VERSION 5.7 ;
BUSBITCHARS "[]" ;
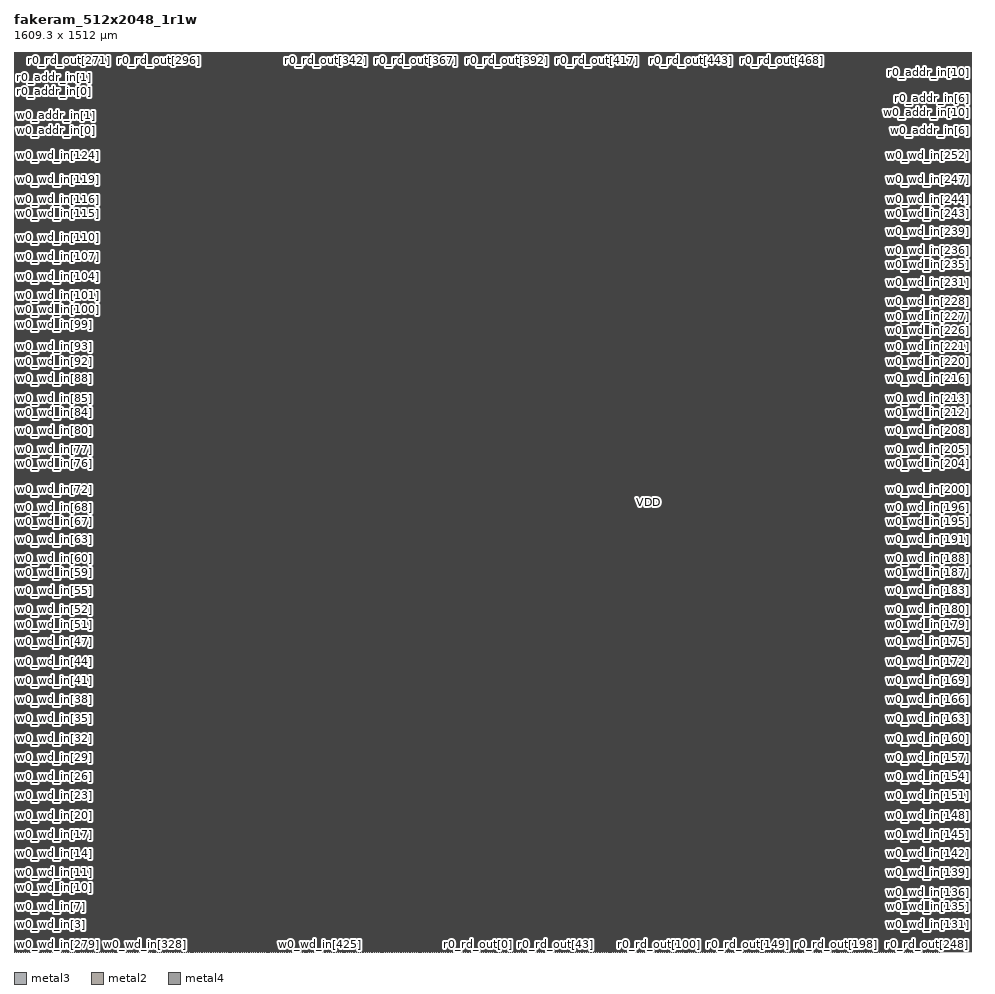
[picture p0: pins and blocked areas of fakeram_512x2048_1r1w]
MACRO fakeram_512x2048_1r1w
  FOREIGN fakeram_512x2048_1r1w 0 0 ;
  SYMMETRY X Y R90 ;
  SIZE 1609.300 BY 1512.000 ;
  CLASS BLOCK ;
  PIN w0_wd_in[0]
    DIRECTION INPUT ;
    USE SIGNAL ;
    SHAPE ABUTMENT ;
    PORT
      LAYER metal3 ;
      RECT 0.000 0.805 0.210 0.875 ;
    END
  END w0_wd_in[0]
  PIN w0_wd_in[1]
    DIRECTION INPUT ;
    USE SIGNAL ;
    SHAPE ABUTMENT ;
    PORT
      LAYER metal3 ;
      RECT 0.000 11.585 0.210 11.655 ;
    END
  END w0_wd_in[1]
  PIN w0_wd_in[2]
    DIRECTION INPUT ;
    USE SIGNAL ;
    SHAPE ABUTMENT ;
    PORT
      LAYER metal3 ;
      RECT 0.000 22.365 0.210 22.435 ;
    END
  END w0_wd_in[2]
  PIN w0_wd_in[3]
    DIRECTION INPUT ;
    USE SIGNAL ;
    SHAPE ABUTMENT ;
    PORT
      LAYER metal3 ;
      RECT 0.000 33.145 0.210 33.215 ;
    END
  END w0_wd_in[3]
  PIN w0_wd_in[4]
    DIRECTION INPUT ;
    USE SIGNAL ;
    SHAPE ABUTMENT ;
    PORT
      LAYER metal3 ;
      RECT 0.000 43.925 0.210 43.995 ;
    END
  END w0_wd_in[4]
  PIN w0_wd_in[5]
    DIRECTION INPUT ;
    USE SIGNAL ;
    SHAPE ABUTMENT ;
    PORT
      LAYER metal3 ;
      RECT 0.000 54.705 0.210 54.775 ;
    END
  END w0_wd_in[5]
  PIN w0_wd_in[6]
    DIRECTION INPUT ;
    USE SIGNAL ;
    SHAPE ABUTMENT ;
    PORT
      LAYER metal3 ;
      RECT 0.000 65.485 0.210 65.555 ;
    END
  END w0_wd_in[6]
  PIN w0_wd_in[7]
    DIRECTION INPUT ;
    USE SIGNAL ;
    SHAPE ABUTMENT ;
    PORT
      LAYER metal3 ;
      RECT 0.000 76.265 0.210 76.335 ;
    END
  END w0_wd_in[7]
  PIN w0_wd_in[8]
    DIRECTION INPUT ;
    USE SIGNAL ;
    SHAPE ABUTMENT ;
    PORT
      LAYER metal3 ;
      RECT 0.000 87.045 0.210 87.115 ;
    END
  END w0_wd_in[8]
  PIN w0_wd_in[9]
    DIRECTION INPUT ;
    USE SIGNAL ;
    SHAPE ABUTMENT ;
    PORT
      LAYER metal3 ;
      RECT 0.000 97.825 0.210 97.895 ;
    END
  END w0_wd_in[9]
  PIN w0_wd_in[10]
    DIRECTION INPUT ;
    USE SIGNAL ;
    SHAPE ABUTMENT ;
    PORT
      LAYER metal3 ;
      RECT 0.000 108.605 0.210 108.675 ;
    END
  END w0_wd_in[10]
  PIN w0_wd_in[11]
    DIRECTION INPUT ;
    USE SIGNAL ;
    SHAPE ABUTMENT ;
    PORT
      LAYER metal3 ;
      RECT 0.000 119.385 0.210 119.455 ;
    END
  END w0_wd_in[11]
  PIN w0_wd_in[12]
    DIRECTION INPUT ;
    USE SIGNAL ;
    SHAPE ABUTMENT ;
    PORT
      LAYER metal3 ;
      RECT 0.000 130.165 0.210 130.235 ;
    END
  END w0_wd_in[12]
  PIN w0_wd_in[13]
    DIRECTION INPUT ;
    USE SIGNAL ;
    SHAPE ABUTMENT ;
    PORT
      LAYER metal3 ;
      RECT 0.000 140.945 0.210 141.015 ;
    END
  END w0_wd_in[13]
  PIN w0_wd_in[14]
    DIRECTION INPUT ;
    USE SIGNAL ;
    SHAPE ABUTMENT ;
    PORT
      LAYER metal3 ;
      RECT 0.000 151.725 0.210 151.795 ;
    END
  END w0_wd_in[14]
  PIN w0_wd_in[15]
    DIRECTION INPUT ;
    USE SIGNAL ;
    SHAPE ABUTMENT ;
    PORT
      LAYER metal3 ;
      RECT 0.000 162.505 0.210 162.575 ;
    END
  END w0_wd_in[15]
  PIN w0_wd_in[16]
    DIRECTION INPUT ;
    USE SIGNAL ;
    SHAPE ABUTMENT ;
    PORT
      LAYER metal3 ;
      RECT 0.000 173.285 0.210 173.355 ;
    END
  END w0_wd_in[16]
  PIN w0_wd_in[17]
    DIRECTION INPUT ;
    USE SIGNAL ;
    SHAPE ABUTMENT ;
    PORT
      LAYER metal3 ;
      RECT 0.000 184.065 0.210 184.135 ;
    END
  END w0_wd_in[17]
  PIN w0_wd_in[18]
    DIRECTION INPUT ;
    USE SIGNAL ;
    SHAPE ABUTMENT ;
    PORT
      LAYER metal3 ;
      RECT 0.000 194.845 0.210 194.915 ;
    END
  END w0_wd_in[18]
  PIN w0_wd_in[19]
    DIRECTION INPUT ;
    USE SIGNAL ;
    SHAPE ABUTMENT ;
    PORT
      LAYER metal3 ;
      RECT 0.000 205.625 0.210 205.695 ;
    END
  END w0_wd_in[19]
  PIN w0_wd_in[20]
    DIRECTION INPUT ;
    USE SIGNAL ;
    SHAPE ABUTMENT ;
    PORT
      LAYER metal3 ;
      RECT 0.000 216.405 0.210 216.475 ;
    END
  END w0_wd_in[20]
  PIN w0_wd_in[21]
    DIRECTION INPUT ;
    USE SIGNAL ;
    SHAPE ABUTMENT ;
    PORT
      LAYER metal3 ;
      RECT 0.000 227.185 0.210 227.255 ;
    END
  END w0_wd_in[21]
  PIN w0_wd_in[22]
    DIRECTION INPUT ;
    USE SIGNAL ;
    SHAPE ABUTMENT ;
    PORT
      LAYER metal3 ;
      RECT 0.000 237.965 0.210 238.035 ;
    END
  END w0_wd_in[22]
  PIN w0_wd_in[23]
    DIRECTION INPUT ;
    USE SIGNAL ;
    SHAPE ABUTMENT ;
    PORT
      LAYER metal3 ;
      RECT 0.000 248.745 0.210 248.815 ;
    END
  END w0_wd_in[23]
  PIN w0_wd_in[24]
    DIRECTION INPUT ;
    USE SIGNAL ;
    SHAPE ABUTMENT ;
    PORT
      LAYER metal3 ;
      RECT 0.000 259.525 0.210 259.595 ;
    END
  END w0_wd_in[24]
  PIN w0_wd_in[25]
    DIRECTION INPUT ;
    USE SIGNAL ;
    SHAPE ABUTMENT ;
    PORT
      LAYER metal3 ;
      RECT 0.000 270.305 0.210 270.375 ;
    END
  END w0_wd_in[25]
  PIN w0_wd_in[26]
    DIRECTION INPUT ;
    USE SIGNAL ;
    SHAPE ABUTMENT ;
    PORT
      LAYER metal3 ;
      RECT 0.000 281.085 0.210 281.155 ;
    END
  END w0_wd_in[26]
  PIN w0_wd_in[27]
    DIRECTION INPUT ;
    USE SIGNAL ;
    SHAPE ABUTMENT ;
    PORT
      LAYER metal3 ;
      RECT 0.000 291.865 0.210 291.935 ;
    END
  END w0_wd_in[27]
  PIN w0_wd_in[28]
    DIRECTION INPUT ;
    USE SIGNAL ;
    SHAPE ABUTMENT ;
    PORT
      LAYER metal3 ;
      RECT 0.000 302.645 0.210 302.715 ;
    END
  END w0_wd_in[28]
  PIN w0_wd_in[29]
    DIRECTION INPUT ;
    USE SIGNAL ;
    SHAPE ABUTMENT ;
    PORT
      LAYER metal3 ;
      RECT 0.000 313.425 0.210 313.495 ;
    END
  END w0_wd_in[29]
  PIN w0_wd_in[30]
    DIRECTION INPUT ;
    USE SIGNAL ;
    SHAPE ABUTMENT ;
    PORT
      LAYER metal3 ;
      RECT 0.000 324.205 0.210 324.275 ;
    END
  END w0_wd_in[30]
  PIN w0_wd_in[31]
    DIRECTION INPUT ;
    USE SIGNAL ;
    SHAPE ABUTMENT ;
    PORT
      LAYER metal3 ;
      RECT 0.000 334.985 0.210 335.055 ;
    END
  END w0_wd_in[31]
  PIN w0_wd_in[32]
    DIRECTION INPUT ;
    USE SIGNAL ;
    SHAPE ABUTMENT ;
    PORT
      LAYER metal3 ;
      RECT 0.000 345.765 0.210 345.835 ;
    END
  END w0_wd_in[32]
  PIN w0_wd_in[33]
    DIRECTION INPUT ;
    USE SIGNAL ;
    SHAPE ABUTMENT ;
    PORT
      LAYER metal3 ;
      RECT 0.000 356.545 0.210 356.615 ;
    END
  END w0_wd_in[33]
  PIN w0_wd_in[34]
    DIRECTION INPUT ;
    USE SIGNAL ;
    SHAPE ABUTMENT ;
    PORT
      LAYER metal3 ;
      RECT 0.000 367.325 0.210 367.395 ;
    END
  END w0_wd_in[34]
  PIN w0_wd_in[35]
    DIRECTION INPUT ;
    USE SIGNAL ;
    SHAPE ABUTMENT ;
    PORT
      LAYER metal3 ;
      RECT 0.000 378.105 0.210 378.175 ;
    END
  END w0_wd_in[35]
  PIN w0_wd_in[36]
    DIRECTION INPUT ;
    USE SIGNAL ;
    SHAPE ABUTMENT ;
    PORT
      LAYER metal3 ;
      RECT 0.000 388.885 0.210 388.955 ;
    END
  END w0_wd_in[36]
  PIN w0_wd_in[37]
    DIRECTION INPUT ;
    USE SIGNAL ;
    SHAPE ABUTMENT ;
    PORT
      LAYER metal3 ;
      RECT 0.000 399.665 0.210 399.735 ;
    END
  END w0_wd_in[37]
  PIN w0_wd_in[38]
    DIRECTION INPUT ;
    USE SIGNAL ;
    SHAPE ABUTMENT ;
    PORT
      LAYER metal3 ;
      RECT 0.000 410.445 0.210 410.515 ;
    END
  END w0_wd_in[38]
  PIN w0_wd_in[39]
    DIRECTION INPUT ;
    USE SIGNAL ;
    SHAPE ABUTMENT ;
    PORT
      LAYER metal3 ;
      RECT 0.000 421.225 0.210 421.295 ;
    END
  END w0_wd_in[39]
  PIN w0_wd_in[40]
    DIRECTION INPUT ;
    USE SIGNAL ;
    SHAPE ABUTMENT ;
    PORT
      LAYER metal3 ;
      RECT 0.000 432.005 0.210 432.075 ;
    END
  END w0_wd_in[40]
  PIN w0_wd_in[41]
    DIRECTION INPUT ;
    USE SIGNAL ;
    SHAPE ABUTMENT ;
    PORT
      LAYER metal3 ;
      RECT 0.000 442.785 0.210 442.855 ;
    END
  END w0_wd_in[41]
  PIN w0_wd_in[42]
    DIRECTION INPUT ;
    USE SIGNAL ;
    SHAPE ABUTMENT ;
    PORT
      LAYER metal3 ;
      RECT 0.000 453.565 0.210 453.635 ;
    END
  END w0_wd_in[42]
  PIN w0_wd_in[43]
    DIRECTION INPUT ;
    USE SIGNAL ;
    SHAPE ABUTMENT ;
    PORT
      LAYER metal3 ;
      RECT 0.000 464.345 0.210 464.415 ;
    END
  END w0_wd_in[43]
  PIN w0_wd_in[44]
    DIRECTION INPUT ;
    USE SIGNAL ;
    SHAPE ABUTMENT ;
    PORT
      LAYER metal3 ;
      RECT 0.000 475.125 0.210 475.195 ;
    END
  END w0_wd_in[44]
  PIN w0_wd_in[45]
    DIRECTION INPUT ;
    USE SIGNAL ;
    SHAPE ABUTMENT ;
    PORT
      LAYER metal3 ;
      RECT 0.000 485.905 0.210 485.975 ;
    END
  END w0_wd_in[45]
  PIN w0_wd_in[46]
    DIRECTION INPUT ;
    USE SIGNAL ;
    SHAPE ABUTMENT ;
    PORT
      LAYER metal3 ;
      RECT 0.000 496.685 0.210 496.755 ;
    END
  END w0_wd_in[46]
  PIN w0_wd_in[47]
    DIRECTION INPUT ;
    USE SIGNAL ;
    SHAPE ABUTMENT ;
    PORT
      LAYER metal3 ;
      RECT 0.000 507.465 0.210 507.535 ;
    END
  END w0_wd_in[47]
  PIN w0_wd_in[48]
    DIRECTION INPUT ;
    USE SIGNAL ;
    SHAPE ABUTMENT ;
    PORT
      LAYER metal3 ;
      RECT 0.000 518.245 0.210 518.315 ;
    END
  END w0_wd_in[48]
  PIN w0_wd_in[49]
    DIRECTION INPUT ;
    USE SIGNAL ;
    SHAPE ABUTMENT ;
    PORT
      LAYER metal3 ;
      RECT 0.000 529.025 0.210 529.095 ;
    END
  END w0_wd_in[49]
  PIN w0_wd_in[50]
    DIRECTION INPUT ;
    USE SIGNAL ;
    SHAPE ABUTMENT ;
    PORT
      LAYER metal3 ;
      RECT 0.000 539.805 0.210 539.875 ;
    END
  END w0_wd_in[50]
  PIN w0_wd_in[51]
    DIRECTION INPUT ;
    USE SIGNAL ;
    SHAPE ABUTMENT ;
    PORT
      LAYER metal3 ;
      RECT 0.000 550.585 0.210 550.655 ;
    END
  END w0_wd_in[51]
  PIN w0_wd_in[52]
    DIRECTION INPUT ;
    USE SIGNAL ;
    SHAPE ABUTMENT ;
    PORT
      LAYER metal3 ;
      RECT 0.000 561.365 0.210 561.435 ;
    END
  END w0_wd_in[52]
  PIN w0_wd_in[53]
    DIRECTION INPUT ;
    USE SIGNAL ;
    SHAPE ABUTMENT ;
    PORT
      LAYER metal3 ;
      RECT 0.000 572.145 0.210 572.215 ;
    END
  END w0_wd_in[53]
  PIN w0_wd_in[54]
    DIRECTION INPUT ;
    USE SIGNAL ;
    SHAPE ABUTMENT ;
    PORT
      LAYER metal3 ;
      RECT 0.000 582.925 0.210 582.995 ;
    END
  END w0_wd_in[54]
  PIN w0_wd_in[55]
    DIRECTION INPUT ;
    USE SIGNAL ;
    SHAPE ABUTMENT ;
    PORT
      LAYER metal3 ;
      RECT 0.000 593.705 0.210 593.775 ;
    END
  END w0_wd_in[55]
  PIN w0_wd_in[56]
    DIRECTION INPUT ;
    USE SIGNAL ;
    SHAPE ABUTMENT ;
    PORT
      LAYER metal3 ;
      RECT 0.000 604.485 0.210 604.555 ;
    END
  END w0_wd_in[56]
  PIN w0_wd_in[57]
    DIRECTION INPUT ;
    USE SIGNAL ;
    SHAPE ABUTMENT ;
    PORT
      LAYER metal3 ;
      RECT 0.000 615.265 0.210 615.335 ;
    END
  END w0_wd_in[57]
  PIN w0_wd_in[58]
    DIRECTION INPUT ;
    USE SIGNAL ;
    SHAPE ABUTMENT ;
    PORT
      LAYER metal3 ;
      RECT 0.000 626.045 0.210 626.115 ;
    END
  END w0_wd_in[58]
  PIN w0_wd_in[59]
    DIRECTION INPUT ;
    USE SIGNAL ;
    SHAPE ABUTMENT ;
    PORT
      LAYER metal3 ;
      RECT 0.000 636.825 0.210 636.895 ;
    END
  END w0_wd_in[59]
  PIN w0_wd_in[60]
    DIRECTION INPUT ;
    USE SIGNAL ;
    SHAPE ABUTMENT ;
    PORT
      LAYER metal3 ;
      RECT 0.000 647.605 0.210 647.675 ;
    END
  END w0_wd_in[60]
  PIN w0_wd_in[61]
    DIRECTION INPUT ;
    USE SIGNAL ;
    SHAPE ABUTMENT ;
    PORT
      LAYER metal3 ;
      RECT 0.000 658.385 0.210 658.455 ;
    END
  END w0_wd_in[61]
  PIN w0_wd_in[62]
    DIRECTION INPUT ;
    USE SIGNAL ;
    SHAPE ABUTMENT ;
    PORT
      LAYER metal3 ;
      RECT 0.000 669.165 0.210 669.235 ;
    END
  END w0_wd_in[62]
  PIN w0_wd_in[63]
    DIRECTION INPUT ;
    USE SIGNAL ;
    SHAPE ABUTMENT ;
    PORT
      LAYER metal3 ;
      RECT 0.000 679.945 0.210 680.015 ;
    END
  END w0_wd_in[63]
  PIN w0_wd_in[64]
    DIRECTION INPUT ;
    USE SIGNAL ;
    SHAPE ABUTMENT ;
    PORT
      LAYER metal3 ;
      RECT 0.000 690.725 0.210 690.795 ;
    END
  END w0_wd_in[64]
  PIN w0_wd_in[65]
    DIRECTION INPUT ;
    USE SIGNAL ;
    SHAPE ABUTMENT ;
    PORT
      LAYER metal3 ;
      RECT 0.000 701.505 0.210 701.575 ;
    END
  END w0_wd_in[65]
  PIN w0_wd_in[66]
    DIRECTION INPUT ;
    USE SIGNAL ;
    SHAPE ABUTMENT ;
    PORT
      LAYER metal3 ;
      RECT 0.000 712.285 0.210 712.355 ;
    END
  END w0_wd_in[66]
  PIN w0_wd_in[67]
    DIRECTION INPUT ;
    USE SIGNAL ;
    SHAPE ABUTMENT ;
    PORT
      LAYER metal3 ;
      RECT 0.000 723.065 0.210 723.135 ;
    END
  END w0_wd_in[67]
  PIN w0_wd_in[68]
    DIRECTION INPUT ;
    USE SIGNAL ;
    SHAPE ABUTMENT ;
    PORT
      LAYER metal3 ;
      RECT 0.000 733.845 0.210 733.915 ;
    END
  END w0_wd_in[68]
  PIN w0_wd_in[69]
    DIRECTION INPUT ;
    USE SIGNAL ;
    SHAPE ABUTMENT ;
    PORT
      LAYER metal3 ;
      RECT 0.000 744.625 0.210 744.695 ;
    END
  END w0_wd_in[69]
  PIN w0_wd_in[70]
    DIRECTION INPUT ;
    USE SIGNAL ;
    SHAPE ABUTMENT ;
    PORT
      LAYER metal3 ;
      RECT 0.000 755.405 0.210 755.475 ;
    END
  END w0_wd_in[70]
  PIN w0_wd_in[71]
    DIRECTION INPUT ;
    USE SIGNAL ;
    SHAPE ABUTMENT ;
    PORT
      LAYER metal3 ;
      RECT 0.000 766.185 0.210 766.255 ;
    END
  END w0_wd_in[71]
  PIN w0_wd_in[72]
    DIRECTION INPUT ;
    USE SIGNAL ;
    SHAPE ABUTMENT ;
    PORT
      LAYER metal3 ;
      RECT 0.000 776.965 0.210 777.035 ;
    END
  END w0_wd_in[72]
  PIN w0_wd_in[73]
    DIRECTION INPUT ;
    USE SIGNAL ;
    SHAPE ABUTMENT ;
    PORT
      LAYER metal3 ;
      RECT 0.000 787.745 0.210 787.815 ;
    END
  END w0_wd_in[73]
  PIN w0_wd_in[74]
    DIRECTION INPUT ;
    USE SIGNAL ;
    SHAPE ABUTMENT ;
    PORT
      LAYER metal3 ;
      RECT 0.000 798.525 0.210 798.595 ;
    END
  END w0_wd_in[74]
  PIN w0_wd_in[75]
    DIRECTION INPUT ;
    USE SIGNAL ;
    SHAPE ABUTMENT ;
    PORT
      LAYER metal3 ;
      RECT 0.000 809.305 0.210 809.375 ;
    END
  END w0_wd_in[75]
  PIN w0_wd_in[76]
    DIRECTION INPUT ;
    USE SIGNAL ;
    SHAPE ABUTMENT ;
    PORT
      LAYER metal3 ;
      RECT 0.000 820.085 0.210 820.155 ;
    END
  END w0_wd_in[76]
  PIN w0_wd_in[77]
    DIRECTION INPUT ;
    USE SIGNAL ;
    SHAPE ABUTMENT ;
    PORT
      LAYER metal3 ;
      RECT 0.000 830.865 0.210 830.935 ;
    END
  END w0_wd_in[77]
  PIN w0_wd_in[78]
    DIRECTION INPUT ;
    USE SIGNAL ;
    SHAPE ABUTMENT ;
    PORT
      LAYER metal3 ;
      RECT 0.000 841.645 0.210 841.715 ;
    END
  END w0_wd_in[78]
  PIN w0_wd_in[79]
    DIRECTION INPUT ;
    USE SIGNAL ;
    SHAPE ABUTMENT ;
    PORT
      LAYER metal3 ;
      RECT 0.000 852.425 0.210 852.495 ;
    END
  END w0_wd_in[79]
  PIN w0_wd_in[80]
    DIRECTION INPUT ;
    USE SIGNAL ;
    SHAPE ABUTMENT ;
    PORT
      LAYER metal3 ;
      RECT 0.000 863.205 0.210 863.275 ;
    END
  END w0_wd_in[80]
  PIN w0_wd_in[81]
    DIRECTION INPUT ;
    USE SIGNAL ;
    SHAPE ABUTMENT ;
    PORT
      LAYER metal3 ;
      RECT 0.000 873.985 0.210 874.055 ;
    END
  END w0_wd_in[81]
  PIN w0_wd_in[82]
    DIRECTION INPUT ;
    USE SIGNAL ;
    SHAPE ABUTMENT ;
    PORT
      LAYER metal3 ;
      RECT 0.000 884.765 0.210 884.835 ;
    END
  END w0_wd_in[82]
  PIN w0_wd_in[83]
    DIRECTION INPUT ;
    USE SIGNAL ;
    SHAPE ABUTMENT ;
    PORT
      LAYER metal3 ;
      RECT 0.000 895.545 0.210 895.615 ;
    END
  END w0_wd_in[83]
  PIN w0_wd_in[84]
    DIRECTION INPUT ;
    USE SIGNAL ;
    SHAPE ABUTMENT ;
    PORT
      LAYER metal3 ;
      RECT 0.000 906.325 0.210 906.395 ;
    END
  END w0_wd_in[84]
  PIN w0_wd_in[85]
    DIRECTION INPUT ;
    USE SIGNAL ;
    SHAPE ABUTMENT ;
    PORT
      LAYER metal3 ;
      RECT 0.000 917.105 0.210 917.175 ;
    END
  END w0_wd_in[85]
  PIN w0_wd_in[86]
    DIRECTION INPUT ;
    USE SIGNAL ;
    SHAPE ABUTMENT ;
    PORT
      LAYER metal3 ;
      RECT 0.000 927.885 0.210 927.955 ;
    END
  END w0_wd_in[86]
  PIN w0_wd_in[87]
    DIRECTION INPUT ;
    USE SIGNAL ;
    SHAPE ABUTMENT ;
    PORT
      LAYER metal3 ;
      RECT 0.000 938.665 0.210 938.735 ;
    END
  END w0_wd_in[87]
  PIN w0_wd_in[88]
    DIRECTION INPUT ;
    USE SIGNAL ;
    SHAPE ABUTMENT ;
    PORT
      LAYER metal3 ;
      RECT 0.000 949.445 0.210 949.515 ;
    END
  END w0_wd_in[88]
  PIN w0_wd_in[89]
    DIRECTION INPUT ;
    USE SIGNAL ;
    SHAPE ABUTMENT ;
    PORT
      LAYER metal3 ;
      RECT 0.000 960.225 0.210 960.295 ;
    END
  END w0_wd_in[89]
  PIN w0_wd_in[90]
    DIRECTION INPUT ;
    USE SIGNAL ;
    SHAPE ABUTMENT ;
    PORT
      LAYER metal3 ;
      RECT 0.000 971.005 0.210 971.075 ;
    END
  END w0_wd_in[90]
  PIN w0_wd_in[91]
    DIRECTION INPUT ;
    USE SIGNAL ;
    SHAPE ABUTMENT ;
    PORT
      LAYER metal3 ;
      RECT 0.000 981.785 0.210 981.855 ;
    END
  END w0_wd_in[91]
  PIN w0_wd_in[92]
    DIRECTION INPUT ;
    USE SIGNAL ;
    SHAPE ABUTMENT ;
    PORT
      LAYER metal3 ;
      RECT 0.000 992.565 0.210 992.635 ;
    END
  END w0_wd_in[92]
  PIN w0_wd_in[93]
    DIRECTION INPUT ;
    USE SIGNAL ;
    SHAPE ABUTMENT ;
    PORT
      LAYER metal3 ;
      RECT 0.000 1003.345 0.210 1003.415 ;
    END
  END w0_wd_in[93]
  PIN w0_wd_in[94]
    DIRECTION INPUT ;
    USE SIGNAL ;
    SHAPE ABUTMENT ;
    PORT
      LAYER metal3 ;
      RECT 0.000 1014.125 0.210 1014.195 ;
    END
  END w0_wd_in[94]
  PIN w0_wd_in[95]
    DIRECTION INPUT ;
    USE SIGNAL ;
    SHAPE ABUTMENT ;
    PORT
      LAYER metal3 ;
      RECT 0.000 1024.905 0.210 1024.975 ;
    END
  END w0_wd_in[95]
  PIN w0_wd_in[96]
    DIRECTION INPUT ;
    USE SIGNAL ;
    SHAPE ABUTMENT ;
    PORT
      LAYER metal3 ;
      RECT 0.000 1035.685 0.210 1035.755 ;
    END
  END w0_wd_in[96]
  PIN w0_wd_in[97]
    DIRECTION INPUT ;
    USE SIGNAL ;
    SHAPE ABUTMENT ;
    PORT
      LAYER metal3 ;
      RECT 0.000 1046.465 0.210 1046.535 ;
    END
  END w0_wd_in[97]
  PIN w0_wd_in[98]
    DIRECTION INPUT ;
    USE SIGNAL ;
    SHAPE ABUTMENT ;
    PORT
      LAYER metal3 ;
      RECT 0.000 1057.245 0.210 1057.315 ;
    END
  END w0_wd_in[98]
  PIN w0_wd_in[99]
    DIRECTION INPUT ;
    USE SIGNAL ;
    SHAPE ABUTMENT ;
    PORT
      LAYER metal3 ;
      RECT 0.000 1068.025 0.210 1068.095 ;
    END
  END w0_wd_in[99]
  PIN w0_wd_in[100]
    DIRECTION INPUT ;
    USE SIGNAL ;
    SHAPE ABUTMENT ;
    PORT
      LAYER metal3 ;
      RECT 0.000 1078.805 0.210 1078.875 ;
    END
  END w0_wd_in[100]
  PIN w0_wd_in[101]
    DIRECTION INPUT ;
    USE SIGNAL ;
    SHAPE ABUTMENT ;
    PORT
      LAYER metal3 ;
      RECT 0.000 1089.585 0.210 1089.655 ;
    END
  END w0_wd_in[101]
  PIN w0_wd_in[102]
    DIRECTION INPUT ;
    USE SIGNAL ;
    SHAPE ABUTMENT ;
    PORT
      LAYER metal3 ;
      RECT 0.000 1100.365 0.210 1100.435 ;
    END
  END w0_wd_in[102]
  PIN w0_wd_in[103]
    DIRECTION INPUT ;
    USE SIGNAL ;
    SHAPE ABUTMENT ;
    PORT
      LAYER metal3 ;
      RECT 0.000 1111.145 0.210 1111.215 ;
    END
  END w0_wd_in[103]
  PIN w0_wd_in[104]
    DIRECTION INPUT ;
    USE SIGNAL ;
    SHAPE ABUTMENT ;
    PORT
      LAYER metal3 ;
      RECT 0.000 1121.925 0.210 1121.995 ;
    END
  END w0_wd_in[104]
  PIN w0_wd_in[105]
    DIRECTION INPUT ;
    USE SIGNAL ;
    SHAPE ABUTMENT ;
    PORT
      LAYER metal3 ;
      RECT 0.000 1132.705 0.210 1132.775 ;
    END
  END w0_wd_in[105]
  PIN w0_wd_in[106]
    DIRECTION INPUT ;
    USE SIGNAL ;
    SHAPE ABUTMENT ;
    PORT
      LAYER metal3 ;
      RECT 0.000 1143.485 0.210 1143.555 ;
    END
  END w0_wd_in[106]
  PIN w0_wd_in[107]
    DIRECTION INPUT ;
    USE SIGNAL ;
    SHAPE ABUTMENT ;
    PORT
      LAYER metal3 ;
      RECT 0.000 1154.265 0.210 1154.335 ;
    END
  END w0_wd_in[107]
  PIN w0_wd_in[108]
    DIRECTION INPUT ;
    USE SIGNAL ;
    SHAPE ABUTMENT ;
    PORT
      LAYER metal3 ;
      RECT 0.000 1165.045 0.210 1165.115 ;
    END
  END w0_wd_in[108]
  PIN w0_wd_in[109]
    DIRECTION INPUT ;
    USE SIGNAL ;
    SHAPE ABUTMENT ;
    PORT
      LAYER metal3 ;
      RECT 0.000 1175.825 0.210 1175.895 ;
    END
  END w0_wd_in[109]
  PIN w0_wd_in[110]
    DIRECTION INPUT ;
    USE SIGNAL ;
    SHAPE ABUTMENT ;
    PORT
      LAYER metal3 ;
      RECT 0.000 1186.605 0.210 1186.675 ;
    END
  END w0_wd_in[110]
  PIN w0_wd_in[111]
    DIRECTION INPUT ;
    USE SIGNAL ;
    SHAPE ABUTMENT ;
    PORT
      LAYER metal3 ;
      RECT 0.000 1197.385 0.210 1197.455 ;
    END
  END w0_wd_in[111]
  PIN w0_wd_in[112]
    DIRECTION INPUT ;
    USE SIGNAL ;
    SHAPE ABUTMENT ;
    PORT
      LAYER metal3 ;
      RECT 0.000 1208.165 0.210 1208.235 ;
    END
  END w0_wd_in[112]
  PIN w0_wd_in[113]
    DIRECTION INPUT ;
    USE SIGNAL ;
    SHAPE ABUTMENT ;
    PORT
      LAYER metal3 ;
      RECT 0.000 1218.945 0.210 1219.015 ;
    END
  END w0_wd_in[113]
  PIN w0_wd_in[114]
    DIRECTION INPUT ;
    USE SIGNAL ;
    SHAPE ABUTMENT ;
    PORT
      LAYER metal3 ;
      RECT 0.000 1229.725 0.210 1229.795 ;
    END
  END w0_wd_in[114]
  PIN w0_wd_in[115]
    DIRECTION INPUT ;
    USE SIGNAL ;
    SHAPE ABUTMENT ;
    PORT
      LAYER metal3 ;
      RECT 0.000 1240.505 0.210 1240.575 ;
    END
  END w0_wd_in[115]
  PIN w0_wd_in[116]
    DIRECTION INPUT ;
    USE SIGNAL ;
    SHAPE ABUTMENT ;
    PORT
      LAYER metal3 ;
      RECT 0.000 1251.285 0.210 1251.355 ;
    END
  END w0_wd_in[116]
  PIN w0_wd_in[117]
    DIRECTION INPUT ;
    USE SIGNAL ;
    SHAPE ABUTMENT ;
    PORT
      LAYER metal3 ;
      RECT 0.000 1262.065 0.210 1262.135 ;
    END
  END w0_wd_in[117]
  PIN w0_wd_in[118]
    DIRECTION INPUT ;
    USE SIGNAL ;
    SHAPE ABUTMENT ;
    PORT
      LAYER metal3 ;
      RECT 0.000 1272.845 0.210 1272.915 ;
    END
  END w0_wd_in[118]
  PIN w0_wd_in[119]
    DIRECTION INPUT ;
    USE SIGNAL ;
    SHAPE ABUTMENT ;
    PORT
      LAYER metal3 ;
      RECT 0.000 1283.625 0.210 1283.695 ;
    END
  END w0_wd_in[119]
  PIN w0_wd_in[120]
    DIRECTION INPUT ;
    USE SIGNAL ;
    SHAPE ABUTMENT ;
    PORT
      LAYER metal3 ;
      RECT 0.000 1294.405 0.210 1294.475 ;
    END
  END w0_wd_in[120]
  PIN w0_wd_in[121]
    DIRECTION INPUT ;
    USE SIGNAL ;
    SHAPE ABUTMENT ;
    PORT
      LAYER metal3 ;
      RECT 0.000 1305.185 0.210 1305.255 ;
    END
  END w0_wd_in[121]
  PIN w0_wd_in[122]
    DIRECTION INPUT ;
    USE SIGNAL ;
    SHAPE ABUTMENT ;
    PORT
      LAYER metal3 ;
      RECT 0.000 1315.965 0.210 1316.035 ;
    END
  END w0_wd_in[122]
  PIN w0_wd_in[123]
    DIRECTION INPUT ;
    USE SIGNAL ;
    SHAPE ABUTMENT ;
    PORT
      LAYER metal3 ;
      RECT 0.000 1326.745 0.210 1326.815 ;
    END
  END w0_wd_in[123]
  PIN w0_wd_in[124]
    DIRECTION INPUT ;
    USE SIGNAL ;
    SHAPE ABUTMENT ;
    PORT
      LAYER metal3 ;
      RECT 0.000 1337.525 0.210 1337.595 ;
    END
  END w0_wd_in[124]
  PIN w0_wd_in[125]
    DIRECTION INPUT ;
    USE SIGNAL ;
    SHAPE ABUTMENT ;
    PORT
      LAYER metal3 ;
      RECT 0.000 1348.305 0.210 1348.375 ;
    END
  END w0_wd_in[125]
  PIN w0_wd_in[126]
    DIRECTION INPUT ;
    USE SIGNAL ;
    SHAPE ABUTMENT ;
    PORT
      LAYER metal3 ;
      RECT 0.000 1359.085 0.210 1359.155 ;
    END
  END w0_wd_in[126]
  PIN w0_wd_in[127]
    DIRECTION INPUT ;
    USE SIGNAL ;
    SHAPE ABUTMENT ;
    PORT
      LAYER metal3 ;
      RECT 0.000 1369.865 0.210 1369.935 ;
    END
  END w0_wd_in[127]
  PIN w0_wd_in[128]
    DIRECTION INPUT ;
    USE SIGNAL ;
    SHAPE ABUTMENT ;
    PORT
      LAYER metal3 ;
      RECT 1609.090 0.805 1609.300 0.875 ;
    END
  END w0_wd_in[128]
  PIN w0_wd_in[129]
    DIRECTION INPUT ;
    USE SIGNAL ;
    SHAPE ABUTMENT ;
    PORT
      LAYER metal3 ;
      RECT 1609.090 11.585 1609.300 11.655 ;
    END
  END w0_wd_in[129]
  PIN w0_wd_in[130]
    DIRECTION INPUT ;
    USE SIGNAL ;
    SHAPE ABUTMENT ;
    PORT
      LAYER metal3 ;
      RECT 1609.090 22.365 1609.300 22.435 ;
    END
  END w0_wd_in[130]
  PIN w0_wd_in[131]
    DIRECTION INPUT ;
    USE SIGNAL ;
    SHAPE ABUTMENT ;
    PORT
      LAYER metal3 ;
      RECT 1609.090 33.145 1609.300 33.215 ;
    END
  END w0_wd_in[131]
  PIN w0_wd_in[132]
    DIRECTION INPUT ;
    USE SIGNAL ;
    SHAPE ABUTMENT ;
    PORT
      LAYER metal3 ;
      RECT 1609.090 43.925 1609.300 43.995 ;
    END
  END w0_wd_in[132]
  PIN w0_wd_in[133]
    DIRECTION INPUT ;
    USE SIGNAL ;
    SHAPE ABUTMENT ;
    PORT
      LAYER metal3 ;
      RECT 1609.090 54.705 1609.300 54.775 ;
    END
  END w0_wd_in[133]
  PIN w0_wd_in[134]
    DIRECTION INPUT ;
    USE SIGNAL ;
    SHAPE ABUTMENT ;
    PORT
      LAYER metal3 ;
      RECT 1609.090 65.485 1609.300 65.555 ;
    END
  END w0_wd_in[134]
  PIN w0_wd_in[135]
    DIRECTION INPUT ;
    USE SIGNAL ;
    SHAPE ABUTMENT ;
    PORT
      LAYER metal3 ;
      RECT 1609.090 76.265 1609.300 76.335 ;
    END
  END w0_wd_in[135]
  PIN w0_wd_in[136]
    DIRECTION INPUT ;
    USE SIGNAL ;
    SHAPE ABUTMENT ;
    PORT
      LAYER metal3 ;
      RECT 1609.090 87.045 1609.300 87.115 ;
    END
  END w0_wd_in[136]
  PIN w0_wd_in[137]
    DIRECTION INPUT ;
    USE SIGNAL ;
    SHAPE ABUTMENT ;
    PORT
      LAYER metal3 ;
      RECT 1609.090 97.825 1609.300 97.895 ;
    END
  END w0_wd_in[137]
  PIN w0_wd_in[138]
    DIRECTION INPUT ;
    USE SIGNAL ;
    SHAPE ABUTMENT ;
    PORT
      LAYER metal3 ;
      RECT 1609.090 108.605 1609.300 108.675 ;
    END
  END w0_wd_in[138]
  PIN w0_wd_in[139]
    DIRECTION INPUT ;
    USE SIGNAL ;
    SHAPE ABUTMENT ;
    PORT
      LAYER metal3 ;
      RECT 1609.090 119.385 1609.300 119.455 ;
    END
  END w0_wd_in[139]
  PIN w0_wd_in[140]
    DIRECTION INPUT ;
    USE SIGNAL ;
    SHAPE ABUTMENT ;
    PORT
      LAYER metal3 ;
      RECT 1609.090 130.165 1609.300 130.235 ;
    END
  END w0_wd_in[140]
  PIN w0_wd_in[141]
    DIRECTION INPUT ;
    USE SIGNAL ;
    SHAPE ABUTMENT ;
    PORT
      LAYER metal3 ;
      RECT 1609.090 140.945 1609.300 141.015 ;
    END
  END w0_wd_in[141]
  PIN w0_wd_in[142]
    DIRECTION INPUT ;
    USE SIGNAL ;
    SHAPE ABUTMENT ;
    PORT
      LAYER metal3 ;
      RECT 1609.090 151.725 1609.300 151.795 ;
    END
  END w0_wd_in[142]
  PIN w0_wd_in[143]
    DIRECTION INPUT ;
    USE SIGNAL ;
    SHAPE ABUTMENT ;
    PORT
      LAYER metal3 ;
      RECT 1609.090 162.505 1609.300 162.575 ;
    END
  END w0_wd_in[143]
  PIN w0_wd_in[144]
    DIRECTION INPUT ;
    USE SIGNAL ;
    SHAPE ABUTMENT ;
    PORT
      LAYER metal3 ;
      RECT 1609.090 173.285 1609.300 173.355 ;
    END
  END w0_wd_in[144]
  PIN w0_wd_in[145]
    DIRECTION INPUT ;
    USE SIGNAL ;
    SHAPE ABUTMENT ;
    PORT
      LAYER metal3 ;
      RECT 1609.090 184.065 1609.300 184.135 ;
    END
  END w0_wd_in[145]
  PIN w0_wd_in[146]
    DIRECTION INPUT ;
    USE SIGNAL ;
    SHAPE ABUTMENT ;
    PORT
      LAYER metal3 ;
      RECT 1609.090 194.845 1609.300 194.915 ;
    END
  END w0_wd_in[146]
  PIN w0_wd_in[147]
    DIRECTION INPUT ;
    USE SIGNAL ;
    SHAPE ABUTMENT ;
    PORT
      LAYER metal3 ;
      RECT 1609.090 205.625 1609.300 205.695 ;
    END
  END w0_wd_in[147]
  PIN w0_wd_in[148]
    DIRECTION INPUT ;
    USE SIGNAL ;
    SHAPE ABUTMENT ;
    PORT
      LAYER metal3 ;
      RECT 1609.090 216.405 1609.300 216.475 ;
    END
  END w0_wd_in[148]
  PIN w0_wd_in[149]
    DIRECTION INPUT ;
    USE SIGNAL ;
    SHAPE ABUTMENT ;
    PORT
      LAYER metal3 ;
      RECT 1609.090 227.185 1609.300 227.255 ;
    END
  END w0_wd_in[149]
  PIN w0_wd_in[150]
    DIRECTION INPUT ;
    USE SIGNAL ;
    SHAPE ABUTMENT ;
    PORT
      LAYER metal3 ;
      RECT 1609.090 237.965 1609.300 238.035 ;
    END
  END w0_wd_in[150]
  PIN w0_wd_in[151]
    DIRECTION INPUT ;
    USE SIGNAL ;
    SHAPE ABUTMENT ;
    PORT
      LAYER metal3 ;
      RECT 1609.090 248.745 1609.300 248.815 ;
    END
  END w0_wd_in[151]
  PIN w0_wd_in[152]
    DIRECTION INPUT ;
    USE SIGNAL ;
    SHAPE ABUTMENT ;
    PORT
      LAYER metal3 ;
      RECT 1609.090 259.525 1609.300 259.595 ;
    END
  END w0_wd_in[152]
  PIN w0_wd_in[153]
    DIRECTION INPUT ;
    USE SIGNAL ;
    SHAPE ABUTMENT ;
    PORT
      LAYER metal3 ;
      RECT 1609.090 270.305 1609.300 270.375 ;
    END
  END w0_wd_in[153]
  PIN w0_wd_in[154]
    DIRECTION INPUT ;
    USE SIGNAL ;
    SHAPE ABUTMENT ;
    PORT
      LAYER metal3 ;
      RECT 1609.090 281.085 1609.300 281.155 ;
    END
  END w0_wd_in[154]
  PIN w0_wd_in[155]
    DIRECTION INPUT ;
    USE SIGNAL ;
    SHAPE ABUTMENT ;
    PORT
      LAYER metal3 ;
      RECT 1609.090 291.865 1609.300 291.935 ;
    END
  END w0_wd_in[155]
  PIN w0_wd_in[156]
    DIRECTION INPUT ;
    USE SIGNAL ;
    SHAPE ABUTMENT ;
    PORT
      LAYER metal3 ;
      RECT 1609.090 302.645 1609.300 302.715 ;
    END
  END w0_wd_in[156]
  PIN w0_wd_in[157]
    DIRECTION INPUT ;
    USE SIGNAL ;
    SHAPE ABUTMENT ;
    PORT
      LAYER metal3 ;
      RECT 1609.090 313.425 1609.300 313.495 ;
    END
  END w0_wd_in[157]
  PIN w0_wd_in[158]
    DIRECTION INPUT ;
    USE SIGNAL ;
    SHAPE ABUTMENT ;
    PORT
      LAYER metal3 ;
      RECT 1609.090 324.205 1609.300 324.275 ;
    END
  END w0_wd_in[158]
  PIN w0_wd_in[159]
    DIRECTION INPUT ;
    USE SIGNAL ;
    SHAPE ABUTMENT ;
    PORT
      LAYER metal3 ;
      RECT 1609.090 334.985 1609.300 335.055 ;
    END
  END w0_wd_in[159]
  PIN w0_wd_in[160]
    DIRECTION INPUT ;
    USE SIGNAL ;
    SHAPE ABUTMENT ;
    PORT
      LAYER metal3 ;
      RECT 1609.090 345.765 1609.300 345.835 ;
    END
  END w0_wd_in[160]
  PIN w0_wd_in[161]
    DIRECTION INPUT ;
    USE SIGNAL ;
    SHAPE ABUTMENT ;
    PORT
      LAYER metal3 ;
      RECT 1609.090 356.545 1609.300 356.615 ;
    END
  END w0_wd_in[161]
  PIN w0_wd_in[162]
    DIRECTION INPUT ;
    USE SIGNAL ;
    SHAPE ABUTMENT ;
    PORT
      LAYER metal3 ;
      RECT 1609.090 367.325 1609.300 367.395 ;
    END
  END w0_wd_in[162]
  PIN w0_wd_in[163]
    DIRECTION INPUT ;
    USE SIGNAL ;
    SHAPE ABUTMENT ;
    PORT
      LAYER metal3 ;
      RECT 1609.090 378.105 1609.300 378.175 ;
    END
  END w0_wd_in[163]
  PIN w0_wd_in[164]
    DIRECTION INPUT ;
    USE SIGNAL ;
    SHAPE ABUTMENT ;
    PORT
      LAYER metal3 ;
      RECT 1609.090 388.885 1609.300 388.955 ;
    END
  END w0_wd_in[164]
  PIN w0_wd_in[165]
    DIRECTION INPUT ;
    USE SIGNAL ;
    SHAPE ABUTMENT ;
    PORT
      LAYER metal3 ;
      RECT 1609.090 399.665 1609.300 399.735 ;
    END
  END w0_wd_in[165]
  PIN w0_wd_in[166]
    DIRECTION INPUT ;
    USE SIGNAL ;
    SHAPE ABUTMENT ;
    PORT
      LAYER metal3 ;
      RECT 1609.090 410.445 1609.300 410.515 ;
    END
  END w0_wd_in[166]
  PIN w0_wd_in[167]
    DIRECTION INPUT ;
    USE SIGNAL ;
    SHAPE ABUTMENT ;
    PORT
      LAYER metal3 ;
      RECT 1609.090 421.225 1609.300 421.295 ;
    END
  END w0_wd_in[167]
  PIN w0_wd_in[168]
    DIRECTION INPUT ;
    USE SIGNAL ;
    SHAPE ABUTMENT ;
    PORT
      LAYER metal3 ;
      RECT 1609.090 432.005 1609.300 432.075 ;
    END
  END w0_wd_in[168]
  PIN w0_wd_in[169]
    DIRECTION INPUT ;
    USE SIGNAL ;
    SHAPE ABUTMENT ;
    PORT
      LAYER metal3 ;
      RECT 1609.090 442.785 1609.300 442.855 ;
    END
  END w0_wd_in[169]
  PIN w0_wd_in[170]
    DIRECTION INPUT ;
    USE SIGNAL ;
    SHAPE ABUTMENT ;
    PORT
      LAYER metal3 ;
      RECT 1609.090 453.565 1609.300 453.635 ;
    END
  END w0_wd_in[170]
  PIN w0_wd_in[171]
    DIRECTION INPUT ;
    USE SIGNAL ;
    SHAPE ABUTMENT ;
    PORT
      LAYER metal3 ;
      RECT 1609.090 464.345 1609.300 464.415 ;
    END
  END w0_wd_in[171]
  PIN w0_wd_in[172]
    DIRECTION INPUT ;
    USE SIGNAL ;
    SHAPE ABUTMENT ;
    PORT
      LAYER metal3 ;
      RECT 1609.090 475.125 1609.300 475.195 ;
    END
  END w0_wd_in[172]
  PIN w0_wd_in[173]
    DIRECTION INPUT ;
    USE SIGNAL ;
    SHAPE ABUTMENT ;
    PORT
      LAYER metal3 ;
      RECT 1609.090 485.905 1609.300 485.975 ;
    END
  END w0_wd_in[173]
  PIN w0_wd_in[174]
    DIRECTION INPUT ;
    USE SIGNAL ;
    SHAPE ABUTMENT ;
    PORT
      LAYER metal3 ;
      RECT 1609.090 496.685 1609.300 496.755 ;
    END
  END w0_wd_in[174]
  PIN w0_wd_in[175]
    DIRECTION INPUT ;
    USE SIGNAL ;
    SHAPE ABUTMENT ;
    PORT
      LAYER metal3 ;
      RECT 1609.090 507.465 1609.300 507.535 ;
    END
  END w0_wd_in[175]
  PIN w0_wd_in[176]
    DIRECTION INPUT ;
    USE SIGNAL ;
    SHAPE ABUTMENT ;
    PORT
      LAYER metal3 ;
      RECT 1609.090 518.245 1609.300 518.315 ;
    END
  END w0_wd_in[176]
  PIN w0_wd_in[177]
    DIRECTION INPUT ;
    USE SIGNAL ;
    SHAPE ABUTMENT ;
    PORT
      LAYER metal3 ;
      RECT 1609.090 529.025 1609.300 529.095 ;
    END
  END w0_wd_in[177]
  PIN w0_wd_in[178]
    DIRECTION INPUT ;
    USE SIGNAL ;
    SHAPE ABUTMENT ;
    PORT
      LAYER metal3 ;
      RECT 1609.090 539.805 1609.300 539.875 ;
    END
  END w0_wd_in[178]
  PIN w0_wd_in[179]
    DIRECTION INPUT ;
    USE SIGNAL ;
    SHAPE ABUTMENT ;
    PORT
      LAYER metal3 ;
      RECT 1609.090 550.585 1609.300 550.655 ;
    END
  END w0_wd_in[179]
  PIN w0_wd_in[180]
    DIRECTION INPUT ;
    USE SIGNAL ;
    SHAPE ABUTMENT ;
    PORT
      LAYER metal3 ;
      RECT 1609.090 561.365 1609.300 561.435 ;
    END
  END w0_wd_in[180]
  PIN w0_wd_in[181]
    DIRECTION INPUT ;
    USE SIGNAL ;
    SHAPE ABUTMENT ;
    PORT
      LAYER metal3 ;
      RECT 1609.090 572.145 1609.300 572.215 ;
    END
  END w0_wd_in[181]
  PIN w0_wd_in[182]
    DIRECTION INPUT ;
    USE SIGNAL ;
    SHAPE ABUTMENT ;
    PORT
      LAYER metal3 ;
      RECT 1609.090 582.925 1609.300 582.995 ;
    END
  END w0_wd_in[182]
  PIN w0_wd_in[183]
    DIRECTION INPUT ;
    USE SIGNAL ;
    SHAPE ABUTMENT ;
    PORT
      LAYER metal3 ;
      RECT 1609.090 593.705 1609.300 593.775 ;
    END
  END w0_wd_in[183]
  PIN w0_wd_in[184]
    DIRECTION INPUT ;
    USE SIGNAL ;
    SHAPE ABUTMENT ;
    PORT
      LAYER metal3 ;
      RECT 1609.090 604.485 1609.300 604.555 ;
    END
  END w0_wd_in[184]
  PIN w0_wd_in[185]
    DIRECTION INPUT ;
    USE SIGNAL ;
    SHAPE ABUTMENT ;
    PORT
      LAYER metal3 ;
      RECT 1609.090 615.265 1609.300 615.335 ;
    END
  END w0_wd_in[185]
  PIN w0_wd_in[186]
    DIRECTION INPUT ;
    USE SIGNAL ;
    SHAPE ABUTMENT ;
    PORT
      LAYER metal3 ;
      RECT 1609.090 626.045 1609.300 626.115 ;
    END
  END w0_wd_in[186]
  PIN w0_wd_in[187]
    DIRECTION INPUT ;
    USE SIGNAL ;
    SHAPE ABUTMENT ;
    PORT
      LAYER metal3 ;
      RECT 1609.090 636.825 1609.300 636.895 ;
    END
  END w0_wd_in[187]
  PIN w0_wd_in[188]
    DIRECTION INPUT ;
    USE SIGNAL ;
    SHAPE ABUTMENT ;
    PORT
      LAYER metal3 ;
      RECT 1609.090 647.605 1609.300 647.675 ;
    END
  END w0_wd_in[188]
  PIN w0_wd_in[189]
    DIRECTION INPUT ;
    USE SIGNAL ;
    SHAPE ABUTMENT ;
    PORT
      LAYER metal3 ;
      RECT 1609.090 658.385 1609.300 658.455 ;
    END
  END w0_wd_in[189]
  PIN w0_wd_in[190]
    DIRECTION INPUT ;
    USE SIGNAL ;
    SHAPE ABUTMENT ;
    PORT
      LAYER metal3 ;
      RECT 1609.090 669.165 1609.300 669.235 ;
    END
  END w0_wd_in[190]
  PIN w0_wd_in[191]
    DIRECTION INPUT ;
    USE SIGNAL ;
    SHAPE ABUTMENT ;
    PORT
      LAYER metal3 ;
      RECT 1609.090 679.945 1609.300 680.015 ;
    END
  END w0_wd_in[191]
  PIN w0_wd_in[192]
    DIRECTION INPUT ;
    USE SIGNAL ;
    SHAPE ABUTMENT ;
    PORT
      LAYER metal3 ;
      RECT 1609.090 690.725 1609.300 690.795 ;
    END
  END w0_wd_in[192]
  PIN w0_wd_in[193]
    DIRECTION INPUT ;
    USE SIGNAL ;
    SHAPE ABUTMENT ;
    PORT
      LAYER metal3 ;
      RECT 1609.090 701.505 1609.300 701.575 ;
    END
  END w0_wd_in[193]
  PIN w0_wd_in[194]
    DIRECTION INPUT ;
    USE SIGNAL ;
    SHAPE ABUTMENT ;
    PORT
      LAYER metal3 ;
      RECT 1609.090 712.285 1609.300 712.355 ;
    END
  END w0_wd_in[194]
  PIN w0_wd_in[195]
    DIRECTION INPUT ;
    USE SIGNAL ;
    SHAPE ABUTMENT ;
    PORT
      LAYER metal3 ;
      RECT 1609.090 723.065 1609.300 723.135 ;
    END
  END w0_wd_in[195]
  PIN w0_wd_in[196]
    DIRECTION INPUT ;
    USE SIGNAL ;
    SHAPE ABUTMENT ;
    PORT
      LAYER metal3 ;
      RECT 1609.090 733.845 1609.300 733.915 ;
    END
  END w0_wd_in[196]
  PIN w0_wd_in[197]
    DIRECTION INPUT ;
    USE SIGNAL ;
    SHAPE ABUTMENT ;
    PORT
      LAYER metal3 ;
      RECT 1609.090 744.625 1609.300 744.695 ;
    END
  END w0_wd_in[197]
  PIN w0_wd_in[198]
    DIRECTION INPUT ;
    USE SIGNAL ;
    SHAPE ABUTMENT ;
    PORT
      LAYER metal3 ;
      RECT 1609.090 755.405 1609.300 755.475 ;
    END
  END w0_wd_in[198]
  PIN w0_wd_in[199]
    DIRECTION INPUT ;
    USE SIGNAL ;
    SHAPE ABUTMENT ;
    PORT
      LAYER metal3 ;
      RECT 1609.090 766.185 1609.300 766.255 ;
    END
  END w0_wd_in[199]
  PIN w0_wd_in[200]
    DIRECTION INPUT ;
    USE SIGNAL ;
    SHAPE ABUTMENT ;
    PORT
      LAYER metal3 ;
      RECT 1609.090 776.965 1609.300 777.035 ;
    END
  END w0_wd_in[200]
  PIN w0_wd_in[201]
    DIRECTION INPUT ;
    USE SIGNAL ;
    SHAPE ABUTMENT ;
    PORT
      LAYER metal3 ;
      RECT 1609.090 787.745 1609.300 787.815 ;
    END
  END w0_wd_in[201]
  PIN w0_wd_in[202]
    DIRECTION INPUT ;
    USE SIGNAL ;
    SHAPE ABUTMENT ;
    PORT
      LAYER metal3 ;
      RECT 1609.090 798.525 1609.300 798.595 ;
    END
  END w0_wd_in[202]
  PIN w0_wd_in[203]
    DIRECTION INPUT ;
    USE SIGNAL ;
    SHAPE ABUTMENT ;
    PORT
      LAYER metal3 ;
      RECT 1609.090 809.305 1609.300 809.375 ;
    END
  END w0_wd_in[203]
  PIN w0_wd_in[204]
    DIRECTION INPUT ;
    USE SIGNAL ;
    SHAPE ABUTMENT ;
    PORT
      LAYER metal3 ;
      RECT 1609.090 820.085 1609.300 820.155 ;
    END
  END w0_wd_in[204]
  PIN w0_wd_in[205]
    DIRECTION INPUT ;
    USE SIGNAL ;
    SHAPE ABUTMENT ;
    PORT
      LAYER metal3 ;
      RECT 1609.090 830.865 1609.300 830.935 ;
    END
  END w0_wd_in[205]
  PIN w0_wd_in[206]
    DIRECTION INPUT ;
    USE SIGNAL ;
    SHAPE ABUTMENT ;
    PORT
      LAYER metal3 ;
      RECT 1609.090 841.645 1609.300 841.715 ;
    END
  END w0_wd_in[206]
  PIN w0_wd_in[207]
    DIRECTION INPUT ;
    USE SIGNAL ;
    SHAPE ABUTMENT ;
    PORT
      LAYER metal3 ;
      RECT 1609.090 852.425 1609.300 852.495 ;
    END
  END w0_wd_in[207]
  PIN w0_wd_in[208]
    DIRECTION INPUT ;
    USE SIGNAL ;
    SHAPE ABUTMENT ;
    PORT
      LAYER metal3 ;
      RECT 1609.090 863.205 1609.300 863.275 ;
    END
  END w0_wd_in[208]
  PIN w0_wd_in[209]
    DIRECTION INPUT ;
    USE SIGNAL ;
    SHAPE ABUTMENT ;
    PORT
      LAYER metal3 ;
      RECT 1609.090 873.985 1609.300 874.055 ;
    END
  END w0_wd_in[209]
  PIN w0_wd_in[210]
    DIRECTION INPUT ;
    USE SIGNAL ;
    SHAPE ABUTMENT ;
    PORT
      LAYER metal3 ;
      RECT 1609.090 884.765 1609.300 884.835 ;
    END
  END w0_wd_in[210]
  PIN w0_wd_in[211]
    DIRECTION INPUT ;
    USE SIGNAL ;
    SHAPE ABUTMENT ;
    PORT
      LAYER metal3 ;
      RECT 1609.090 895.545 1609.300 895.615 ;
    END
  END w0_wd_in[211]
  PIN w0_wd_in[212]
    DIRECTION INPUT ;
    USE SIGNAL ;
    SHAPE ABUTMENT ;
    PORT
      LAYER metal3 ;
      RECT 1609.090 906.325 1609.300 906.395 ;
    END
  END w0_wd_in[212]
  PIN w0_wd_in[213]
    DIRECTION INPUT ;
    USE SIGNAL ;
    SHAPE ABUTMENT ;
    PORT
      LAYER metal3 ;
      RECT 1609.090 917.105 1609.300 917.175 ;
    END
  END w0_wd_in[213]
  PIN w0_wd_in[214]
    DIRECTION INPUT ;
    USE SIGNAL ;
    SHAPE ABUTMENT ;
    PORT
      LAYER metal3 ;
      RECT 1609.090 927.885 1609.300 927.955 ;
    END
  END w0_wd_in[214]
  PIN w0_wd_in[215]
    DIRECTION INPUT ;
    USE SIGNAL ;
    SHAPE ABUTMENT ;
    PORT
      LAYER metal3 ;
      RECT 1609.090 938.665 1609.300 938.735 ;
    END
  END w0_wd_in[215]
  PIN w0_wd_in[216]
    DIRECTION INPUT ;
    USE SIGNAL ;
    SHAPE ABUTMENT ;
    PORT
      LAYER metal3 ;
      RECT 1609.090 949.445 1609.300 949.515 ;
    END
  END w0_wd_in[216]
  PIN w0_wd_in[217]
    DIRECTION INPUT ;
    USE SIGNAL ;
    SHAPE ABUTMENT ;
    PORT
      LAYER metal3 ;
      RECT 1609.090 960.225 1609.300 960.295 ;
    END
  END w0_wd_in[217]
  PIN w0_wd_in[218]
    DIRECTION INPUT ;
    USE SIGNAL ;
    SHAPE ABUTMENT ;
    PORT
      LAYER metal3 ;
      RECT 1609.090 971.005 1609.300 971.075 ;
    END
  END w0_wd_in[218]
  PIN w0_wd_in[219]
    DIRECTION INPUT ;
    USE SIGNAL ;
    SHAPE ABUTMENT ;
    PORT
      LAYER metal3 ;
      RECT 1609.090 981.785 1609.300 981.855 ;
    END
  END w0_wd_in[219]
  PIN w0_wd_in[220]
    DIRECTION INPUT ;
    USE SIGNAL ;
    SHAPE ABUTMENT ;
    PORT
      LAYER metal3 ;
      RECT 1609.090 992.565 1609.300 992.635 ;
    END
  END w0_wd_in[220]
  PIN w0_wd_in[221]
    DIRECTION INPUT ;
    USE SIGNAL ;
    SHAPE ABUTMENT ;
    PORT
      LAYER metal3 ;
      RECT 1609.090 1003.345 1609.300 1003.415 ;
    END
  END w0_wd_in[221]
  PIN w0_wd_in[222]
    DIRECTION INPUT ;
    USE SIGNAL ;
    SHAPE ABUTMENT ;
    PORT
      LAYER metal3 ;
      RECT 1609.090 1014.125 1609.300 1014.195 ;
    END
  END w0_wd_in[222]
  PIN w0_wd_in[223]
    DIRECTION INPUT ;
    USE SIGNAL ;
    SHAPE ABUTMENT ;
    PORT
      LAYER metal3 ;
      RECT 1609.090 1024.905 1609.300 1024.975 ;
    END
  END w0_wd_in[223]
  PIN w0_wd_in[224]
    DIRECTION INPUT ;
    USE SIGNAL ;
    SHAPE ABUTMENT ;
    PORT
      LAYER metal3 ;
      RECT 1609.090 1035.685 1609.300 1035.755 ;
    END
  END w0_wd_in[224]
  PIN w0_wd_in[225]
    DIRECTION INPUT ;
    USE SIGNAL ;
    SHAPE ABUTMENT ;
    PORT
      LAYER metal3 ;
      RECT 1609.090 1046.465 1609.300 1046.535 ;
    END
  END w0_wd_in[225]
  PIN w0_wd_in[226]
    DIRECTION INPUT ;
    USE SIGNAL ;
    SHAPE ABUTMENT ;
    PORT
      LAYER metal3 ;
      RECT 1609.090 1057.245 1609.300 1057.315 ;
    END
  END w0_wd_in[226]
  PIN w0_wd_in[227]
    DIRECTION INPUT ;
    USE SIGNAL ;
    SHAPE ABUTMENT ;
    PORT
      LAYER metal3 ;
      RECT 1609.090 1068.025 1609.300 1068.095 ;
    END
  END w0_wd_in[227]
  PIN w0_wd_in[228]
    DIRECTION INPUT ;
    USE SIGNAL ;
    SHAPE ABUTMENT ;
    PORT
      LAYER metal3 ;
      RECT 1609.090 1078.805 1609.300 1078.875 ;
    END
  END w0_wd_in[228]
  PIN w0_wd_in[229]
    DIRECTION INPUT ;
    USE SIGNAL ;
    SHAPE ABUTMENT ;
    PORT
      LAYER metal3 ;
      RECT 1609.090 1089.585 1609.300 1089.655 ;
    END
  END w0_wd_in[229]
  PIN w0_wd_in[230]
    DIRECTION INPUT ;
    USE SIGNAL ;
    SHAPE ABUTMENT ;
    PORT
      LAYER metal3 ;
      RECT 1609.090 1100.365 1609.300 1100.435 ;
    END
  END w0_wd_in[230]
  PIN w0_wd_in[231]
    DIRECTION INPUT ;
    USE SIGNAL ;
    SHAPE ABUTMENT ;
    PORT
      LAYER metal3 ;
      RECT 1609.090 1111.145 1609.300 1111.215 ;
    END
  END w0_wd_in[231]
  PIN w0_wd_in[232]
    DIRECTION INPUT ;
    USE SIGNAL ;
    SHAPE ABUTMENT ;
    PORT
      LAYER metal3 ;
      RECT 1609.090 1121.925 1609.300 1121.995 ;
    END
  END w0_wd_in[232]
  PIN w0_wd_in[233]
    DIRECTION INPUT ;
    USE SIGNAL ;
    SHAPE ABUTMENT ;
    PORT
      LAYER metal3 ;
      RECT 1609.090 1132.705 1609.300 1132.775 ;
    END
  END w0_wd_in[233]
  PIN w0_wd_in[234]
    DIRECTION INPUT ;
    USE SIGNAL ;
    SHAPE ABUTMENT ;
    PORT
      LAYER metal3 ;
      RECT 1609.090 1143.485 1609.300 1143.555 ;
    END
  END w0_wd_in[234]
  PIN w0_wd_in[235]
    DIRECTION INPUT ;
    USE SIGNAL ;
    SHAPE ABUTMENT ;
    PORT
      LAYER metal3 ;
      RECT 1609.090 1154.265 1609.300 1154.335 ;
    END
  END w0_wd_in[235]
  PIN w0_wd_in[236]
    DIRECTION INPUT ;
    USE SIGNAL ;
    SHAPE ABUTMENT ;
    PORT
      LAYER metal3 ;
      RECT 1609.090 1165.045 1609.300 1165.115 ;
    END
  END w0_wd_in[236]
  PIN w0_wd_in[237]
    DIRECTION INPUT ;
    USE SIGNAL ;
    SHAPE ABUTMENT ;
    PORT
      LAYER metal3 ;
      RECT 1609.090 1175.825 1609.300 1175.895 ;
    END
  END w0_wd_in[237]
  PIN w0_wd_in[238]
    DIRECTION INPUT ;
    USE SIGNAL ;
    SHAPE ABUTMENT ;
    PORT
      LAYER metal3 ;
      RECT 1609.090 1186.605 1609.300 1186.675 ;
    END
  END w0_wd_in[238]
  PIN w0_wd_in[239]
    DIRECTION INPUT ;
    USE SIGNAL ;
    SHAPE ABUTMENT ;
    PORT
      LAYER metal3 ;
      RECT 1609.090 1197.385 1609.300 1197.455 ;
    END
  END w0_wd_in[239]
  PIN w0_wd_in[240]
    DIRECTION INPUT ;
    USE SIGNAL ;
    SHAPE ABUTMENT ;
    PORT
      LAYER metal3 ;
      RECT 1609.090 1208.165 1609.300 1208.235 ;
    END
  END w0_wd_in[240]
  PIN w0_wd_in[241]
    DIRECTION INPUT ;
    USE SIGNAL ;
    SHAPE ABUTMENT ;
    PORT
      LAYER metal3 ;
      RECT 1609.090 1218.945 1609.300 1219.015 ;
    END
  END w0_wd_in[241]
  PIN w0_wd_in[242]
    DIRECTION INPUT ;
    USE SIGNAL ;
    SHAPE ABUTMENT ;
    PORT
      LAYER metal3 ;
      RECT 1609.090 1229.725 1609.300 1229.795 ;
    END
  END w0_wd_in[242]
  PIN w0_wd_in[243]
    DIRECTION INPUT ;
    USE SIGNAL ;
    SHAPE ABUTMENT ;
    PORT
      LAYER metal3 ;
      RECT 1609.090 1240.505 1609.300 1240.575 ;
    END
  END w0_wd_in[243]
  PIN w0_wd_in[244]
    DIRECTION INPUT ;
    USE SIGNAL ;
    SHAPE ABUTMENT ;
    PORT
      LAYER metal3 ;
      RECT 1609.090 1251.285 1609.300 1251.355 ;
    END
  END w0_wd_in[244]
  PIN w0_wd_in[245]
    DIRECTION INPUT ;
    USE SIGNAL ;
    SHAPE ABUTMENT ;
    PORT
      LAYER metal3 ;
      RECT 1609.090 1262.065 1609.300 1262.135 ;
    END
  END w0_wd_in[245]
  PIN w0_wd_in[246]
    DIRECTION INPUT ;
    USE SIGNAL ;
    SHAPE ABUTMENT ;
    PORT
      LAYER metal3 ;
      RECT 1609.090 1272.845 1609.300 1272.915 ;
    END
  END w0_wd_in[246]
  PIN w0_wd_in[247]
    DIRECTION INPUT ;
    USE SIGNAL ;
    SHAPE ABUTMENT ;
    PORT
      LAYER metal3 ;
      RECT 1609.090 1283.625 1609.300 1283.695 ;
    END
  END w0_wd_in[247]
  PIN w0_wd_in[248]
    DIRECTION INPUT ;
    USE SIGNAL ;
    SHAPE ABUTMENT ;
    PORT
      LAYER metal3 ;
      RECT 1609.090 1294.405 1609.300 1294.475 ;
    END
  END w0_wd_in[248]
  PIN w0_wd_in[249]
    DIRECTION INPUT ;
    USE SIGNAL ;
    SHAPE ABUTMENT ;
    PORT
      LAYER metal3 ;
      RECT 1609.090 1305.185 1609.300 1305.255 ;
    END
  END w0_wd_in[249]
  PIN w0_wd_in[250]
    DIRECTION INPUT ;
    USE SIGNAL ;
    SHAPE ABUTMENT ;
    PORT
      LAYER metal3 ;
      RECT 1609.090 1315.965 1609.300 1316.035 ;
    END
  END w0_wd_in[250]
  PIN w0_wd_in[251]
    DIRECTION INPUT ;
    USE SIGNAL ;
    SHAPE ABUTMENT ;
    PORT
      LAYER metal3 ;
      RECT 1609.090 1326.745 1609.300 1326.815 ;
    END
  END w0_wd_in[251]
  PIN w0_wd_in[252]
    DIRECTION INPUT ;
    USE SIGNAL ;
    SHAPE ABUTMENT ;
    PORT
      LAYER metal3 ;
      RECT 1609.090 1337.525 1609.300 1337.595 ;
    END
  END w0_wd_in[252]
  PIN w0_wd_in[253]
    DIRECTION INPUT ;
    USE SIGNAL ;
    SHAPE ABUTMENT ;
    PORT
      LAYER metal3 ;
      RECT 1609.090 1348.305 1609.300 1348.375 ;
    END
  END w0_wd_in[253]
  PIN w0_wd_in[254]
    DIRECTION INPUT ;
    USE SIGNAL ;
    SHAPE ABUTMENT ;
    PORT
      LAYER metal3 ;
      RECT 1609.090 1359.085 1609.300 1359.155 ;
    END
  END w0_wd_in[254]
  PIN w0_wd_in[255]
    DIRECTION INPUT ;
    USE SIGNAL ;
    SHAPE ABUTMENT ;
    PORT
      LAYER metal3 ;
      RECT 1609.090 1369.865 1609.300 1369.935 ;
    END
  END w0_wd_in[255]
  PIN w0_wd_in[256]
    DIRECTION INPUT ;
    USE SIGNAL ;
    SHAPE ABUTMENT ;
    PORT
      LAYER metal2 ;
      RECT 1.105 0.000 1.175 0.210 ;
    END
  END w0_wd_in[256]
  PIN w0_wd_in[257]
    DIRECTION INPUT ;
    USE SIGNAL ;
    SHAPE ABUTMENT ;
    PORT
      LAYER metal2 ;
      RECT 4.145 0.000 4.215 0.210 ;
    END
  END w0_wd_in[257]
  PIN w0_wd_in[258]
    DIRECTION INPUT ;
    USE SIGNAL ;
    SHAPE ABUTMENT ;
    PORT
      LAYER metal2 ;
      RECT 7.185 0.000 7.255 0.210 ;
    END
  END w0_wd_in[258]
  PIN w0_wd_in[259]
    DIRECTION INPUT ;
    USE SIGNAL ;
    SHAPE ABUTMENT ;
    PORT
      LAYER metal2 ;
      RECT 10.225 0.000 10.295 0.210 ;
    END
  END w0_wd_in[259]
  PIN w0_wd_in[260]
    DIRECTION INPUT ;
    USE SIGNAL ;
    SHAPE ABUTMENT ;
    PORT
      LAYER metal2 ;
      RECT 13.265 0.000 13.335 0.210 ;
    END
  END w0_wd_in[260]
  PIN w0_wd_in[261]
    DIRECTION INPUT ;
    USE SIGNAL ;
    SHAPE ABUTMENT ;
    PORT
      LAYER metal2 ;
      RECT 16.305 0.000 16.375 0.210 ;
    END
  END w0_wd_in[261]
  PIN w0_wd_in[262]
    DIRECTION INPUT ;
    USE SIGNAL ;
    SHAPE ABUTMENT ;
    PORT
      LAYER metal2 ;
      RECT 19.345 0.000 19.415 0.210 ;
    END
  END w0_wd_in[262]
  PIN w0_wd_in[263]
    DIRECTION INPUT ;
    USE SIGNAL ;
    SHAPE ABUTMENT ;
    PORT
      LAYER metal2 ;
      RECT 22.385 0.000 22.455 0.210 ;
    END
  END w0_wd_in[263]
  PIN w0_wd_in[264]
    DIRECTION INPUT ;
    USE SIGNAL ;
    SHAPE ABUTMENT ;
    PORT
      LAYER metal2 ;
      RECT 25.425 0.000 25.495 0.210 ;
    END
  END w0_wd_in[264]
  PIN w0_wd_in[265]
    DIRECTION INPUT ;
    USE SIGNAL ;
    SHAPE ABUTMENT ;
    PORT
      LAYER metal2 ;
      RECT 28.465 0.000 28.535 0.210 ;
    END
  END w0_wd_in[265]
  PIN w0_wd_in[266]
    DIRECTION INPUT ;
    USE SIGNAL ;
    SHAPE ABUTMENT ;
    PORT
      LAYER metal2 ;
      RECT 31.505 0.000 31.575 0.210 ;
    END
  END w0_wd_in[266]
  PIN w0_wd_in[267]
    DIRECTION INPUT ;
    USE SIGNAL ;
    SHAPE ABUTMENT ;
    PORT
      LAYER metal2 ;
      RECT 34.545 0.000 34.615 0.210 ;
    END
  END w0_wd_in[267]
  PIN w0_wd_in[268]
    DIRECTION INPUT ;
    USE SIGNAL ;
    SHAPE ABUTMENT ;
    PORT
      LAYER metal2 ;
      RECT 37.585 0.000 37.655 0.210 ;
    END
  END w0_wd_in[268]
  PIN w0_wd_in[269]
    DIRECTION INPUT ;
    USE SIGNAL ;
    SHAPE ABUTMENT ;
    PORT
      LAYER metal2 ;
      RECT 40.625 0.000 40.695 0.210 ;
    END
  END w0_wd_in[269]
  PIN w0_wd_in[270]
    DIRECTION INPUT ;
    USE SIGNAL ;
    SHAPE ABUTMENT ;
    PORT
      LAYER metal2 ;
      RECT 43.665 0.000 43.735 0.210 ;
    END
  END w0_wd_in[270]
  PIN w0_wd_in[271]
    DIRECTION INPUT ;
    USE SIGNAL ;
    SHAPE ABUTMENT ;
    PORT
      LAYER metal2 ;
      RECT 46.705 0.000 46.775 0.210 ;
    END
  END w0_wd_in[271]
  PIN w0_wd_in[272]
    DIRECTION INPUT ;
    USE SIGNAL ;
    SHAPE ABUTMENT ;
    PORT
      LAYER metal2 ;
      RECT 49.745 0.000 49.815 0.210 ;
    END
  END w0_wd_in[272]
  PIN w0_wd_in[273]
    DIRECTION INPUT ;
    USE SIGNAL ;
    SHAPE ABUTMENT ;
    PORT
      LAYER metal2 ;
      RECT 52.785 0.000 52.855 0.210 ;
    END
  END w0_wd_in[273]
  PIN w0_wd_in[274]
    DIRECTION INPUT ;
    USE SIGNAL ;
    SHAPE ABUTMENT ;
    PORT
      LAYER metal2 ;
      RECT 55.825 0.000 55.895 0.210 ;
    END
  END w0_wd_in[274]
  PIN w0_wd_in[275]
    DIRECTION INPUT ;
    USE SIGNAL ;
    SHAPE ABUTMENT ;
    PORT
      LAYER metal2 ;
      RECT 58.865 0.000 58.935 0.210 ;
    END
  END w0_wd_in[275]
  PIN w0_wd_in[276]
    DIRECTION INPUT ;
    USE SIGNAL ;
    SHAPE ABUTMENT ;
    PORT
      LAYER metal2 ;
      RECT 61.905 0.000 61.975 0.210 ;
    END
  END w0_wd_in[276]
  PIN w0_wd_in[277]
    DIRECTION INPUT ;
    USE SIGNAL ;
    SHAPE ABUTMENT ;
    PORT
      LAYER metal2 ;
      RECT 64.945 0.000 65.015 0.210 ;
    END
  END w0_wd_in[277]
  PIN w0_wd_in[278]
    DIRECTION INPUT ;
    USE SIGNAL ;
    SHAPE ABUTMENT ;
    PORT
      LAYER metal2 ;
      RECT 67.985 0.000 68.055 0.210 ;
    END
  END w0_wd_in[278]
  PIN w0_wd_in[279]
    DIRECTION INPUT ;
    USE SIGNAL ;
    SHAPE ABUTMENT ;
    PORT
      LAYER metal2 ;
      RECT 71.025 0.000 71.095 0.210 ;
    END
  END w0_wd_in[279]
  PIN w0_wd_in[280]
    DIRECTION INPUT ;
    USE SIGNAL ;
    SHAPE ABUTMENT ;
    PORT
      LAYER metal2 ;
      RECT 74.065 0.000 74.135 0.210 ;
    END
  END w0_wd_in[280]
  PIN w0_wd_in[281]
    DIRECTION INPUT ;
    USE SIGNAL ;
    SHAPE ABUTMENT ;
    PORT
      LAYER metal2 ;
      RECT 77.105 0.000 77.175 0.210 ;
    END
  END w0_wd_in[281]
  PIN w0_wd_in[282]
    DIRECTION INPUT ;
    USE SIGNAL ;
    SHAPE ABUTMENT ;
    PORT
      LAYER metal2 ;
      RECT 80.145 0.000 80.215 0.210 ;
    END
  END w0_wd_in[282]
  PIN w0_wd_in[283]
    DIRECTION INPUT ;
    USE SIGNAL ;
    SHAPE ABUTMENT ;
    PORT
      LAYER metal2 ;
      RECT 83.185 0.000 83.255 0.210 ;
    END
  END w0_wd_in[283]
  PIN w0_wd_in[284]
    DIRECTION INPUT ;
    USE SIGNAL ;
    SHAPE ABUTMENT ;
    PORT
      LAYER metal2 ;
      RECT 86.225 0.000 86.295 0.210 ;
    END
  END w0_wd_in[284]
  PIN w0_wd_in[285]
    DIRECTION INPUT ;
    USE SIGNAL ;
    SHAPE ABUTMENT ;
    PORT
      LAYER metal2 ;
      RECT 89.265 0.000 89.335 0.210 ;
    END
  END w0_wd_in[285]
  PIN w0_wd_in[286]
    DIRECTION INPUT ;
    USE SIGNAL ;
    SHAPE ABUTMENT ;
    PORT
      LAYER metal2 ;
      RECT 92.305 0.000 92.375 0.210 ;
    END
  END w0_wd_in[286]
  PIN w0_wd_in[287]
    DIRECTION INPUT ;
    USE SIGNAL ;
    SHAPE ABUTMENT ;
    PORT
      LAYER metal2 ;
      RECT 95.345 0.000 95.415 0.210 ;
    END
  END w0_wd_in[287]
  PIN w0_wd_in[288]
    DIRECTION INPUT ;
    USE SIGNAL ;
    SHAPE ABUTMENT ;
    PORT
      LAYER metal2 ;
      RECT 98.385 0.000 98.455 0.210 ;
    END
  END w0_wd_in[288]
  PIN w0_wd_in[289]
    DIRECTION INPUT ;
    USE SIGNAL ;
    SHAPE ABUTMENT ;
    PORT
      LAYER metal2 ;
      RECT 101.425 0.000 101.495 0.210 ;
    END
  END w0_wd_in[289]
  PIN w0_wd_in[290]
    DIRECTION INPUT ;
    USE SIGNAL ;
    SHAPE ABUTMENT ;
    PORT
      LAYER metal2 ;
      RECT 104.465 0.000 104.535 0.210 ;
    END
  END w0_wd_in[290]
  PIN w0_wd_in[291]
    DIRECTION INPUT ;
    USE SIGNAL ;
    SHAPE ABUTMENT ;
    PORT
      LAYER metal2 ;
      RECT 107.505 0.000 107.575 0.210 ;
    END
  END w0_wd_in[291]
  PIN w0_wd_in[292]
    DIRECTION INPUT ;
    USE SIGNAL ;
    SHAPE ABUTMENT ;
    PORT
      LAYER metal2 ;
      RECT 110.545 0.000 110.615 0.210 ;
    END
  END w0_wd_in[292]
  PIN w0_wd_in[293]
    DIRECTION INPUT ;
    USE SIGNAL ;
    SHAPE ABUTMENT ;
    PORT
      LAYER metal2 ;
      RECT 113.585 0.000 113.655 0.210 ;
    END
  END w0_wd_in[293]
  PIN w0_wd_in[294]
    DIRECTION INPUT ;
    USE SIGNAL ;
    SHAPE ABUTMENT ;
    PORT
      LAYER metal2 ;
      RECT 116.625 0.000 116.695 0.210 ;
    END
  END w0_wd_in[294]
  PIN w0_wd_in[295]
    DIRECTION INPUT ;
    USE SIGNAL ;
    SHAPE ABUTMENT ;
    PORT
      LAYER metal2 ;
      RECT 119.665 0.000 119.735 0.210 ;
    END
  END w0_wd_in[295]
  PIN w0_wd_in[296]
    DIRECTION INPUT ;
    USE SIGNAL ;
    SHAPE ABUTMENT ;
    PORT
      LAYER metal2 ;
      RECT 122.705 0.000 122.775 0.210 ;
    END
  END w0_wd_in[296]
  PIN w0_wd_in[297]
    DIRECTION INPUT ;
    USE SIGNAL ;
    SHAPE ABUTMENT ;
    PORT
      LAYER metal2 ;
      RECT 125.745 0.000 125.815 0.210 ;
    END
  END w0_wd_in[297]
  PIN w0_wd_in[298]
    DIRECTION INPUT ;
    USE SIGNAL ;
    SHAPE ABUTMENT ;
    PORT
      LAYER metal2 ;
      RECT 128.785 0.000 128.855 0.210 ;
    END
  END w0_wd_in[298]
  PIN w0_wd_in[299]
    DIRECTION INPUT ;
    USE SIGNAL ;
    SHAPE ABUTMENT ;
    PORT
      LAYER metal2 ;
      RECT 131.825 0.000 131.895 0.210 ;
    END
  END w0_wd_in[299]
  PIN w0_wd_in[300]
    DIRECTION INPUT ;
    USE SIGNAL ;
    SHAPE ABUTMENT ;
    PORT
      LAYER metal2 ;
      RECT 134.865 0.000 134.935 0.210 ;
    END
  END w0_wd_in[300]
  PIN w0_wd_in[301]
    DIRECTION INPUT ;
    USE SIGNAL ;
    SHAPE ABUTMENT ;
    PORT
      LAYER metal2 ;
      RECT 137.905 0.000 137.975 0.210 ;
    END
  END w0_wd_in[301]
  PIN w0_wd_in[302]
    DIRECTION INPUT ;
    USE SIGNAL ;
    SHAPE ABUTMENT ;
    PORT
      LAYER metal2 ;
      RECT 140.945 0.000 141.015 0.210 ;
    END
  END w0_wd_in[302]
  PIN w0_wd_in[303]
    DIRECTION INPUT ;
    USE SIGNAL ;
    SHAPE ABUTMENT ;
    PORT
      LAYER metal2 ;
      RECT 143.985 0.000 144.055 0.210 ;
    END
  END w0_wd_in[303]
  PIN w0_wd_in[304]
    DIRECTION INPUT ;
    USE SIGNAL ;
    SHAPE ABUTMENT ;
    PORT
      LAYER metal2 ;
      RECT 147.025 0.000 147.095 0.210 ;
    END
  END w0_wd_in[304]
  PIN w0_wd_in[305]
    DIRECTION INPUT ;
    USE SIGNAL ;
    SHAPE ABUTMENT ;
    PORT
      LAYER metal2 ;
      RECT 150.065 0.000 150.135 0.210 ;
    END
  END w0_wd_in[305]
  PIN w0_wd_in[306]
    DIRECTION INPUT ;
    USE SIGNAL ;
    SHAPE ABUTMENT ;
    PORT
      LAYER metal2 ;
      RECT 153.105 0.000 153.175 0.210 ;
    END
  END w0_wd_in[306]
  PIN w0_wd_in[307]
    DIRECTION INPUT ;
    USE SIGNAL ;
    SHAPE ABUTMENT ;
    PORT
      LAYER metal2 ;
      RECT 156.145 0.000 156.215 0.210 ;
    END
  END w0_wd_in[307]
  PIN w0_wd_in[308]
    DIRECTION INPUT ;
    USE SIGNAL ;
    SHAPE ABUTMENT ;
    PORT
      LAYER metal2 ;
      RECT 159.185 0.000 159.255 0.210 ;
    END
  END w0_wd_in[308]
  PIN w0_wd_in[309]
    DIRECTION INPUT ;
    USE SIGNAL ;
    SHAPE ABUTMENT ;
    PORT
      LAYER metal2 ;
      RECT 162.225 0.000 162.295 0.210 ;
    END
  END w0_wd_in[309]
  PIN w0_wd_in[310]
    DIRECTION INPUT ;
    USE SIGNAL ;
    SHAPE ABUTMENT ;
    PORT
      LAYER metal2 ;
      RECT 165.265 0.000 165.335 0.210 ;
    END
  END w0_wd_in[310]
  PIN w0_wd_in[311]
    DIRECTION INPUT ;
    USE SIGNAL ;
    SHAPE ABUTMENT ;
    PORT
      LAYER metal2 ;
      RECT 168.305 0.000 168.375 0.210 ;
    END
  END w0_wd_in[311]
  PIN w0_wd_in[312]
    DIRECTION INPUT ;
    USE SIGNAL ;
    SHAPE ABUTMENT ;
    PORT
      LAYER metal2 ;
      RECT 171.345 0.000 171.415 0.210 ;
    END
  END w0_wd_in[312]
  PIN w0_wd_in[313]
    DIRECTION INPUT ;
    USE SIGNAL ;
    SHAPE ABUTMENT ;
    PORT
      LAYER metal2 ;
      RECT 174.385 0.000 174.455 0.210 ;
    END
  END w0_wd_in[313]
  PIN w0_wd_in[314]
    DIRECTION INPUT ;
    USE SIGNAL ;
    SHAPE ABUTMENT ;
    PORT
      LAYER metal2 ;
      RECT 177.425 0.000 177.495 0.210 ;
    END
  END w0_wd_in[314]
  PIN w0_wd_in[315]
    DIRECTION INPUT ;
    USE SIGNAL ;
    SHAPE ABUTMENT ;
    PORT
      LAYER metal2 ;
      RECT 180.465 0.000 180.535 0.210 ;
    END
  END w0_wd_in[315]
  PIN w0_wd_in[316]
    DIRECTION INPUT ;
    USE SIGNAL ;
    SHAPE ABUTMENT ;
    PORT
      LAYER metal2 ;
      RECT 183.505 0.000 183.575 0.210 ;
    END
  END w0_wd_in[316]
  PIN w0_wd_in[317]
    DIRECTION INPUT ;
    USE SIGNAL ;
    SHAPE ABUTMENT ;
    PORT
      LAYER metal2 ;
      RECT 186.545 0.000 186.615 0.210 ;
    END
  END w0_wd_in[317]
  PIN w0_wd_in[318]
    DIRECTION INPUT ;
    USE SIGNAL ;
    SHAPE ABUTMENT ;
    PORT
      LAYER metal2 ;
      RECT 189.585 0.000 189.655 0.210 ;
    END
  END w0_wd_in[318]
  PIN w0_wd_in[319]
    DIRECTION INPUT ;
    USE SIGNAL ;
    SHAPE ABUTMENT ;
    PORT
      LAYER metal2 ;
      RECT 192.625 0.000 192.695 0.210 ;
    END
  END w0_wd_in[319]
  PIN w0_wd_in[320]
    DIRECTION INPUT ;
    USE SIGNAL ;
    SHAPE ABUTMENT ;
    PORT
      LAYER metal2 ;
      RECT 195.665 0.000 195.735 0.210 ;
    END
  END w0_wd_in[320]
  PIN w0_wd_in[321]
    DIRECTION INPUT ;
    USE SIGNAL ;
    SHAPE ABUTMENT ;
    PORT
      LAYER metal2 ;
      RECT 198.705 0.000 198.775 0.210 ;
    END
  END w0_wd_in[321]
  PIN w0_wd_in[322]
    DIRECTION INPUT ;
    USE SIGNAL ;
    SHAPE ABUTMENT ;
    PORT
      LAYER metal2 ;
      RECT 201.745 0.000 201.815 0.210 ;
    END
  END w0_wd_in[322]
  PIN w0_wd_in[323]
    DIRECTION INPUT ;
    USE SIGNAL ;
    SHAPE ABUTMENT ;
    PORT
      LAYER metal2 ;
      RECT 204.785 0.000 204.855 0.210 ;
    END
  END w0_wd_in[323]
  PIN w0_wd_in[324]
    DIRECTION INPUT ;
    USE SIGNAL ;
    SHAPE ABUTMENT ;
    PORT
      LAYER metal2 ;
      RECT 207.825 0.000 207.895 0.210 ;
    END
  END w0_wd_in[324]
  PIN w0_wd_in[325]
    DIRECTION INPUT ;
    USE SIGNAL ;
    SHAPE ABUTMENT ;
    PORT
      LAYER metal2 ;
      RECT 210.865 0.000 210.935 0.210 ;
    END
  END w0_wd_in[325]
  PIN w0_wd_in[326]
    DIRECTION INPUT ;
    USE SIGNAL ;
    SHAPE ABUTMENT ;
    PORT
      LAYER metal2 ;
      RECT 213.905 0.000 213.975 0.210 ;
    END
  END w0_wd_in[326]
  PIN w0_wd_in[327]
    DIRECTION INPUT ;
    USE SIGNAL ;
    SHAPE ABUTMENT ;
    PORT
      LAYER metal2 ;
      RECT 216.945 0.000 217.015 0.210 ;
    END
  END w0_wd_in[327]
  PIN w0_wd_in[328]
    DIRECTION INPUT ;
    USE SIGNAL ;
    SHAPE ABUTMENT ;
    PORT
      LAYER metal2 ;
      RECT 219.985 0.000 220.055 0.210 ;
    END
  END w0_wd_in[328]
  PIN w0_wd_in[329]
    DIRECTION INPUT ;
    USE SIGNAL ;
    SHAPE ABUTMENT ;
    PORT
      LAYER metal2 ;
      RECT 223.025 0.000 223.095 0.210 ;
    END
  END w0_wd_in[329]
  PIN w0_wd_in[330]
    DIRECTION INPUT ;
    USE SIGNAL ;
    SHAPE ABUTMENT ;
    PORT
      LAYER metal2 ;
      RECT 226.065 0.000 226.135 0.210 ;
    END
  END w0_wd_in[330]
  PIN w0_wd_in[331]
    DIRECTION INPUT ;
    USE SIGNAL ;
    SHAPE ABUTMENT ;
    PORT
      LAYER metal2 ;
      RECT 229.105 0.000 229.175 0.210 ;
    END
  END w0_wd_in[331]
  PIN w0_wd_in[332]
    DIRECTION INPUT ;
    USE SIGNAL ;
    SHAPE ABUTMENT ;
    PORT
      LAYER metal2 ;
      RECT 232.145 0.000 232.215 0.210 ;
    END
  END w0_wd_in[332]
  PIN w0_wd_in[333]
    DIRECTION INPUT ;
    USE SIGNAL ;
    SHAPE ABUTMENT ;
    PORT
      LAYER metal2 ;
      RECT 235.185 0.000 235.255 0.210 ;
    END
  END w0_wd_in[333]
  PIN w0_wd_in[334]
    DIRECTION INPUT ;
    USE SIGNAL ;
    SHAPE ABUTMENT ;
    PORT
      LAYER metal2 ;
      RECT 238.225 0.000 238.295 0.210 ;
    END
  END w0_wd_in[334]
  PIN w0_wd_in[335]
    DIRECTION INPUT ;
    USE SIGNAL ;
    SHAPE ABUTMENT ;
    PORT
      LAYER metal2 ;
      RECT 241.265 0.000 241.335 0.210 ;
    END
  END w0_wd_in[335]
  PIN w0_wd_in[336]
    DIRECTION INPUT ;
    USE SIGNAL ;
    SHAPE ABUTMENT ;
    PORT
      LAYER metal2 ;
      RECT 244.305 0.000 244.375 0.210 ;
    END
  END w0_wd_in[336]
  PIN w0_wd_in[337]
    DIRECTION INPUT ;
    USE SIGNAL ;
    SHAPE ABUTMENT ;
    PORT
      LAYER metal2 ;
      RECT 247.345 0.000 247.415 0.210 ;
    END
  END w0_wd_in[337]
  PIN w0_wd_in[338]
    DIRECTION INPUT ;
    USE SIGNAL ;
    SHAPE ABUTMENT ;
    PORT
      LAYER metal2 ;
      RECT 250.385 0.000 250.455 0.210 ;
    END
  END w0_wd_in[338]
  PIN w0_wd_in[339]
    DIRECTION INPUT ;
    USE SIGNAL ;
    SHAPE ABUTMENT ;
    PORT
      LAYER metal2 ;
      RECT 253.425 0.000 253.495 0.210 ;
    END
  END w0_wd_in[339]
  PIN w0_wd_in[340]
    DIRECTION INPUT ;
    USE SIGNAL ;
    SHAPE ABUTMENT ;
    PORT
      LAYER metal2 ;
      RECT 256.465 0.000 256.535 0.210 ;
    END
  END w0_wd_in[340]
  PIN w0_wd_in[341]
    DIRECTION INPUT ;
    USE SIGNAL ;
    SHAPE ABUTMENT ;
    PORT
      LAYER metal2 ;
      RECT 259.505 0.000 259.575 0.210 ;
    END
  END w0_wd_in[341]
  PIN w0_wd_in[342]
    DIRECTION INPUT ;
    USE SIGNAL ;
    SHAPE ABUTMENT ;
    PORT
      LAYER metal2 ;
      RECT 262.545 0.000 262.615 0.210 ;
    END
  END w0_wd_in[342]
  PIN w0_wd_in[343]
    DIRECTION INPUT ;
    USE SIGNAL ;
    SHAPE ABUTMENT ;
    PORT
      LAYER metal2 ;
      RECT 265.585 0.000 265.655 0.210 ;
    END
  END w0_wd_in[343]
  PIN w0_wd_in[344]
    DIRECTION INPUT ;
    USE SIGNAL ;
    SHAPE ABUTMENT ;
    PORT
      LAYER metal2 ;
      RECT 268.625 0.000 268.695 0.210 ;
    END
  END w0_wd_in[344]
  PIN w0_wd_in[345]
    DIRECTION INPUT ;
    USE SIGNAL ;
    SHAPE ABUTMENT ;
    PORT
      LAYER metal2 ;
      RECT 271.665 0.000 271.735 0.210 ;
    END
  END w0_wd_in[345]
  PIN w0_wd_in[346]
    DIRECTION INPUT ;
    USE SIGNAL ;
    SHAPE ABUTMENT ;
    PORT
      LAYER metal2 ;
      RECT 274.705 0.000 274.775 0.210 ;
    END
  END w0_wd_in[346]
  PIN w0_wd_in[347]
    DIRECTION INPUT ;
    USE SIGNAL ;
    SHAPE ABUTMENT ;
    PORT
      LAYER metal2 ;
      RECT 277.745 0.000 277.815 0.210 ;
    END
  END w0_wd_in[347]
  PIN w0_wd_in[348]
    DIRECTION INPUT ;
    USE SIGNAL ;
    SHAPE ABUTMENT ;
    PORT
      LAYER metal2 ;
      RECT 280.785 0.000 280.855 0.210 ;
    END
  END w0_wd_in[348]
  PIN w0_wd_in[349]
    DIRECTION INPUT ;
    USE SIGNAL ;
    SHAPE ABUTMENT ;
    PORT
      LAYER metal2 ;
      RECT 283.825 0.000 283.895 0.210 ;
    END
  END w0_wd_in[349]
  PIN w0_wd_in[350]
    DIRECTION INPUT ;
    USE SIGNAL ;
    SHAPE ABUTMENT ;
    PORT
      LAYER metal2 ;
      RECT 286.865 0.000 286.935 0.210 ;
    END
  END w0_wd_in[350]
  PIN w0_wd_in[351]
    DIRECTION INPUT ;
    USE SIGNAL ;
    SHAPE ABUTMENT ;
    PORT
      LAYER metal2 ;
      RECT 289.905 0.000 289.975 0.210 ;
    END
  END w0_wd_in[351]
  PIN w0_wd_in[352]
    DIRECTION INPUT ;
    USE SIGNAL ;
    SHAPE ABUTMENT ;
    PORT
      LAYER metal2 ;
      RECT 292.945 0.000 293.015 0.210 ;
    END
  END w0_wd_in[352]
  PIN w0_wd_in[353]
    DIRECTION INPUT ;
    USE SIGNAL ;
    SHAPE ABUTMENT ;
    PORT
      LAYER metal2 ;
      RECT 295.985 0.000 296.055 0.210 ;
    END
  END w0_wd_in[353]
  PIN w0_wd_in[354]
    DIRECTION INPUT ;
    USE SIGNAL ;
    SHAPE ABUTMENT ;
    PORT
      LAYER metal2 ;
      RECT 299.025 0.000 299.095 0.210 ;
    END
  END w0_wd_in[354]
  PIN w0_wd_in[355]
    DIRECTION INPUT ;
    USE SIGNAL ;
    SHAPE ABUTMENT ;
    PORT
      LAYER metal2 ;
      RECT 302.065 0.000 302.135 0.210 ;
    END
  END w0_wd_in[355]
  PIN w0_wd_in[356]
    DIRECTION INPUT ;
    USE SIGNAL ;
    SHAPE ABUTMENT ;
    PORT
      LAYER metal2 ;
      RECT 305.105 0.000 305.175 0.210 ;
    END
  END w0_wd_in[356]
  PIN w0_wd_in[357]
    DIRECTION INPUT ;
    USE SIGNAL ;
    SHAPE ABUTMENT ;
    PORT
      LAYER metal2 ;
      RECT 308.145 0.000 308.215 0.210 ;
    END
  END w0_wd_in[357]
  PIN w0_wd_in[358]
    DIRECTION INPUT ;
    USE SIGNAL ;
    SHAPE ABUTMENT ;
    PORT
      LAYER metal2 ;
      RECT 311.185 0.000 311.255 0.210 ;
    END
  END w0_wd_in[358]
  PIN w0_wd_in[359]
    DIRECTION INPUT ;
    USE SIGNAL ;
    SHAPE ABUTMENT ;
    PORT
      LAYER metal2 ;
      RECT 314.225 0.000 314.295 0.210 ;
    END
  END w0_wd_in[359]
  PIN w0_wd_in[360]
    DIRECTION INPUT ;
    USE SIGNAL ;
    SHAPE ABUTMENT ;
    PORT
      LAYER metal2 ;
      RECT 317.265 0.000 317.335 0.210 ;
    END
  END w0_wd_in[360]
  PIN w0_wd_in[361]
    DIRECTION INPUT ;
    USE SIGNAL ;
    SHAPE ABUTMENT ;
    PORT
      LAYER metal2 ;
      RECT 320.305 0.000 320.375 0.210 ;
    END
  END w0_wd_in[361]
  PIN w0_wd_in[362]
    DIRECTION INPUT ;
    USE SIGNAL ;
    SHAPE ABUTMENT ;
    PORT
      LAYER metal2 ;
      RECT 323.345 0.000 323.415 0.210 ;
    END
  END w0_wd_in[362]
  PIN w0_wd_in[363]
    DIRECTION INPUT ;
    USE SIGNAL ;
    SHAPE ABUTMENT ;
    PORT
      LAYER metal2 ;
      RECT 326.385 0.000 326.455 0.210 ;
    END
  END w0_wd_in[363]
  PIN w0_wd_in[364]
    DIRECTION INPUT ;
    USE SIGNAL ;
    SHAPE ABUTMENT ;
    PORT
      LAYER metal2 ;
      RECT 329.425 0.000 329.495 0.210 ;
    END
  END w0_wd_in[364]
  PIN w0_wd_in[365]
    DIRECTION INPUT ;
    USE SIGNAL ;
    SHAPE ABUTMENT ;
    PORT
      LAYER metal2 ;
      RECT 332.465 0.000 332.535 0.210 ;
    END
  END w0_wd_in[365]
  PIN w0_wd_in[366]
    DIRECTION INPUT ;
    USE SIGNAL ;
    SHAPE ABUTMENT ;
    PORT
      LAYER metal2 ;
      RECT 335.505 0.000 335.575 0.210 ;
    END
  END w0_wd_in[366]
  PIN w0_wd_in[367]
    DIRECTION INPUT ;
    USE SIGNAL ;
    SHAPE ABUTMENT ;
    PORT
      LAYER metal2 ;
      RECT 338.545 0.000 338.615 0.210 ;
    END
  END w0_wd_in[367]
  PIN w0_wd_in[368]
    DIRECTION INPUT ;
    USE SIGNAL ;
    SHAPE ABUTMENT ;
    PORT
      LAYER metal2 ;
      RECT 341.585 0.000 341.655 0.210 ;
    END
  END w0_wd_in[368]
  PIN w0_wd_in[369]
    DIRECTION INPUT ;
    USE SIGNAL ;
    SHAPE ABUTMENT ;
    PORT
      LAYER metal2 ;
      RECT 344.625 0.000 344.695 0.210 ;
    END
  END w0_wd_in[369]
  PIN w0_wd_in[370]
    DIRECTION INPUT ;
    USE SIGNAL ;
    SHAPE ABUTMENT ;
    PORT
      LAYER metal2 ;
      RECT 347.665 0.000 347.735 0.210 ;
    END
  END w0_wd_in[370]
  PIN w0_wd_in[371]
    DIRECTION INPUT ;
    USE SIGNAL ;
    SHAPE ABUTMENT ;
    PORT
      LAYER metal2 ;
      RECT 350.705 0.000 350.775 0.210 ;
    END
  END w0_wd_in[371]
  PIN w0_wd_in[372]
    DIRECTION INPUT ;
    USE SIGNAL ;
    SHAPE ABUTMENT ;
    PORT
      LAYER metal2 ;
      RECT 353.745 0.000 353.815 0.210 ;
    END
  END w0_wd_in[372]
  PIN w0_wd_in[373]
    DIRECTION INPUT ;
    USE SIGNAL ;
    SHAPE ABUTMENT ;
    PORT
      LAYER metal2 ;
      RECT 356.785 0.000 356.855 0.210 ;
    END
  END w0_wd_in[373]
  PIN w0_wd_in[374]
    DIRECTION INPUT ;
    USE SIGNAL ;
    SHAPE ABUTMENT ;
    PORT
      LAYER metal2 ;
      RECT 359.825 0.000 359.895 0.210 ;
    END
  END w0_wd_in[374]
  PIN w0_wd_in[375]
    DIRECTION INPUT ;
    USE SIGNAL ;
    SHAPE ABUTMENT ;
    PORT
      LAYER metal2 ;
      RECT 362.865 0.000 362.935 0.210 ;
    END
  END w0_wd_in[375]
  PIN w0_wd_in[376]
    DIRECTION INPUT ;
    USE SIGNAL ;
    SHAPE ABUTMENT ;
    PORT
      LAYER metal2 ;
      RECT 365.905 0.000 365.975 0.210 ;
    END
  END w0_wd_in[376]
  PIN w0_wd_in[377]
    DIRECTION INPUT ;
    USE SIGNAL ;
    SHAPE ABUTMENT ;
    PORT
      LAYER metal2 ;
      RECT 368.945 0.000 369.015 0.210 ;
    END
  END w0_wd_in[377]
  PIN w0_wd_in[378]
    DIRECTION INPUT ;
    USE SIGNAL ;
    SHAPE ABUTMENT ;
    PORT
      LAYER metal2 ;
      RECT 371.985 0.000 372.055 0.210 ;
    END
  END w0_wd_in[378]
  PIN w0_wd_in[379]
    DIRECTION INPUT ;
    USE SIGNAL ;
    SHAPE ABUTMENT ;
    PORT
      LAYER metal2 ;
      RECT 375.025 0.000 375.095 0.210 ;
    END
  END w0_wd_in[379]
  PIN w0_wd_in[380]
    DIRECTION INPUT ;
    USE SIGNAL ;
    SHAPE ABUTMENT ;
    PORT
      LAYER metal2 ;
      RECT 378.065 0.000 378.135 0.210 ;
    END
  END w0_wd_in[380]
  PIN w0_wd_in[381]
    DIRECTION INPUT ;
    USE SIGNAL ;
    SHAPE ABUTMENT ;
    PORT
      LAYER metal2 ;
      RECT 381.105 0.000 381.175 0.210 ;
    END
  END w0_wd_in[381]
  PIN w0_wd_in[382]
    DIRECTION INPUT ;
    USE SIGNAL ;
    SHAPE ABUTMENT ;
    PORT
      LAYER metal2 ;
      RECT 384.145 0.000 384.215 0.210 ;
    END
  END w0_wd_in[382]
  PIN w0_wd_in[383]
    DIRECTION INPUT ;
    USE SIGNAL ;
    SHAPE ABUTMENT ;
    PORT
      LAYER metal2 ;
      RECT 387.185 0.000 387.255 0.210 ;
    END
  END w0_wd_in[383]
  PIN w0_wd_in[384]
    DIRECTION INPUT ;
    USE SIGNAL ;
    SHAPE ABUTMENT ;
    PORT
      LAYER metal2 ;
      RECT 390.225 0.000 390.295 0.210 ;
    END
  END w0_wd_in[384]
  PIN w0_wd_in[385]
    DIRECTION INPUT ;
    USE SIGNAL ;
    SHAPE ABUTMENT ;
    PORT
      LAYER metal2 ;
      RECT 393.265 0.000 393.335 0.210 ;
    END
  END w0_wd_in[385]
  PIN w0_wd_in[386]
    DIRECTION INPUT ;
    USE SIGNAL ;
    SHAPE ABUTMENT ;
    PORT
      LAYER metal2 ;
      RECT 396.305 0.000 396.375 0.210 ;
    END
  END w0_wd_in[386]
  PIN w0_wd_in[387]
    DIRECTION INPUT ;
    USE SIGNAL ;
    SHAPE ABUTMENT ;
    PORT
      LAYER metal2 ;
      RECT 399.345 0.000 399.415 0.210 ;
    END
  END w0_wd_in[387]
  PIN w0_wd_in[388]
    DIRECTION INPUT ;
    USE SIGNAL ;
    SHAPE ABUTMENT ;
    PORT
      LAYER metal2 ;
      RECT 402.385 0.000 402.455 0.210 ;
    END
  END w0_wd_in[388]
  PIN w0_wd_in[389]
    DIRECTION INPUT ;
    USE SIGNAL ;
    SHAPE ABUTMENT ;
    PORT
      LAYER metal2 ;
      RECT 405.425 0.000 405.495 0.210 ;
    END
  END w0_wd_in[389]
  PIN w0_wd_in[390]
    DIRECTION INPUT ;
    USE SIGNAL ;
    SHAPE ABUTMENT ;
    PORT
      LAYER metal2 ;
      RECT 408.465 0.000 408.535 0.210 ;
    END
  END w0_wd_in[390]
  PIN w0_wd_in[391]
    DIRECTION INPUT ;
    USE SIGNAL ;
    SHAPE ABUTMENT ;
    PORT
      LAYER metal2 ;
      RECT 411.505 0.000 411.575 0.210 ;
    END
  END w0_wd_in[391]
  PIN w0_wd_in[392]
    DIRECTION INPUT ;
    USE SIGNAL ;
    SHAPE ABUTMENT ;
    PORT
      LAYER metal2 ;
      RECT 414.545 0.000 414.615 0.210 ;
    END
  END w0_wd_in[392]
  PIN w0_wd_in[393]
    DIRECTION INPUT ;
    USE SIGNAL ;
    SHAPE ABUTMENT ;
    PORT
      LAYER metal2 ;
      RECT 417.585 0.000 417.655 0.210 ;
    END
  END w0_wd_in[393]
  PIN w0_wd_in[394]
    DIRECTION INPUT ;
    USE SIGNAL ;
    SHAPE ABUTMENT ;
    PORT
      LAYER metal2 ;
      RECT 420.625 0.000 420.695 0.210 ;
    END
  END w0_wd_in[394]
  PIN w0_wd_in[395]
    DIRECTION INPUT ;
    USE SIGNAL ;
    SHAPE ABUTMENT ;
    PORT
      LAYER metal2 ;
      RECT 423.665 0.000 423.735 0.210 ;
    END
  END w0_wd_in[395]
  PIN w0_wd_in[396]
    DIRECTION INPUT ;
    USE SIGNAL ;
    SHAPE ABUTMENT ;
    PORT
      LAYER metal2 ;
      RECT 426.705 0.000 426.775 0.210 ;
    END
  END w0_wd_in[396]
  PIN w0_wd_in[397]
    DIRECTION INPUT ;
    USE SIGNAL ;
    SHAPE ABUTMENT ;
    PORT
      LAYER metal2 ;
      RECT 429.745 0.000 429.815 0.210 ;
    END
  END w0_wd_in[397]
  PIN w0_wd_in[398]
    DIRECTION INPUT ;
    USE SIGNAL ;
    SHAPE ABUTMENT ;
    PORT
      LAYER metal2 ;
      RECT 432.785 0.000 432.855 0.210 ;
    END
  END w0_wd_in[398]
  PIN w0_wd_in[399]
    DIRECTION INPUT ;
    USE SIGNAL ;
    SHAPE ABUTMENT ;
    PORT
      LAYER metal2 ;
      RECT 435.825 0.000 435.895 0.210 ;
    END
  END w0_wd_in[399]
  PIN w0_wd_in[400]
    DIRECTION INPUT ;
    USE SIGNAL ;
    SHAPE ABUTMENT ;
    PORT
      LAYER metal2 ;
      RECT 438.865 0.000 438.935 0.210 ;
    END
  END w0_wd_in[400]
  PIN w0_wd_in[401]
    DIRECTION INPUT ;
    USE SIGNAL ;
    SHAPE ABUTMENT ;
    PORT
      LAYER metal2 ;
      RECT 441.905 0.000 441.975 0.210 ;
    END
  END w0_wd_in[401]
  PIN w0_wd_in[402]
    DIRECTION INPUT ;
    USE SIGNAL ;
    SHAPE ABUTMENT ;
    PORT
      LAYER metal2 ;
      RECT 444.945 0.000 445.015 0.210 ;
    END
  END w0_wd_in[402]
  PIN w0_wd_in[403]
    DIRECTION INPUT ;
    USE SIGNAL ;
    SHAPE ABUTMENT ;
    PORT
      LAYER metal2 ;
      RECT 447.985 0.000 448.055 0.210 ;
    END
  END w0_wd_in[403]
  PIN w0_wd_in[404]
    DIRECTION INPUT ;
    USE SIGNAL ;
    SHAPE ABUTMENT ;
    PORT
      LAYER metal2 ;
      RECT 451.025 0.000 451.095 0.210 ;
    END
  END w0_wd_in[404]
  PIN w0_wd_in[405]
    DIRECTION INPUT ;
    USE SIGNAL ;
    SHAPE ABUTMENT ;
    PORT
      LAYER metal2 ;
      RECT 454.065 0.000 454.135 0.210 ;
    END
  END w0_wd_in[405]
  PIN w0_wd_in[406]
    DIRECTION INPUT ;
    USE SIGNAL ;
    SHAPE ABUTMENT ;
    PORT
      LAYER metal2 ;
      RECT 457.105 0.000 457.175 0.210 ;
    END
  END w0_wd_in[406]
  PIN w0_wd_in[407]
    DIRECTION INPUT ;
    USE SIGNAL ;
    SHAPE ABUTMENT ;
    PORT
      LAYER metal2 ;
      RECT 460.145 0.000 460.215 0.210 ;
    END
  END w0_wd_in[407]
  PIN w0_wd_in[408]
    DIRECTION INPUT ;
    USE SIGNAL ;
    SHAPE ABUTMENT ;
    PORT
      LAYER metal2 ;
      RECT 463.185 0.000 463.255 0.210 ;
    END
  END w0_wd_in[408]
  PIN w0_wd_in[409]
    DIRECTION INPUT ;
    USE SIGNAL ;
    SHAPE ABUTMENT ;
    PORT
      LAYER metal2 ;
      RECT 466.225 0.000 466.295 0.210 ;
    END
  END w0_wd_in[409]
  PIN w0_wd_in[410]
    DIRECTION INPUT ;
    USE SIGNAL ;
    SHAPE ABUTMENT ;
    PORT
      LAYER metal2 ;
      RECT 469.265 0.000 469.335 0.210 ;
    END
  END w0_wd_in[410]
  PIN w0_wd_in[411]
    DIRECTION INPUT ;
    USE SIGNAL ;
    SHAPE ABUTMENT ;
    PORT
      LAYER metal2 ;
      RECT 472.305 0.000 472.375 0.210 ;
    END
  END w0_wd_in[411]
  PIN w0_wd_in[412]
    DIRECTION INPUT ;
    USE SIGNAL ;
    SHAPE ABUTMENT ;
    PORT
      LAYER metal2 ;
      RECT 475.345 0.000 475.415 0.210 ;
    END
  END w0_wd_in[412]
  PIN w0_wd_in[413]
    DIRECTION INPUT ;
    USE SIGNAL ;
    SHAPE ABUTMENT ;
    PORT
      LAYER metal2 ;
      RECT 478.385 0.000 478.455 0.210 ;
    END
  END w0_wd_in[413]
  PIN w0_wd_in[414]
    DIRECTION INPUT ;
    USE SIGNAL ;
    SHAPE ABUTMENT ;
    PORT
      LAYER metal2 ;
      RECT 481.425 0.000 481.495 0.210 ;
    END
  END w0_wd_in[414]
  PIN w0_wd_in[415]
    DIRECTION INPUT ;
    USE SIGNAL ;
    SHAPE ABUTMENT ;
    PORT
      LAYER metal2 ;
      RECT 484.465 0.000 484.535 0.210 ;
    END
  END w0_wd_in[415]
  PIN w0_wd_in[416]
    DIRECTION INPUT ;
    USE SIGNAL ;
    SHAPE ABUTMENT ;
    PORT
      LAYER metal2 ;
      RECT 487.505 0.000 487.575 0.210 ;
    END
  END w0_wd_in[416]
  PIN w0_wd_in[417]
    DIRECTION INPUT ;
    USE SIGNAL ;
    SHAPE ABUTMENT ;
    PORT
      LAYER metal2 ;
      RECT 490.545 0.000 490.615 0.210 ;
    END
  END w0_wd_in[417]
  PIN w0_wd_in[418]
    DIRECTION INPUT ;
    USE SIGNAL ;
    SHAPE ABUTMENT ;
    PORT
      LAYER metal2 ;
      RECT 493.585 0.000 493.655 0.210 ;
    END
  END w0_wd_in[418]
  PIN w0_wd_in[419]
    DIRECTION INPUT ;
    USE SIGNAL ;
    SHAPE ABUTMENT ;
    PORT
      LAYER metal2 ;
      RECT 496.625 0.000 496.695 0.210 ;
    END
  END w0_wd_in[419]
  PIN w0_wd_in[420]
    DIRECTION INPUT ;
    USE SIGNAL ;
    SHAPE ABUTMENT ;
    PORT
      LAYER metal2 ;
      RECT 499.665 0.000 499.735 0.210 ;
    END
  END w0_wd_in[420]
  PIN w0_wd_in[421]
    DIRECTION INPUT ;
    USE SIGNAL ;
    SHAPE ABUTMENT ;
    PORT
      LAYER metal2 ;
      RECT 502.705 0.000 502.775 0.210 ;
    END
  END w0_wd_in[421]
  PIN w0_wd_in[422]
    DIRECTION INPUT ;
    USE SIGNAL ;
    SHAPE ABUTMENT ;
    PORT
      LAYER metal2 ;
      RECT 505.745 0.000 505.815 0.210 ;
    END
  END w0_wd_in[422]
  PIN w0_wd_in[423]
    DIRECTION INPUT ;
    USE SIGNAL ;
    SHAPE ABUTMENT ;
    PORT
      LAYER metal2 ;
      RECT 508.785 0.000 508.855 0.210 ;
    END
  END w0_wd_in[423]
  PIN w0_wd_in[424]
    DIRECTION INPUT ;
    USE SIGNAL ;
    SHAPE ABUTMENT ;
    PORT
      LAYER metal2 ;
      RECT 511.825 0.000 511.895 0.210 ;
    END
  END w0_wd_in[424]
  PIN w0_wd_in[425]
    DIRECTION INPUT ;
    USE SIGNAL ;
    SHAPE ABUTMENT ;
    PORT
      LAYER metal2 ;
      RECT 514.865 0.000 514.935 0.210 ;
    END
  END w0_wd_in[425]
  PIN w0_wd_in[426]
    DIRECTION INPUT ;
    USE SIGNAL ;
    SHAPE ABUTMENT ;
    PORT
      LAYER metal2 ;
      RECT 517.905 0.000 517.975 0.210 ;
    END
  END w0_wd_in[426]
  PIN w0_wd_in[427]
    DIRECTION INPUT ;
    USE SIGNAL ;
    SHAPE ABUTMENT ;
    PORT
      LAYER metal2 ;
      RECT 520.945 0.000 521.015 0.210 ;
    END
  END w0_wd_in[427]
  PIN w0_wd_in[428]
    DIRECTION INPUT ;
    USE SIGNAL ;
    SHAPE ABUTMENT ;
    PORT
      LAYER metal2 ;
      RECT 523.985 0.000 524.055 0.210 ;
    END
  END w0_wd_in[428]
  PIN w0_wd_in[429]
    DIRECTION INPUT ;
    USE SIGNAL ;
    SHAPE ABUTMENT ;
    PORT
      LAYER metal2 ;
      RECT 527.025 0.000 527.095 0.210 ;
    END
  END w0_wd_in[429]
  PIN w0_wd_in[430]
    DIRECTION INPUT ;
    USE SIGNAL ;
    SHAPE ABUTMENT ;
    PORT
      LAYER metal2 ;
      RECT 530.065 0.000 530.135 0.210 ;
    END
  END w0_wd_in[430]
  PIN w0_wd_in[431]
    DIRECTION INPUT ;
    USE SIGNAL ;
    SHAPE ABUTMENT ;
    PORT
      LAYER metal2 ;
      RECT 533.105 0.000 533.175 0.210 ;
    END
  END w0_wd_in[431]
  PIN w0_wd_in[432]
    DIRECTION INPUT ;
    USE SIGNAL ;
    SHAPE ABUTMENT ;
    PORT
      LAYER metal2 ;
      RECT 536.145 0.000 536.215 0.210 ;
    END
  END w0_wd_in[432]
  PIN w0_wd_in[433]
    DIRECTION INPUT ;
    USE SIGNAL ;
    SHAPE ABUTMENT ;
    PORT
      LAYER metal2 ;
      RECT 539.185 0.000 539.255 0.210 ;
    END
  END w0_wd_in[433]
  PIN w0_wd_in[434]
    DIRECTION INPUT ;
    USE SIGNAL ;
    SHAPE ABUTMENT ;
    PORT
      LAYER metal2 ;
      RECT 542.225 0.000 542.295 0.210 ;
    END
  END w0_wd_in[434]
  PIN w0_wd_in[435]
    DIRECTION INPUT ;
    USE SIGNAL ;
    SHAPE ABUTMENT ;
    PORT
      LAYER metal2 ;
      RECT 545.265 0.000 545.335 0.210 ;
    END
  END w0_wd_in[435]
  PIN w0_wd_in[436]
    DIRECTION INPUT ;
    USE SIGNAL ;
    SHAPE ABUTMENT ;
    PORT
      LAYER metal2 ;
      RECT 548.305 0.000 548.375 0.210 ;
    END
  END w0_wd_in[436]
  PIN w0_wd_in[437]
    DIRECTION INPUT ;
    USE SIGNAL ;
    SHAPE ABUTMENT ;
    PORT
      LAYER metal2 ;
      RECT 551.345 0.000 551.415 0.210 ;
    END
  END w0_wd_in[437]
  PIN w0_wd_in[438]
    DIRECTION INPUT ;
    USE SIGNAL ;
    SHAPE ABUTMENT ;
    PORT
      LAYER metal2 ;
      RECT 554.385 0.000 554.455 0.210 ;
    END
  END w0_wd_in[438]
  PIN w0_wd_in[439]
    DIRECTION INPUT ;
    USE SIGNAL ;
    SHAPE ABUTMENT ;
    PORT
      LAYER metal2 ;
      RECT 557.425 0.000 557.495 0.210 ;
    END
  END w0_wd_in[439]
  PIN w0_wd_in[440]
    DIRECTION INPUT ;
    USE SIGNAL ;
    SHAPE ABUTMENT ;
    PORT
      LAYER metal2 ;
      RECT 560.465 0.000 560.535 0.210 ;
    END
  END w0_wd_in[440]
  PIN w0_wd_in[441]
    DIRECTION INPUT ;
    USE SIGNAL ;
    SHAPE ABUTMENT ;
    PORT
      LAYER metal2 ;
      RECT 563.505 0.000 563.575 0.210 ;
    END
  END w0_wd_in[441]
  PIN w0_wd_in[442]
    DIRECTION INPUT ;
    USE SIGNAL ;
    SHAPE ABUTMENT ;
    PORT
      LAYER metal2 ;
      RECT 566.545 0.000 566.615 0.210 ;
    END
  END w0_wd_in[442]
  PIN w0_wd_in[443]
    DIRECTION INPUT ;
    USE SIGNAL ;
    SHAPE ABUTMENT ;
    PORT
      LAYER metal2 ;
      RECT 569.585 0.000 569.655 0.210 ;
    END
  END w0_wd_in[443]
  PIN w0_wd_in[444]
    DIRECTION INPUT ;
    USE SIGNAL ;
    SHAPE ABUTMENT ;
    PORT
      LAYER metal2 ;
      RECT 572.625 0.000 572.695 0.210 ;
    END
  END w0_wd_in[444]
  PIN w0_wd_in[445]
    DIRECTION INPUT ;
    USE SIGNAL ;
    SHAPE ABUTMENT ;
    PORT
      LAYER metal2 ;
      RECT 575.665 0.000 575.735 0.210 ;
    END
  END w0_wd_in[445]
  PIN w0_wd_in[446]
    DIRECTION INPUT ;
    USE SIGNAL ;
    SHAPE ABUTMENT ;
    PORT
      LAYER metal2 ;
      RECT 578.705 0.000 578.775 0.210 ;
    END
  END w0_wd_in[446]
  PIN w0_wd_in[447]
    DIRECTION INPUT ;
    USE SIGNAL ;
    SHAPE ABUTMENT ;
    PORT
      LAYER metal2 ;
      RECT 581.745 0.000 581.815 0.210 ;
    END
  END w0_wd_in[447]
  PIN w0_wd_in[448]
    DIRECTION INPUT ;
    USE SIGNAL ;
    SHAPE ABUTMENT ;
    PORT
      LAYER metal2 ;
      RECT 584.785 0.000 584.855 0.210 ;
    END
  END w0_wd_in[448]
  PIN w0_wd_in[449]
    DIRECTION INPUT ;
    USE SIGNAL ;
    SHAPE ABUTMENT ;
    PORT
      LAYER metal2 ;
      RECT 587.825 0.000 587.895 0.210 ;
    END
  END w0_wd_in[449]
  PIN w0_wd_in[450]
    DIRECTION INPUT ;
    USE SIGNAL ;
    SHAPE ABUTMENT ;
    PORT
      LAYER metal2 ;
      RECT 590.865 0.000 590.935 0.210 ;
    END
  END w0_wd_in[450]
  PIN w0_wd_in[451]
    DIRECTION INPUT ;
    USE SIGNAL ;
    SHAPE ABUTMENT ;
    PORT
      LAYER metal2 ;
      RECT 593.905 0.000 593.975 0.210 ;
    END
  END w0_wd_in[451]
  PIN w0_wd_in[452]
    DIRECTION INPUT ;
    USE SIGNAL ;
    SHAPE ABUTMENT ;
    PORT
      LAYER metal2 ;
      RECT 596.945 0.000 597.015 0.210 ;
    END
  END w0_wd_in[452]
  PIN w0_wd_in[453]
    DIRECTION INPUT ;
    USE SIGNAL ;
    SHAPE ABUTMENT ;
    PORT
      LAYER metal2 ;
      RECT 599.985 0.000 600.055 0.210 ;
    END
  END w0_wd_in[453]
  PIN w0_wd_in[454]
    DIRECTION INPUT ;
    USE SIGNAL ;
    SHAPE ABUTMENT ;
    PORT
      LAYER metal2 ;
      RECT 603.025 0.000 603.095 0.210 ;
    END
  END w0_wd_in[454]
  PIN w0_wd_in[455]
    DIRECTION INPUT ;
    USE SIGNAL ;
    SHAPE ABUTMENT ;
    PORT
      LAYER metal2 ;
      RECT 606.065 0.000 606.135 0.210 ;
    END
  END w0_wd_in[455]
  PIN w0_wd_in[456]
    DIRECTION INPUT ;
    USE SIGNAL ;
    SHAPE ABUTMENT ;
    PORT
      LAYER metal2 ;
      RECT 609.105 0.000 609.175 0.210 ;
    END
  END w0_wd_in[456]
  PIN w0_wd_in[457]
    DIRECTION INPUT ;
    USE SIGNAL ;
    SHAPE ABUTMENT ;
    PORT
      LAYER metal2 ;
      RECT 612.145 0.000 612.215 0.210 ;
    END
  END w0_wd_in[457]
  PIN w0_wd_in[458]
    DIRECTION INPUT ;
    USE SIGNAL ;
    SHAPE ABUTMENT ;
    PORT
      LAYER metal2 ;
      RECT 615.185 0.000 615.255 0.210 ;
    END
  END w0_wd_in[458]
  PIN w0_wd_in[459]
    DIRECTION INPUT ;
    USE SIGNAL ;
    SHAPE ABUTMENT ;
    PORT
      LAYER metal2 ;
      RECT 618.225 0.000 618.295 0.210 ;
    END
  END w0_wd_in[459]
  PIN w0_wd_in[460]
    DIRECTION INPUT ;
    USE SIGNAL ;
    SHAPE ABUTMENT ;
    PORT
      LAYER metal2 ;
      RECT 621.265 0.000 621.335 0.210 ;
    END
  END w0_wd_in[460]
  PIN w0_wd_in[461]
    DIRECTION INPUT ;
    USE SIGNAL ;
    SHAPE ABUTMENT ;
    PORT
      LAYER metal2 ;
      RECT 624.305 0.000 624.375 0.210 ;
    END
  END w0_wd_in[461]
  PIN w0_wd_in[462]
    DIRECTION INPUT ;
    USE SIGNAL ;
    SHAPE ABUTMENT ;
    PORT
      LAYER metal2 ;
      RECT 627.345 0.000 627.415 0.210 ;
    END
  END w0_wd_in[462]
  PIN w0_wd_in[463]
    DIRECTION INPUT ;
    USE SIGNAL ;
    SHAPE ABUTMENT ;
    PORT
      LAYER metal2 ;
      RECT 630.385 0.000 630.455 0.210 ;
    END
  END w0_wd_in[463]
  PIN w0_wd_in[464]
    DIRECTION INPUT ;
    USE SIGNAL ;
    SHAPE ABUTMENT ;
    PORT
      LAYER metal2 ;
      RECT 633.425 0.000 633.495 0.210 ;
    END
  END w0_wd_in[464]
  PIN w0_wd_in[465]
    DIRECTION INPUT ;
    USE SIGNAL ;
    SHAPE ABUTMENT ;
    PORT
      LAYER metal2 ;
      RECT 636.465 0.000 636.535 0.210 ;
    END
  END w0_wd_in[465]
  PIN w0_wd_in[466]
    DIRECTION INPUT ;
    USE SIGNAL ;
    SHAPE ABUTMENT ;
    PORT
      LAYER metal2 ;
      RECT 639.505 0.000 639.575 0.210 ;
    END
  END w0_wd_in[466]
  PIN w0_wd_in[467]
    DIRECTION INPUT ;
    USE SIGNAL ;
    SHAPE ABUTMENT ;
    PORT
      LAYER metal2 ;
      RECT 642.545 0.000 642.615 0.210 ;
    END
  END w0_wd_in[467]
  PIN w0_wd_in[468]
    DIRECTION INPUT ;
    USE SIGNAL ;
    SHAPE ABUTMENT ;
    PORT
      LAYER metal2 ;
      RECT 645.585 0.000 645.655 0.210 ;
    END
  END w0_wd_in[468]
  PIN w0_wd_in[469]
    DIRECTION INPUT ;
    USE SIGNAL ;
    SHAPE ABUTMENT ;
    PORT
      LAYER metal2 ;
      RECT 648.625 0.000 648.695 0.210 ;
    END
  END w0_wd_in[469]
  PIN w0_wd_in[470]
    DIRECTION INPUT ;
    USE SIGNAL ;
    SHAPE ABUTMENT ;
    PORT
      LAYER metal2 ;
      RECT 651.665 0.000 651.735 0.210 ;
    END
  END w0_wd_in[470]
  PIN w0_wd_in[471]
    DIRECTION INPUT ;
    USE SIGNAL ;
    SHAPE ABUTMENT ;
    PORT
      LAYER metal2 ;
      RECT 654.705 0.000 654.775 0.210 ;
    END
  END w0_wd_in[471]
  PIN w0_wd_in[472]
    DIRECTION INPUT ;
    USE SIGNAL ;
    SHAPE ABUTMENT ;
    PORT
      LAYER metal2 ;
      RECT 657.745 0.000 657.815 0.210 ;
    END
  END w0_wd_in[472]
  PIN w0_wd_in[473]
    DIRECTION INPUT ;
    USE SIGNAL ;
    SHAPE ABUTMENT ;
    PORT
      LAYER metal2 ;
      RECT 660.785 0.000 660.855 0.210 ;
    END
  END w0_wd_in[473]
  PIN w0_wd_in[474]
    DIRECTION INPUT ;
    USE SIGNAL ;
    SHAPE ABUTMENT ;
    PORT
      LAYER metal2 ;
      RECT 663.825 0.000 663.895 0.210 ;
    END
  END w0_wd_in[474]
  PIN w0_wd_in[475]
    DIRECTION INPUT ;
    USE SIGNAL ;
    SHAPE ABUTMENT ;
    PORT
      LAYER metal2 ;
      RECT 666.865 0.000 666.935 0.210 ;
    END
  END w0_wd_in[475]
  PIN w0_wd_in[476]
    DIRECTION INPUT ;
    USE SIGNAL ;
    SHAPE ABUTMENT ;
    PORT
      LAYER metal2 ;
      RECT 669.905 0.000 669.975 0.210 ;
    END
  END w0_wd_in[476]
  PIN w0_wd_in[477]
    DIRECTION INPUT ;
    USE SIGNAL ;
    SHAPE ABUTMENT ;
    PORT
      LAYER metal2 ;
      RECT 672.945 0.000 673.015 0.210 ;
    END
  END w0_wd_in[477]
  PIN w0_wd_in[478]
    DIRECTION INPUT ;
    USE SIGNAL ;
    SHAPE ABUTMENT ;
    PORT
      LAYER metal2 ;
      RECT 675.985 0.000 676.055 0.210 ;
    END
  END w0_wd_in[478]
  PIN w0_wd_in[479]
    DIRECTION INPUT ;
    USE SIGNAL ;
    SHAPE ABUTMENT ;
    PORT
      LAYER metal2 ;
      RECT 679.025 0.000 679.095 0.210 ;
    END
  END w0_wd_in[479]
  PIN w0_wd_in[480]
    DIRECTION INPUT ;
    USE SIGNAL ;
    SHAPE ABUTMENT ;
    PORT
      LAYER metal2 ;
      RECT 682.065 0.000 682.135 0.210 ;
    END
  END w0_wd_in[480]
  PIN w0_wd_in[481]
    DIRECTION INPUT ;
    USE SIGNAL ;
    SHAPE ABUTMENT ;
    PORT
      LAYER metal2 ;
      RECT 685.105 0.000 685.175 0.210 ;
    END
  END w0_wd_in[481]
  PIN w0_wd_in[482]
    DIRECTION INPUT ;
    USE SIGNAL ;
    SHAPE ABUTMENT ;
    PORT
      LAYER metal2 ;
      RECT 688.145 0.000 688.215 0.210 ;
    END
  END w0_wd_in[482]
  PIN w0_wd_in[483]
    DIRECTION INPUT ;
    USE SIGNAL ;
    SHAPE ABUTMENT ;
    PORT
      LAYER metal2 ;
      RECT 691.185 0.000 691.255 0.210 ;
    END
  END w0_wd_in[483]
  PIN w0_wd_in[484]
    DIRECTION INPUT ;
    USE SIGNAL ;
    SHAPE ABUTMENT ;
    PORT
      LAYER metal2 ;
      RECT 694.225 0.000 694.295 0.210 ;
    END
  END w0_wd_in[484]
  PIN w0_wd_in[485]
    DIRECTION INPUT ;
    USE SIGNAL ;
    SHAPE ABUTMENT ;
    PORT
      LAYER metal2 ;
      RECT 697.265 0.000 697.335 0.210 ;
    END
  END w0_wd_in[485]
  PIN w0_wd_in[486]
    DIRECTION INPUT ;
    USE SIGNAL ;
    SHAPE ABUTMENT ;
    PORT
      LAYER metal2 ;
      RECT 700.305 0.000 700.375 0.210 ;
    END
  END w0_wd_in[486]
  PIN w0_wd_in[487]
    DIRECTION INPUT ;
    USE SIGNAL ;
    SHAPE ABUTMENT ;
    PORT
      LAYER metal2 ;
      RECT 703.345 0.000 703.415 0.210 ;
    END
  END w0_wd_in[487]
  PIN w0_wd_in[488]
    DIRECTION INPUT ;
    USE SIGNAL ;
    SHAPE ABUTMENT ;
    PORT
      LAYER metal2 ;
      RECT 706.385 0.000 706.455 0.210 ;
    END
  END w0_wd_in[488]
  PIN w0_wd_in[489]
    DIRECTION INPUT ;
    USE SIGNAL ;
    SHAPE ABUTMENT ;
    PORT
      LAYER metal2 ;
      RECT 709.425 0.000 709.495 0.210 ;
    END
  END w0_wd_in[489]
  PIN w0_wd_in[490]
    DIRECTION INPUT ;
    USE SIGNAL ;
    SHAPE ABUTMENT ;
    PORT
      LAYER metal2 ;
      RECT 712.465 0.000 712.535 0.210 ;
    END
  END w0_wd_in[490]
  PIN w0_wd_in[491]
    DIRECTION INPUT ;
    USE SIGNAL ;
    SHAPE ABUTMENT ;
    PORT
      LAYER metal2 ;
      RECT 715.505 0.000 715.575 0.210 ;
    END
  END w0_wd_in[491]
  PIN w0_wd_in[492]
    DIRECTION INPUT ;
    USE SIGNAL ;
    SHAPE ABUTMENT ;
    PORT
      LAYER metal2 ;
      RECT 718.545 0.000 718.615 0.210 ;
    END
  END w0_wd_in[492]
  PIN w0_wd_in[493]
    DIRECTION INPUT ;
    USE SIGNAL ;
    SHAPE ABUTMENT ;
    PORT
      LAYER metal2 ;
      RECT 721.585 0.000 721.655 0.210 ;
    END
  END w0_wd_in[493]
  PIN w0_wd_in[494]
    DIRECTION INPUT ;
    USE SIGNAL ;
    SHAPE ABUTMENT ;
    PORT
      LAYER metal2 ;
      RECT 724.625 0.000 724.695 0.210 ;
    END
  END w0_wd_in[494]
  PIN w0_wd_in[495]
    DIRECTION INPUT ;
    USE SIGNAL ;
    SHAPE ABUTMENT ;
    PORT
      LAYER metal2 ;
      RECT 727.665 0.000 727.735 0.210 ;
    END
  END w0_wd_in[495]
  PIN w0_wd_in[496]
    DIRECTION INPUT ;
    USE SIGNAL ;
    SHAPE ABUTMENT ;
    PORT
      LAYER metal2 ;
      RECT 730.705 0.000 730.775 0.210 ;
    END
  END w0_wd_in[496]
  PIN w0_wd_in[497]
    DIRECTION INPUT ;
    USE SIGNAL ;
    SHAPE ABUTMENT ;
    PORT
      LAYER metal2 ;
      RECT 733.745 0.000 733.815 0.210 ;
    END
  END w0_wd_in[497]
  PIN w0_wd_in[498]
    DIRECTION INPUT ;
    USE SIGNAL ;
    SHAPE ABUTMENT ;
    PORT
      LAYER metal2 ;
      RECT 736.785 0.000 736.855 0.210 ;
    END
  END w0_wd_in[498]
  PIN w0_wd_in[499]
    DIRECTION INPUT ;
    USE SIGNAL ;
    SHAPE ABUTMENT ;
    PORT
      LAYER metal2 ;
      RECT 739.825 0.000 739.895 0.210 ;
    END
  END w0_wd_in[499]
  PIN w0_wd_in[500]
    DIRECTION INPUT ;
    USE SIGNAL ;
    SHAPE ABUTMENT ;
    PORT
      LAYER metal2 ;
      RECT 742.865 0.000 742.935 0.210 ;
    END
  END w0_wd_in[500]
  PIN w0_wd_in[501]
    DIRECTION INPUT ;
    USE SIGNAL ;
    SHAPE ABUTMENT ;
    PORT
      LAYER metal2 ;
      RECT 745.905 0.000 745.975 0.210 ;
    END
  END w0_wd_in[501]
  PIN w0_wd_in[502]
    DIRECTION INPUT ;
    USE SIGNAL ;
    SHAPE ABUTMENT ;
    PORT
      LAYER metal2 ;
      RECT 748.945 0.000 749.015 0.210 ;
    END
  END w0_wd_in[502]
  PIN w0_wd_in[503]
    DIRECTION INPUT ;
    USE SIGNAL ;
    SHAPE ABUTMENT ;
    PORT
      LAYER metal2 ;
      RECT 751.985 0.000 752.055 0.210 ;
    END
  END w0_wd_in[503]
  PIN w0_wd_in[504]
    DIRECTION INPUT ;
    USE SIGNAL ;
    SHAPE ABUTMENT ;
    PORT
      LAYER metal2 ;
      RECT 755.025 0.000 755.095 0.210 ;
    END
  END w0_wd_in[504]
  PIN w0_wd_in[505]
    DIRECTION INPUT ;
    USE SIGNAL ;
    SHAPE ABUTMENT ;
    PORT
      LAYER metal2 ;
      RECT 758.065 0.000 758.135 0.210 ;
    END
  END w0_wd_in[505]
  PIN w0_wd_in[506]
    DIRECTION INPUT ;
    USE SIGNAL ;
    SHAPE ABUTMENT ;
    PORT
      LAYER metal2 ;
      RECT 761.105 0.000 761.175 0.210 ;
    END
  END w0_wd_in[506]
  PIN w0_wd_in[507]
    DIRECTION INPUT ;
    USE SIGNAL ;
    SHAPE ABUTMENT ;
    PORT
      LAYER metal2 ;
      RECT 764.145 0.000 764.215 0.210 ;
    END
  END w0_wd_in[507]
  PIN w0_wd_in[508]
    DIRECTION INPUT ;
    USE SIGNAL ;
    SHAPE ABUTMENT ;
    PORT
      LAYER metal2 ;
      RECT 767.185 0.000 767.255 0.210 ;
    END
  END w0_wd_in[508]
  PIN w0_wd_in[509]
    DIRECTION INPUT ;
    USE SIGNAL ;
    SHAPE ABUTMENT ;
    PORT
      LAYER metal2 ;
      RECT 770.225 0.000 770.295 0.210 ;
    END
  END w0_wd_in[509]
  PIN w0_wd_in[510]
    DIRECTION INPUT ;
    USE SIGNAL ;
    SHAPE ABUTMENT ;
    PORT
      LAYER metal2 ;
      RECT 773.265 0.000 773.335 0.210 ;
    END
  END w0_wd_in[510]
  PIN w0_wd_in[511]
    DIRECTION INPUT ;
    USE SIGNAL ;
    SHAPE ABUTMENT ;
    PORT
      LAYER metal2 ;
      RECT 776.305 0.000 776.375 0.210 ;
    END
  END w0_wd_in[511]
  PIN r0_rd_out[0]
    DIRECTION OUTPUT ;
    USE SIGNAL ;
    SHAPE ABUTMENT ;
    PORT
      LAYER metal2 ;
      RECT 779.345 0.000 779.415 0.210 ;
    END
  END r0_rd_out[0]
  PIN r0_rd_out[1]
    DIRECTION OUTPUT ;
    USE SIGNAL ;
    SHAPE ABUTMENT ;
    PORT
      LAYER metal2 ;
      RECT 782.385 0.000 782.455 0.210 ;
    END
  END r0_rd_out[1]
  PIN r0_rd_out[2]
    DIRECTION OUTPUT ;
    USE SIGNAL ;
    SHAPE ABUTMENT ;
    PORT
      LAYER metal2 ;
      RECT 785.425 0.000 785.495 0.210 ;
    END
  END r0_rd_out[2]
  PIN r0_rd_out[3]
    DIRECTION OUTPUT ;
    USE SIGNAL ;
    SHAPE ABUTMENT ;
    PORT
      LAYER metal2 ;
      RECT 788.465 0.000 788.535 0.210 ;
    END
  END r0_rd_out[3]
  PIN r0_rd_out[4]
    DIRECTION OUTPUT ;
    USE SIGNAL ;
    SHAPE ABUTMENT ;
    PORT
      LAYER metal2 ;
      RECT 791.505 0.000 791.575 0.210 ;
    END
  END r0_rd_out[4]
  PIN r0_rd_out[5]
    DIRECTION OUTPUT ;
    USE SIGNAL ;
    SHAPE ABUTMENT ;
    PORT
      LAYER metal2 ;
      RECT 794.545 0.000 794.615 0.210 ;
    END
  END r0_rd_out[5]
  PIN r0_rd_out[6]
    DIRECTION OUTPUT ;
    USE SIGNAL ;
    SHAPE ABUTMENT ;
    PORT
      LAYER metal2 ;
      RECT 797.585 0.000 797.655 0.210 ;
    END
  END r0_rd_out[6]
  PIN r0_rd_out[7]
    DIRECTION OUTPUT ;
    USE SIGNAL ;
    SHAPE ABUTMENT ;
    PORT
      LAYER metal2 ;
      RECT 800.625 0.000 800.695 0.210 ;
    END
  END r0_rd_out[7]
  PIN r0_rd_out[8]
    DIRECTION OUTPUT ;
    USE SIGNAL ;
    SHAPE ABUTMENT ;
    PORT
      LAYER metal2 ;
      RECT 803.665 0.000 803.735 0.210 ;
    END
  END r0_rd_out[8]
  PIN r0_rd_out[9]
    DIRECTION OUTPUT ;
    USE SIGNAL ;
    SHAPE ABUTMENT ;
    PORT
      LAYER metal2 ;
      RECT 806.705 0.000 806.775 0.210 ;
    END
  END r0_rd_out[9]
  PIN r0_rd_out[10]
    DIRECTION OUTPUT ;
    USE SIGNAL ;
    SHAPE ABUTMENT ;
    PORT
      LAYER metal2 ;
      RECT 809.745 0.000 809.815 0.210 ;
    END
  END r0_rd_out[10]
  PIN r0_rd_out[11]
    DIRECTION OUTPUT ;
    USE SIGNAL ;
    SHAPE ABUTMENT ;
    PORT
      LAYER metal2 ;
      RECT 812.785 0.000 812.855 0.210 ;
    END
  END r0_rd_out[11]
  PIN r0_rd_out[12]
    DIRECTION OUTPUT ;
    USE SIGNAL ;
    SHAPE ABUTMENT ;
    PORT
      LAYER metal2 ;
      RECT 815.825 0.000 815.895 0.210 ;
    END
  END r0_rd_out[12]
  PIN r0_rd_out[13]
    DIRECTION OUTPUT ;
    USE SIGNAL ;
    SHAPE ABUTMENT ;
    PORT
      LAYER metal2 ;
      RECT 818.865 0.000 818.935 0.210 ;
    END
  END r0_rd_out[13]
  PIN r0_rd_out[14]
    DIRECTION OUTPUT ;
    USE SIGNAL ;
    SHAPE ABUTMENT ;
    PORT
      LAYER metal2 ;
      RECT 821.905 0.000 821.975 0.210 ;
    END
  END r0_rd_out[14]
  PIN r0_rd_out[15]
    DIRECTION OUTPUT ;
    USE SIGNAL ;
    SHAPE ABUTMENT ;
    PORT
      LAYER metal2 ;
      RECT 824.945 0.000 825.015 0.210 ;
    END
  END r0_rd_out[15]
  PIN r0_rd_out[16]
    DIRECTION OUTPUT ;
    USE SIGNAL ;
    SHAPE ABUTMENT ;
    PORT
      LAYER metal2 ;
      RECT 827.985 0.000 828.055 0.210 ;
    END
  END r0_rd_out[16]
  PIN r0_rd_out[17]
    DIRECTION OUTPUT ;
    USE SIGNAL ;
    SHAPE ABUTMENT ;
    PORT
      LAYER metal2 ;
      RECT 831.025 0.000 831.095 0.210 ;
    END
  END r0_rd_out[17]
  PIN r0_rd_out[18]
    DIRECTION OUTPUT ;
    USE SIGNAL ;
    SHAPE ABUTMENT ;
    PORT
      LAYER metal2 ;
      RECT 834.065 0.000 834.135 0.210 ;
    END
  END r0_rd_out[18]
  PIN r0_rd_out[19]
    DIRECTION OUTPUT ;
    USE SIGNAL ;
    SHAPE ABUTMENT ;
    PORT
      LAYER metal2 ;
      RECT 837.105 0.000 837.175 0.210 ;
    END
  END r0_rd_out[19]
  PIN r0_rd_out[20]
    DIRECTION OUTPUT ;
    USE SIGNAL ;
    SHAPE ABUTMENT ;
    PORT
      LAYER metal2 ;
      RECT 840.145 0.000 840.215 0.210 ;
    END
  END r0_rd_out[20]
  PIN r0_rd_out[21]
    DIRECTION OUTPUT ;
    USE SIGNAL ;
    SHAPE ABUTMENT ;
    PORT
      LAYER metal2 ;
      RECT 843.185 0.000 843.255 0.210 ;
    END
  END r0_rd_out[21]
  PIN r0_rd_out[22]
    DIRECTION OUTPUT ;
    USE SIGNAL ;
    SHAPE ABUTMENT ;
    PORT
      LAYER metal2 ;
      RECT 846.225 0.000 846.295 0.210 ;
    END
  END r0_rd_out[22]
  PIN r0_rd_out[23]
    DIRECTION OUTPUT ;
    USE SIGNAL ;
    SHAPE ABUTMENT ;
    PORT
      LAYER metal2 ;
      RECT 849.265 0.000 849.335 0.210 ;
    END
  END r0_rd_out[23]
  PIN r0_rd_out[24]
    DIRECTION OUTPUT ;
    USE SIGNAL ;
    SHAPE ABUTMENT ;
    PORT
      LAYER metal2 ;
      RECT 852.305 0.000 852.375 0.210 ;
    END
  END r0_rd_out[24]
  PIN r0_rd_out[25]
    DIRECTION OUTPUT ;
    USE SIGNAL ;
    SHAPE ABUTMENT ;
    PORT
      LAYER metal2 ;
      RECT 855.345 0.000 855.415 0.210 ;
    END
  END r0_rd_out[25]
  PIN r0_rd_out[26]
    DIRECTION OUTPUT ;
    USE SIGNAL ;
    SHAPE ABUTMENT ;
    PORT
      LAYER metal2 ;
      RECT 858.385 0.000 858.455 0.210 ;
    END
  END r0_rd_out[26]
  PIN r0_rd_out[27]
    DIRECTION OUTPUT ;
    USE SIGNAL ;
    SHAPE ABUTMENT ;
    PORT
      LAYER metal2 ;
      RECT 861.425 0.000 861.495 0.210 ;
    END
  END r0_rd_out[27]
  PIN r0_rd_out[28]
    DIRECTION OUTPUT ;
    USE SIGNAL ;
    SHAPE ABUTMENT ;
    PORT
      LAYER metal2 ;
      RECT 864.465 0.000 864.535 0.210 ;
    END
  END r0_rd_out[28]
  PIN r0_rd_out[29]
    DIRECTION OUTPUT ;
    USE SIGNAL ;
    SHAPE ABUTMENT ;
    PORT
      LAYER metal2 ;
      RECT 867.505 0.000 867.575 0.210 ;
    END
  END r0_rd_out[29]
  PIN r0_rd_out[30]
    DIRECTION OUTPUT ;
    USE SIGNAL ;
    SHAPE ABUTMENT ;
    PORT
      LAYER metal2 ;
      RECT 870.545 0.000 870.615 0.210 ;
    END
  END r0_rd_out[30]
  PIN r0_rd_out[31]
    DIRECTION OUTPUT ;
    USE SIGNAL ;
    SHAPE ABUTMENT ;
    PORT
      LAYER metal2 ;
      RECT 873.585 0.000 873.655 0.210 ;
    END
  END r0_rd_out[31]
  PIN r0_rd_out[32]
    DIRECTION OUTPUT ;
    USE SIGNAL ;
    SHAPE ABUTMENT ;
    PORT
      LAYER metal2 ;
      RECT 876.625 0.000 876.695 0.210 ;
    END
  END r0_rd_out[32]
  PIN r0_rd_out[33]
    DIRECTION OUTPUT ;
    USE SIGNAL ;
    SHAPE ABUTMENT ;
    PORT
      LAYER metal2 ;
      RECT 879.665 0.000 879.735 0.210 ;
    END
  END r0_rd_out[33]
  PIN r0_rd_out[34]
    DIRECTION OUTPUT ;
    USE SIGNAL ;
    SHAPE ABUTMENT ;
    PORT
      LAYER metal2 ;
      RECT 882.705 0.000 882.775 0.210 ;
    END
  END r0_rd_out[34]
  PIN r0_rd_out[35]
    DIRECTION OUTPUT ;
    USE SIGNAL ;
    SHAPE ABUTMENT ;
    PORT
      LAYER metal2 ;
      RECT 885.745 0.000 885.815 0.210 ;
    END
  END r0_rd_out[35]
  PIN r0_rd_out[36]
    DIRECTION OUTPUT ;
    USE SIGNAL ;
    SHAPE ABUTMENT ;
    PORT
      LAYER metal2 ;
      RECT 888.785 0.000 888.855 0.210 ;
    END
  END r0_rd_out[36]
  PIN r0_rd_out[37]
    DIRECTION OUTPUT ;
    USE SIGNAL ;
    SHAPE ABUTMENT ;
    PORT
      LAYER metal2 ;
      RECT 891.825 0.000 891.895 0.210 ;
    END
  END r0_rd_out[37]
  PIN r0_rd_out[38]
    DIRECTION OUTPUT ;
    USE SIGNAL ;
    SHAPE ABUTMENT ;
    PORT
      LAYER metal2 ;
      RECT 894.865 0.000 894.935 0.210 ;
    END
  END r0_rd_out[38]
  PIN r0_rd_out[39]
    DIRECTION OUTPUT ;
    USE SIGNAL ;
    SHAPE ABUTMENT ;
    PORT
      LAYER metal2 ;
      RECT 897.905 0.000 897.975 0.210 ;
    END
  END r0_rd_out[39]
  PIN r0_rd_out[40]
    DIRECTION OUTPUT ;
    USE SIGNAL ;
    SHAPE ABUTMENT ;
    PORT
      LAYER metal2 ;
      RECT 900.945 0.000 901.015 0.210 ;
    END
  END r0_rd_out[40]
  PIN r0_rd_out[41]
    DIRECTION OUTPUT ;
    USE SIGNAL ;
    SHAPE ABUTMENT ;
    PORT
      LAYER metal2 ;
      RECT 903.985 0.000 904.055 0.210 ;
    END
  END r0_rd_out[41]
  PIN r0_rd_out[42]
    DIRECTION OUTPUT ;
    USE SIGNAL ;
    SHAPE ABUTMENT ;
    PORT
      LAYER metal2 ;
      RECT 907.025 0.000 907.095 0.210 ;
    END
  END r0_rd_out[42]
  PIN r0_rd_out[43]
    DIRECTION OUTPUT ;
    USE SIGNAL ;
    SHAPE ABUTMENT ;
    PORT
      LAYER metal2 ;
      RECT 910.065 0.000 910.135 0.210 ;
    END
  END r0_rd_out[43]
  PIN r0_rd_out[44]
    DIRECTION OUTPUT ;
    USE SIGNAL ;
    SHAPE ABUTMENT ;
    PORT
      LAYER metal2 ;
      RECT 913.105 0.000 913.175 0.210 ;
    END
  END r0_rd_out[44]
  PIN r0_rd_out[45]
    DIRECTION OUTPUT ;
    USE SIGNAL ;
    SHAPE ABUTMENT ;
    PORT
      LAYER metal2 ;
      RECT 916.145 0.000 916.215 0.210 ;
    END
  END r0_rd_out[45]
  PIN r0_rd_out[46]
    DIRECTION OUTPUT ;
    USE SIGNAL ;
    SHAPE ABUTMENT ;
    PORT
      LAYER metal2 ;
      RECT 919.185 0.000 919.255 0.210 ;
    END
  END r0_rd_out[46]
  PIN r0_rd_out[47]
    DIRECTION OUTPUT ;
    USE SIGNAL ;
    SHAPE ABUTMENT ;
    PORT
      LAYER metal2 ;
      RECT 922.225 0.000 922.295 0.210 ;
    END
  END r0_rd_out[47]
  PIN r0_rd_out[48]
    DIRECTION OUTPUT ;
    USE SIGNAL ;
    SHAPE ABUTMENT ;
    PORT
      LAYER metal2 ;
      RECT 925.265 0.000 925.335 0.210 ;
    END
  END r0_rd_out[48]
  PIN r0_rd_out[49]
    DIRECTION OUTPUT ;
    USE SIGNAL ;
    SHAPE ABUTMENT ;
    PORT
      LAYER metal2 ;
      RECT 928.305 0.000 928.375 0.210 ;
    END
  END r0_rd_out[49]
  PIN r0_rd_out[50]
    DIRECTION OUTPUT ;
    USE SIGNAL ;
    SHAPE ABUTMENT ;
    PORT
      LAYER metal2 ;
      RECT 931.345 0.000 931.415 0.210 ;
    END
  END r0_rd_out[50]
  PIN r0_rd_out[51]
    DIRECTION OUTPUT ;
    USE SIGNAL ;
    SHAPE ABUTMENT ;
    PORT
      LAYER metal2 ;
      RECT 934.385 0.000 934.455 0.210 ;
    END
  END r0_rd_out[51]
  PIN r0_rd_out[52]
    DIRECTION OUTPUT ;
    USE SIGNAL ;
    SHAPE ABUTMENT ;
    PORT
      LAYER metal2 ;
      RECT 937.425 0.000 937.495 0.210 ;
    END
  END r0_rd_out[52]
  PIN r0_rd_out[53]
    DIRECTION OUTPUT ;
    USE SIGNAL ;
    SHAPE ABUTMENT ;
    PORT
      LAYER metal2 ;
      RECT 940.465 0.000 940.535 0.210 ;
    END
  END r0_rd_out[53]
  PIN r0_rd_out[54]
    DIRECTION OUTPUT ;
    USE SIGNAL ;
    SHAPE ABUTMENT ;
    PORT
      LAYER metal2 ;
      RECT 943.505 0.000 943.575 0.210 ;
    END
  END r0_rd_out[54]
  PIN r0_rd_out[55]
    DIRECTION OUTPUT ;
    USE SIGNAL ;
    SHAPE ABUTMENT ;
    PORT
      LAYER metal2 ;
      RECT 946.545 0.000 946.615 0.210 ;
    END
  END r0_rd_out[55]
  PIN r0_rd_out[56]
    DIRECTION OUTPUT ;
    USE SIGNAL ;
    SHAPE ABUTMENT ;
    PORT
      LAYER metal2 ;
      RECT 949.585 0.000 949.655 0.210 ;
    END
  END r0_rd_out[56]
  PIN r0_rd_out[57]
    DIRECTION OUTPUT ;
    USE SIGNAL ;
    SHAPE ABUTMENT ;
    PORT
      LAYER metal2 ;
      RECT 952.625 0.000 952.695 0.210 ;
    END
  END r0_rd_out[57]
  PIN r0_rd_out[58]
    DIRECTION OUTPUT ;
    USE SIGNAL ;
    SHAPE ABUTMENT ;
    PORT
      LAYER metal2 ;
      RECT 955.665 0.000 955.735 0.210 ;
    END
  END r0_rd_out[58]
  PIN r0_rd_out[59]
    DIRECTION OUTPUT ;
    USE SIGNAL ;
    SHAPE ABUTMENT ;
    PORT
      LAYER metal2 ;
      RECT 958.705 0.000 958.775 0.210 ;
    END
  END r0_rd_out[59]
  PIN r0_rd_out[60]
    DIRECTION OUTPUT ;
    USE SIGNAL ;
    SHAPE ABUTMENT ;
    PORT
      LAYER metal2 ;
      RECT 961.745 0.000 961.815 0.210 ;
    END
  END r0_rd_out[60]
  PIN r0_rd_out[61]
    DIRECTION OUTPUT ;
    USE SIGNAL ;
    SHAPE ABUTMENT ;
    PORT
      LAYER metal2 ;
      RECT 964.785 0.000 964.855 0.210 ;
    END
  END r0_rd_out[61]
  PIN r0_rd_out[62]
    DIRECTION OUTPUT ;
    USE SIGNAL ;
    SHAPE ABUTMENT ;
    PORT
      LAYER metal2 ;
      RECT 967.825 0.000 967.895 0.210 ;
    END
  END r0_rd_out[62]
  PIN r0_rd_out[63]
    DIRECTION OUTPUT ;
    USE SIGNAL ;
    SHAPE ABUTMENT ;
    PORT
      LAYER metal2 ;
      RECT 970.865 0.000 970.935 0.210 ;
    END
  END r0_rd_out[63]
  PIN r0_rd_out[64]
    DIRECTION OUTPUT ;
    USE SIGNAL ;
    SHAPE ABUTMENT ;
    PORT
      LAYER metal2 ;
      RECT 973.905 0.000 973.975 0.210 ;
    END
  END r0_rd_out[64]
  PIN r0_rd_out[65]
    DIRECTION OUTPUT ;
    USE SIGNAL ;
    SHAPE ABUTMENT ;
    PORT
      LAYER metal2 ;
      RECT 976.945 0.000 977.015 0.210 ;
    END
  END r0_rd_out[65]
  PIN r0_rd_out[66]
    DIRECTION OUTPUT ;
    USE SIGNAL ;
    SHAPE ABUTMENT ;
    PORT
      LAYER metal2 ;
      RECT 979.985 0.000 980.055 0.210 ;
    END
  END r0_rd_out[66]
  PIN r0_rd_out[67]
    DIRECTION OUTPUT ;
    USE SIGNAL ;
    SHAPE ABUTMENT ;
    PORT
      LAYER metal2 ;
      RECT 983.025 0.000 983.095 0.210 ;
    END
  END r0_rd_out[67]
  PIN r0_rd_out[68]
    DIRECTION OUTPUT ;
    USE SIGNAL ;
    SHAPE ABUTMENT ;
    PORT
      LAYER metal2 ;
      RECT 986.065 0.000 986.135 0.210 ;
    END
  END r0_rd_out[68]
  PIN r0_rd_out[69]
    DIRECTION OUTPUT ;
    USE SIGNAL ;
    SHAPE ABUTMENT ;
    PORT
      LAYER metal2 ;
      RECT 989.105 0.000 989.175 0.210 ;
    END
  END r0_rd_out[69]
  PIN r0_rd_out[70]
    DIRECTION OUTPUT ;
    USE SIGNAL ;
    SHAPE ABUTMENT ;
    PORT
      LAYER metal2 ;
      RECT 992.145 0.000 992.215 0.210 ;
    END
  END r0_rd_out[70]
  PIN r0_rd_out[71]
    DIRECTION OUTPUT ;
    USE SIGNAL ;
    SHAPE ABUTMENT ;
    PORT
      LAYER metal2 ;
      RECT 995.185 0.000 995.255 0.210 ;
    END
  END r0_rd_out[71]
  PIN r0_rd_out[72]
    DIRECTION OUTPUT ;
    USE SIGNAL ;
    SHAPE ABUTMENT ;
    PORT
      LAYER metal2 ;
      RECT 998.225 0.000 998.295 0.210 ;
    END
  END r0_rd_out[72]
  PIN r0_rd_out[73]
    DIRECTION OUTPUT ;
    USE SIGNAL ;
    SHAPE ABUTMENT ;
    PORT
      LAYER metal2 ;
      RECT 1001.265 0.000 1001.335 0.210 ;
    END
  END r0_rd_out[73]
  PIN r0_rd_out[74]
    DIRECTION OUTPUT ;
    USE SIGNAL ;
    SHAPE ABUTMENT ;
    PORT
      LAYER metal2 ;
      RECT 1004.305 0.000 1004.375 0.210 ;
    END
  END r0_rd_out[74]
  PIN r0_rd_out[75]
    DIRECTION OUTPUT ;
    USE SIGNAL ;
    SHAPE ABUTMENT ;
    PORT
      LAYER metal2 ;
      RECT 1007.345 0.000 1007.415 0.210 ;
    END
  END r0_rd_out[75]
  PIN r0_rd_out[76]
    DIRECTION OUTPUT ;
    USE SIGNAL ;
    SHAPE ABUTMENT ;
    PORT
      LAYER metal2 ;
      RECT 1010.385 0.000 1010.455 0.210 ;
    END
  END r0_rd_out[76]
  PIN r0_rd_out[77]
    DIRECTION OUTPUT ;
    USE SIGNAL ;
    SHAPE ABUTMENT ;
    PORT
      LAYER metal2 ;
      RECT 1013.425 0.000 1013.495 0.210 ;
    END
  END r0_rd_out[77]
  PIN r0_rd_out[78]
    DIRECTION OUTPUT ;
    USE SIGNAL ;
    SHAPE ABUTMENT ;
    PORT
      LAYER metal2 ;
      RECT 1016.465 0.000 1016.535 0.210 ;
    END
  END r0_rd_out[78]
  PIN r0_rd_out[79]
    DIRECTION OUTPUT ;
    USE SIGNAL ;
    SHAPE ABUTMENT ;
    PORT
      LAYER metal2 ;
      RECT 1019.505 0.000 1019.575 0.210 ;
    END
  END r0_rd_out[79]
  PIN r0_rd_out[80]
    DIRECTION OUTPUT ;
    USE SIGNAL ;
    SHAPE ABUTMENT ;
    PORT
      LAYER metal2 ;
      RECT 1022.545 0.000 1022.615 0.210 ;
    END
  END r0_rd_out[80]
  PIN r0_rd_out[81]
    DIRECTION OUTPUT ;
    USE SIGNAL ;
    SHAPE ABUTMENT ;
    PORT
      LAYER metal2 ;
      RECT 1025.585 0.000 1025.655 0.210 ;
    END
  END r0_rd_out[81]
  PIN r0_rd_out[82]
    DIRECTION OUTPUT ;
    USE SIGNAL ;
    SHAPE ABUTMENT ;
    PORT
      LAYER metal2 ;
      RECT 1028.625 0.000 1028.695 0.210 ;
    END
  END r0_rd_out[82]
  PIN r0_rd_out[83]
    DIRECTION OUTPUT ;
    USE SIGNAL ;
    SHAPE ABUTMENT ;
    PORT
      LAYER metal2 ;
      RECT 1031.665 0.000 1031.735 0.210 ;
    END
  END r0_rd_out[83]
  PIN r0_rd_out[84]
    DIRECTION OUTPUT ;
    USE SIGNAL ;
    SHAPE ABUTMENT ;
    PORT
      LAYER metal2 ;
      RECT 1034.705 0.000 1034.775 0.210 ;
    END
  END r0_rd_out[84]
  PIN r0_rd_out[85]
    DIRECTION OUTPUT ;
    USE SIGNAL ;
    SHAPE ABUTMENT ;
    PORT
      LAYER metal2 ;
      RECT 1037.745 0.000 1037.815 0.210 ;
    END
  END r0_rd_out[85]
  PIN r0_rd_out[86]
    DIRECTION OUTPUT ;
    USE SIGNAL ;
    SHAPE ABUTMENT ;
    PORT
      LAYER metal2 ;
      RECT 1040.785 0.000 1040.855 0.210 ;
    END
  END r0_rd_out[86]
  PIN r0_rd_out[87]
    DIRECTION OUTPUT ;
    USE SIGNAL ;
    SHAPE ABUTMENT ;
    PORT
      LAYER metal2 ;
      RECT 1043.825 0.000 1043.895 0.210 ;
    END
  END r0_rd_out[87]
  PIN r0_rd_out[88]
    DIRECTION OUTPUT ;
    USE SIGNAL ;
    SHAPE ABUTMENT ;
    PORT
      LAYER metal2 ;
      RECT 1046.865 0.000 1046.935 0.210 ;
    END
  END r0_rd_out[88]
  PIN r0_rd_out[89]
    DIRECTION OUTPUT ;
    USE SIGNAL ;
    SHAPE ABUTMENT ;
    PORT
      LAYER metal2 ;
      RECT 1049.905 0.000 1049.975 0.210 ;
    END
  END r0_rd_out[89]
  PIN r0_rd_out[90]
    DIRECTION OUTPUT ;
    USE SIGNAL ;
    SHAPE ABUTMENT ;
    PORT
      LAYER metal2 ;
      RECT 1052.945 0.000 1053.015 0.210 ;
    END
  END r0_rd_out[90]
  PIN r0_rd_out[91]
    DIRECTION OUTPUT ;
    USE SIGNAL ;
    SHAPE ABUTMENT ;
    PORT
      LAYER metal2 ;
      RECT 1055.985 0.000 1056.055 0.210 ;
    END
  END r0_rd_out[91]
  PIN r0_rd_out[92]
    DIRECTION OUTPUT ;
    USE SIGNAL ;
    SHAPE ABUTMENT ;
    PORT
      LAYER metal2 ;
      RECT 1059.025 0.000 1059.095 0.210 ;
    END
  END r0_rd_out[92]
  PIN r0_rd_out[93]
    DIRECTION OUTPUT ;
    USE SIGNAL ;
    SHAPE ABUTMENT ;
    PORT
      LAYER metal2 ;
      RECT 1062.065 0.000 1062.135 0.210 ;
    END
  END r0_rd_out[93]
  PIN r0_rd_out[94]
    DIRECTION OUTPUT ;
    USE SIGNAL ;
    SHAPE ABUTMENT ;
    PORT
      LAYER metal2 ;
      RECT 1065.105 0.000 1065.175 0.210 ;
    END
  END r0_rd_out[94]
  PIN r0_rd_out[95]
    DIRECTION OUTPUT ;
    USE SIGNAL ;
    SHAPE ABUTMENT ;
    PORT
      LAYER metal2 ;
      RECT 1068.145 0.000 1068.215 0.210 ;
    END
  END r0_rd_out[95]
  PIN r0_rd_out[96]
    DIRECTION OUTPUT ;
    USE SIGNAL ;
    SHAPE ABUTMENT ;
    PORT
      LAYER metal2 ;
      RECT 1071.185 0.000 1071.255 0.210 ;
    END
  END r0_rd_out[96]
  PIN r0_rd_out[97]
    DIRECTION OUTPUT ;
    USE SIGNAL ;
    SHAPE ABUTMENT ;
    PORT
      LAYER metal2 ;
      RECT 1074.225 0.000 1074.295 0.210 ;
    END
  END r0_rd_out[97]
  PIN r0_rd_out[98]
    DIRECTION OUTPUT ;
    USE SIGNAL ;
    SHAPE ABUTMENT ;
    PORT
      LAYER metal2 ;
      RECT 1077.265 0.000 1077.335 0.210 ;
    END
  END r0_rd_out[98]
  PIN r0_rd_out[99]
    DIRECTION OUTPUT ;
    USE SIGNAL ;
    SHAPE ABUTMENT ;
    PORT
      LAYER metal2 ;
      RECT 1080.305 0.000 1080.375 0.210 ;
    END
  END r0_rd_out[99]
  PIN r0_rd_out[100]
    DIRECTION OUTPUT ;
    USE SIGNAL ;
    SHAPE ABUTMENT ;
    PORT
      LAYER metal2 ;
      RECT 1083.345 0.000 1083.415 0.210 ;
    END
  END r0_rd_out[100]
  PIN r0_rd_out[101]
    DIRECTION OUTPUT ;
    USE SIGNAL ;
    SHAPE ABUTMENT ;
    PORT
      LAYER metal2 ;
      RECT 1086.385 0.000 1086.455 0.210 ;
    END
  END r0_rd_out[101]
  PIN r0_rd_out[102]
    DIRECTION OUTPUT ;
    USE SIGNAL ;
    SHAPE ABUTMENT ;
    PORT
      LAYER metal2 ;
      RECT 1089.425 0.000 1089.495 0.210 ;
    END
  END r0_rd_out[102]
  PIN r0_rd_out[103]
    DIRECTION OUTPUT ;
    USE SIGNAL ;
    SHAPE ABUTMENT ;
    PORT
      LAYER metal2 ;
      RECT 1092.465 0.000 1092.535 0.210 ;
    END
  END r0_rd_out[103]
  PIN r0_rd_out[104]
    DIRECTION OUTPUT ;
    USE SIGNAL ;
    SHAPE ABUTMENT ;
    PORT
      LAYER metal2 ;
      RECT 1095.505 0.000 1095.575 0.210 ;
    END
  END r0_rd_out[104]
  PIN r0_rd_out[105]
    DIRECTION OUTPUT ;
    USE SIGNAL ;
    SHAPE ABUTMENT ;
    PORT
      LAYER metal2 ;
      RECT 1098.545 0.000 1098.615 0.210 ;
    END
  END r0_rd_out[105]
  PIN r0_rd_out[106]
    DIRECTION OUTPUT ;
    USE SIGNAL ;
    SHAPE ABUTMENT ;
    PORT
      LAYER metal2 ;
      RECT 1101.585 0.000 1101.655 0.210 ;
    END
  END r0_rd_out[106]
  PIN r0_rd_out[107]
    DIRECTION OUTPUT ;
    USE SIGNAL ;
    SHAPE ABUTMENT ;
    PORT
      LAYER metal2 ;
      RECT 1104.625 0.000 1104.695 0.210 ;
    END
  END r0_rd_out[107]
  PIN r0_rd_out[108]
    DIRECTION OUTPUT ;
    USE SIGNAL ;
    SHAPE ABUTMENT ;
    PORT
      LAYER metal2 ;
      RECT 1107.665 0.000 1107.735 0.210 ;
    END
  END r0_rd_out[108]
  PIN r0_rd_out[109]
    DIRECTION OUTPUT ;
    USE SIGNAL ;
    SHAPE ABUTMENT ;
    PORT
      LAYER metal2 ;
      RECT 1110.705 0.000 1110.775 0.210 ;
    END
  END r0_rd_out[109]
  PIN r0_rd_out[110]
    DIRECTION OUTPUT ;
    USE SIGNAL ;
    SHAPE ABUTMENT ;
    PORT
      LAYER metal2 ;
      RECT 1113.745 0.000 1113.815 0.210 ;
    END
  END r0_rd_out[110]
  PIN r0_rd_out[111]
    DIRECTION OUTPUT ;
    USE SIGNAL ;
    SHAPE ABUTMENT ;
    PORT
      LAYER metal2 ;
      RECT 1116.785 0.000 1116.855 0.210 ;
    END
  END r0_rd_out[111]
  PIN r0_rd_out[112]
    DIRECTION OUTPUT ;
    USE SIGNAL ;
    SHAPE ABUTMENT ;
    PORT
      LAYER metal2 ;
      RECT 1119.825 0.000 1119.895 0.210 ;
    END
  END r0_rd_out[112]
  PIN r0_rd_out[113]
    DIRECTION OUTPUT ;
    USE SIGNAL ;
    SHAPE ABUTMENT ;
    PORT
      LAYER metal2 ;
      RECT 1122.865 0.000 1122.935 0.210 ;
    END
  END r0_rd_out[113]
  PIN r0_rd_out[114]
    DIRECTION OUTPUT ;
    USE SIGNAL ;
    SHAPE ABUTMENT ;
    PORT
      LAYER metal2 ;
      RECT 1125.905 0.000 1125.975 0.210 ;
    END
  END r0_rd_out[114]
  PIN r0_rd_out[115]
    DIRECTION OUTPUT ;
    USE SIGNAL ;
    SHAPE ABUTMENT ;
    PORT
      LAYER metal2 ;
      RECT 1128.945 0.000 1129.015 0.210 ;
    END
  END r0_rd_out[115]
  PIN r0_rd_out[116]
    DIRECTION OUTPUT ;
    USE SIGNAL ;
    SHAPE ABUTMENT ;
    PORT
      LAYER metal2 ;
      RECT 1131.985 0.000 1132.055 0.210 ;
    END
  END r0_rd_out[116]
  PIN r0_rd_out[117]
    DIRECTION OUTPUT ;
    USE SIGNAL ;
    SHAPE ABUTMENT ;
    PORT
      LAYER metal2 ;
      RECT 1135.025 0.000 1135.095 0.210 ;
    END
  END r0_rd_out[117]
  PIN r0_rd_out[118]
    DIRECTION OUTPUT ;
    USE SIGNAL ;
    SHAPE ABUTMENT ;
    PORT
      LAYER metal2 ;
      RECT 1138.065 0.000 1138.135 0.210 ;
    END
  END r0_rd_out[118]
  PIN r0_rd_out[119]
    DIRECTION OUTPUT ;
    USE SIGNAL ;
    SHAPE ABUTMENT ;
    PORT
      LAYER metal2 ;
      RECT 1141.105 0.000 1141.175 0.210 ;
    END
  END r0_rd_out[119]
  PIN r0_rd_out[120]
    DIRECTION OUTPUT ;
    USE SIGNAL ;
    SHAPE ABUTMENT ;
    PORT
      LAYER metal2 ;
      RECT 1144.145 0.000 1144.215 0.210 ;
    END
  END r0_rd_out[120]
  PIN r0_rd_out[121]
    DIRECTION OUTPUT ;
    USE SIGNAL ;
    SHAPE ABUTMENT ;
    PORT
      LAYER metal2 ;
      RECT 1147.185 0.000 1147.255 0.210 ;
    END
  END r0_rd_out[121]
  PIN r0_rd_out[122]
    DIRECTION OUTPUT ;
    USE SIGNAL ;
    SHAPE ABUTMENT ;
    PORT
      LAYER metal2 ;
      RECT 1150.225 0.000 1150.295 0.210 ;
    END
  END r0_rd_out[122]
  PIN r0_rd_out[123]
    DIRECTION OUTPUT ;
    USE SIGNAL ;
    SHAPE ABUTMENT ;
    PORT
      LAYER metal2 ;
      RECT 1153.265 0.000 1153.335 0.210 ;
    END
  END r0_rd_out[123]
  PIN r0_rd_out[124]
    DIRECTION OUTPUT ;
    USE SIGNAL ;
    SHAPE ABUTMENT ;
    PORT
      LAYER metal2 ;
      RECT 1156.305 0.000 1156.375 0.210 ;
    END
  END r0_rd_out[124]
  PIN r0_rd_out[125]
    DIRECTION OUTPUT ;
    USE SIGNAL ;
    SHAPE ABUTMENT ;
    PORT
      LAYER metal2 ;
      RECT 1159.345 0.000 1159.415 0.210 ;
    END
  END r0_rd_out[125]
  PIN r0_rd_out[126]
    DIRECTION OUTPUT ;
    USE SIGNAL ;
    SHAPE ABUTMENT ;
    PORT
      LAYER metal2 ;
      RECT 1162.385 0.000 1162.455 0.210 ;
    END
  END r0_rd_out[126]
  PIN r0_rd_out[127]
    DIRECTION OUTPUT ;
    USE SIGNAL ;
    SHAPE ABUTMENT ;
    PORT
      LAYER metal2 ;
      RECT 1165.425 0.000 1165.495 0.210 ;
    END
  END r0_rd_out[127]
  PIN r0_rd_out[128]
    DIRECTION OUTPUT ;
    USE SIGNAL ;
    SHAPE ABUTMENT ;
    PORT
      LAYER metal2 ;
      RECT 1168.465 0.000 1168.535 0.210 ;
    END
  END r0_rd_out[128]
  PIN r0_rd_out[129]
    DIRECTION OUTPUT ;
    USE SIGNAL ;
    SHAPE ABUTMENT ;
    PORT
      LAYER metal2 ;
      RECT 1171.505 0.000 1171.575 0.210 ;
    END
  END r0_rd_out[129]
  PIN r0_rd_out[130]
    DIRECTION OUTPUT ;
    USE SIGNAL ;
    SHAPE ABUTMENT ;
    PORT
      LAYER metal2 ;
      RECT 1174.545 0.000 1174.615 0.210 ;
    END
  END r0_rd_out[130]
  PIN r0_rd_out[131]
    DIRECTION OUTPUT ;
    USE SIGNAL ;
    SHAPE ABUTMENT ;
    PORT
      LAYER metal2 ;
      RECT 1177.585 0.000 1177.655 0.210 ;
    END
  END r0_rd_out[131]
  PIN r0_rd_out[132]
    DIRECTION OUTPUT ;
    USE SIGNAL ;
    SHAPE ABUTMENT ;
    PORT
      LAYER metal2 ;
      RECT 1180.625 0.000 1180.695 0.210 ;
    END
  END r0_rd_out[132]
  PIN r0_rd_out[133]
    DIRECTION OUTPUT ;
    USE SIGNAL ;
    SHAPE ABUTMENT ;
    PORT
      LAYER metal2 ;
      RECT 1183.665 0.000 1183.735 0.210 ;
    END
  END r0_rd_out[133]
  PIN r0_rd_out[134]
    DIRECTION OUTPUT ;
    USE SIGNAL ;
    SHAPE ABUTMENT ;
    PORT
      LAYER metal2 ;
      RECT 1186.705 0.000 1186.775 0.210 ;
    END
  END r0_rd_out[134]
  PIN r0_rd_out[135]
    DIRECTION OUTPUT ;
    USE SIGNAL ;
    SHAPE ABUTMENT ;
    PORT
      LAYER metal2 ;
      RECT 1189.745 0.000 1189.815 0.210 ;
    END
  END r0_rd_out[135]
  PIN r0_rd_out[136]
    DIRECTION OUTPUT ;
    USE SIGNAL ;
    SHAPE ABUTMENT ;
    PORT
      LAYER metal2 ;
      RECT 1192.785 0.000 1192.855 0.210 ;
    END
  END r0_rd_out[136]
  PIN r0_rd_out[137]
    DIRECTION OUTPUT ;
    USE SIGNAL ;
    SHAPE ABUTMENT ;
    PORT
      LAYER metal2 ;
      RECT 1195.825 0.000 1195.895 0.210 ;
    END
  END r0_rd_out[137]
  PIN r0_rd_out[138]
    DIRECTION OUTPUT ;
    USE SIGNAL ;
    SHAPE ABUTMENT ;
    PORT
      LAYER metal2 ;
      RECT 1198.865 0.000 1198.935 0.210 ;
    END
  END r0_rd_out[138]
  PIN r0_rd_out[139]
    DIRECTION OUTPUT ;
    USE SIGNAL ;
    SHAPE ABUTMENT ;
    PORT
      LAYER metal2 ;
      RECT 1201.905 0.000 1201.975 0.210 ;
    END
  END r0_rd_out[139]
  PIN r0_rd_out[140]
    DIRECTION OUTPUT ;
    USE SIGNAL ;
    SHAPE ABUTMENT ;
    PORT
      LAYER metal2 ;
      RECT 1204.945 0.000 1205.015 0.210 ;
    END
  END r0_rd_out[140]
  PIN r0_rd_out[141]
    DIRECTION OUTPUT ;
    USE SIGNAL ;
    SHAPE ABUTMENT ;
    PORT
      LAYER metal2 ;
      RECT 1207.985 0.000 1208.055 0.210 ;
    END
  END r0_rd_out[141]
  PIN r0_rd_out[142]
    DIRECTION OUTPUT ;
    USE SIGNAL ;
    SHAPE ABUTMENT ;
    PORT
      LAYER metal2 ;
      RECT 1211.025 0.000 1211.095 0.210 ;
    END
  END r0_rd_out[142]
  PIN r0_rd_out[143]
    DIRECTION OUTPUT ;
    USE SIGNAL ;
    SHAPE ABUTMENT ;
    PORT
      LAYER metal2 ;
      RECT 1214.065 0.000 1214.135 0.210 ;
    END
  END r0_rd_out[143]
  PIN r0_rd_out[144]
    DIRECTION OUTPUT ;
    USE SIGNAL ;
    SHAPE ABUTMENT ;
    PORT
      LAYER metal2 ;
      RECT 1217.105 0.000 1217.175 0.210 ;
    END
  END r0_rd_out[144]
  PIN r0_rd_out[145]
    DIRECTION OUTPUT ;
    USE SIGNAL ;
    SHAPE ABUTMENT ;
    PORT
      LAYER metal2 ;
      RECT 1220.145 0.000 1220.215 0.210 ;
    END
  END r0_rd_out[145]
  PIN r0_rd_out[146]
    DIRECTION OUTPUT ;
    USE SIGNAL ;
    SHAPE ABUTMENT ;
    PORT
      LAYER metal2 ;
      RECT 1223.185 0.000 1223.255 0.210 ;
    END
  END r0_rd_out[146]
  PIN r0_rd_out[147]
    DIRECTION OUTPUT ;
    USE SIGNAL ;
    SHAPE ABUTMENT ;
    PORT
      LAYER metal2 ;
      RECT 1226.225 0.000 1226.295 0.210 ;
    END
  END r0_rd_out[147]
  PIN r0_rd_out[148]
    DIRECTION OUTPUT ;
    USE SIGNAL ;
    SHAPE ABUTMENT ;
    PORT
      LAYER metal2 ;
      RECT 1229.265 0.000 1229.335 0.210 ;
    END
  END r0_rd_out[148]
  PIN r0_rd_out[149]
    DIRECTION OUTPUT ;
    USE SIGNAL ;
    SHAPE ABUTMENT ;
    PORT
      LAYER metal2 ;
      RECT 1232.305 0.000 1232.375 0.210 ;
    END
  END r0_rd_out[149]
  PIN r0_rd_out[150]
    DIRECTION OUTPUT ;
    USE SIGNAL ;
    SHAPE ABUTMENT ;
    PORT
      LAYER metal2 ;
      RECT 1235.345 0.000 1235.415 0.210 ;
    END
  END r0_rd_out[150]
  PIN r0_rd_out[151]
    DIRECTION OUTPUT ;
    USE SIGNAL ;
    SHAPE ABUTMENT ;
    PORT
      LAYER metal2 ;
      RECT 1238.385 0.000 1238.455 0.210 ;
    END
  END r0_rd_out[151]
  PIN r0_rd_out[152]
    DIRECTION OUTPUT ;
    USE SIGNAL ;
    SHAPE ABUTMENT ;
    PORT
      LAYER metal2 ;
      RECT 1241.425 0.000 1241.495 0.210 ;
    END
  END r0_rd_out[152]
  PIN r0_rd_out[153]
    DIRECTION OUTPUT ;
    USE SIGNAL ;
    SHAPE ABUTMENT ;
    PORT
      LAYER metal2 ;
      RECT 1244.465 0.000 1244.535 0.210 ;
    END
  END r0_rd_out[153]
  PIN r0_rd_out[154]
    DIRECTION OUTPUT ;
    USE SIGNAL ;
    SHAPE ABUTMENT ;
    PORT
      LAYER metal2 ;
      RECT 1247.505 0.000 1247.575 0.210 ;
    END
  END r0_rd_out[154]
  PIN r0_rd_out[155]
    DIRECTION OUTPUT ;
    USE SIGNAL ;
    SHAPE ABUTMENT ;
    PORT
      LAYER metal2 ;
      RECT 1250.545 0.000 1250.615 0.210 ;
    END
  END r0_rd_out[155]
  PIN r0_rd_out[156]
    DIRECTION OUTPUT ;
    USE SIGNAL ;
    SHAPE ABUTMENT ;
    PORT
      LAYER metal2 ;
      RECT 1253.585 0.000 1253.655 0.210 ;
    END
  END r0_rd_out[156]
  PIN r0_rd_out[157]
    DIRECTION OUTPUT ;
    USE SIGNAL ;
    SHAPE ABUTMENT ;
    PORT
      LAYER metal2 ;
      RECT 1256.625 0.000 1256.695 0.210 ;
    END
  END r0_rd_out[157]
  PIN r0_rd_out[158]
    DIRECTION OUTPUT ;
    USE SIGNAL ;
    SHAPE ABUTMENT ;
    PORT
      LAYER metal2 ;
      RECT 1259.665 0.000 1259.735 0.210 ;
    END
  END r0_rd_out[158]
  PIN r0_rd_out[159]
    DIRECTION OUTPUT ;
    USE SIGNAL ;
    SHAPE ABUTMENT ;
    PORT
      LAYER metal2 ;
      RECT 1262.705 0.000 1262.775 0.210 ;
    END
  END r0_rd_out[159]
  PIN r0_rd_out[160]
    DIRECTION OUTPUT ;
    USE SIGNAL ;
    SHAPE ABUTMENT ;
    PORT
      LAYER metal2 ;
      RECT 1265.745 0.000 1265.815 0.210 ;
    END
  END r0_rd_out[160]
  PIN r0_rd_out[161]
    DIRECTION OUTPUT ;
    USE SIGNAL ;
    SHAPE ABUTMENT ;
    PORT
      LAYER metal2 ;
      RECT 1268.785 0.000 1268.855 0.210 ;
    END
  END r0_rd_out[161]
  PIN r0_rd_out[162]
    DIRECTION OUTPUT ;
    USE SIGNAL ;
    SHAPE ABUTMENT ;
    PORT
      LAYER metal2 ;
      RECT 1271.825 0.000 1271.895 0.210 ;
    END
  END r0_rd_out[162]
  PIN r0_rd_out[163]
    DIRECTION OUTPUT ;
    USE SIGNAL ;
    SHAPE ABUTMENT ;
    PORT
      LAYER metal2 ;
      RECT 1274.865 0.000 1274.935 0.210 ;
    END
  END r0_rd_out[163]
  PIN r0_rd_out[164]
    DIRECTION OUTPUT ;
    USE SIGNAL ;
    SHAPE ABUTMENT ;
    PORT
      LAYER metal2 ;
      RECT 1277.905 0.000 1277.975 0.210 ;
    END
  END r0_rd_out[164]
  PIN r0_rd_out[165]
    DIRECTION OUTPUT ;
    USE SIGNAL ;
    SHAPE ABUTMENT ;
    PORT
      LAYER metal2 ;
      RECT 1280.945 0.000 1281.015 0.210 ;
    END
  END r0_rd_out[165]
  PIN r0_rd_out[166]
    DIRECTION OUTPUT ;
    USE SIGNAL ;
    SHAPE ABUTMENT ;
    PORT
      LAYER metal2 ;
      RECT 1283.985 0.000 1284.055 0.210 ;
    END
  END r0_rd_out[166]
  PIN r0_rd_out[167]
    DIRECTION OUTPUT ;
    USE SIGNAL ;
    SHAPE ABUTMENT ;
    PORT
      LAYER metal2 ;
      RECT 1287.025 0.000 1287.095 0.210 ;
    END
  END r0_rd_out[167]
  PIN r0_rd_out[168]
    DIRECTION OUTPUT ;
    USE SIGNAL ;
    SHAPE ABUTMENT ;
    PORT
      LAYER metal2 ;
      RECT 1290.065 0.000 1290.135 0.210 ;
    END
  END r0_rd_out[168]
  PIN r0_rd_out[169]
    DIRECTION OUTPUT ;
    USE SIGNAL ;
    SHAPE ABUTMENT ;
    PORT
      LAYER metal2 ;
      RECT 1293.105 0.000 1293.175 0.210 ;
    END
  END r0_rd_out[169]
  PIN r0_rd_out[170]
    DIRECTION OUTPUT ;
    USE SIGNAL ;
    SHAPE ABUTMENT ;
    PORT
      LAYER metal2 ;
      RECT 1296.145 0.000 1296.215 0.210 ;
    END
  END r0_rd_out[170]
  PIN r0_rd_out[171]
    DIRECTION OUTPUT ;
    USE SIGNAL ;
    SHAPE ABUTMENT ;
    PORT
      LAYER metal2 ;
      RECT 1299.185 0.000 1299.255 0.210 ;
    END
  END r0_rd_out[171]
  PIN r0_rd_out[172]
    DIRECTION OUTPUT ;
    USE SIGNAL ;
    SHAPE ABUTMENT ;
    PORT
      LAYER metal2 ;
      RECT 1302.225 0.000 1302.295 0.210 ;
    END
  END r0_rd_out[172]
  PIN r0_rd_out[173]
    DIRECTION OUTPUT ;
    USE SIGNAL ;
    SHAPE ABUTMENT ;
    PORT
      LAYER metal2 ;
      RECT 1305.265 0.000 1305.335 0.210 ;
    END
  END r0_rd_out[173]
  PIN r0_rd_out[174]
    DIRECTION OUTPUT ;
    USE SIGNAL ;
    SHAPE ABUTMENT ;
    PORT
      LAYER metal2 ;
      RECT 1308.305 0.000 1308.375 0.210 ;
    END
  END r0_rd_out[174]
  PIN r0_rd_out[175]
    DIRECTION OUTPUT ;
    USE SIGNAL ;
    SHAPE ABUTMENT ;
    PORT
      LAYER metal2 ;
      RECT 1311.345 0.000 1311.415 0.210 ;
    END
  END r0_rd_out[175]
  PIN r0_rd_out[176]
    DIRECTION OUTPUT ;
    USE SIGNAL ;
    SHAPE ABUTMENT ;
    PORT
      LAYER metal2 ;
      RECT 1314.385 0.000 1314.455 0.210 ;
    END
  END r0_rd_out[176]
  PIN r0_rd_out[177]
    DIRECTION OUTPUT ;
    USE SIGNAL ;
    SHAPE ABUTMENT ;
    PORT
      LAYER metal2 ;
      RECT 1317.425 0.000 1317.495 0.210 ;
    END
  END r0_rd_out[177]
  PIN r0_rd_out[178]
    DIRECTION OUTPUT ;
    USE SIGNAL ;
    SHAPE ABUTMENT ;
    PORT
      LAYER metal2 ;
      RECT 1320.465 0.000 1320.535 0.210 ;
    END
  END r0_rd_out[178]
  PIN r0_rd_out[179]
    DIRECTION OUTPUT ;
    USE SIGNAL ;
    SHAPE ABUTMENT ;
    PORT
      LAYER metal2 ;
      RECT 1323.505 0.000 1323.575 0.210 ;
    END
  END r0_rd_out[179]
  PIN r0_rd_out[180]
    DIRECTION OUTPUT ;
    USE SIGNAL ;
    SHAPE ABUTMENT ;
    PORT
      LAYER metal2 ;
      RECT 1326.545 0.000 1326.615 0.210 ;
    END
  END r0_rd_out[180]
  PIN r0_rd_out[181]
    DIRECTION OUTPUT ;
    USE SIGNAL ;
    SHAPE ABUTMENT ;
    PORT
      LAYER metal2 ;
      RECT 1329.585 0.000 1329.655 0.210 ;
    END
  END r0_rd_out[181]
  PIN r0_rd_out[182]
    DIRECTION OUTPUT ;
    USE SIGNAL ;
    SHAPE ABUTMENT ;
    PORT
      LAYER metal2 ;
      RECT 1332.625 0.000 1332.695 0.210 ;
    END
  END r0_rd_out[182]
  PIN r0_rd_out[183]
    DIRECTION OUTPUT ;
    USE SIGNAL ;
    SHAPE ABUTMENT ;
    PORT
      LAYER metal2 ;
      RECT 1335.665 0.000 1335.735 0.210 ;
    END
  END r0_rd_out[183]
  PIN r0_rd_out[184]
    DIRECTION OUTPUT ;
    USE SIGNAL ;
    SHAPE ABUTMENT ;
    PORT
      LAYER metal2 ;
      RECT 1338.705 0.000 1338.775 0.210 ;
    END
  END r0_rd_out[184]
  PIN r0_rd_out[185]
    DIRECTION OUTPUT ;
    USE SIGNAL ;
    SHAPE ABUTMENT ;
    PORT
      LAYER metal2 ;
      RECT 1341.745 0.000 1341.815 0.210 ;
    END
  END r0_rd_out[185]
  PIN r0_rd_out[186]
    DIRECTION OUTPUT ;
    USE SIGNAL ;
    SHAPE ABUTMENT ;
    PORT
      LAYER metal2 ;
      RECT 1344.785 0.000 1344.855 0.210 ;
    END
  END r0_rd_out[186]
  PIN r0_rd_out[187]
    DIRECTION OUTPUT ;
    USE SIGNAL ;
    SHAPE ABUTMENT ;
    PORT
      LAYER metal2 ;
      RECT 1347.825 0.000 1347.895 0.210 ;
    END
  END r0_rd_out[187]
  PIN r0_rd_out[188]
    DIRECTION OUTPUT ;
    USE SIGNAL ;
    SHAPE ABUTMENT ;
    PORT
      LAYER metal2 ;
      RECT 1350.865 0.000 1350.935 0.210 ;
    END
  END r0_rd_out[188]
  PIN r0_rd_out[189]
    DIRECTION OUTPUT ;
    USE SIGNAL ;
    SHAPE ABUTMENT ;
    PORT
      LAYER metal2 ;
      RECT 1353.905 0.000 1353.975 0.210 ;
    END
  END r0_rd_out[189]
  PIN r0_rd_out[190]
    DIRECTION OUTPUT ;
    USE SIGNAL ;
    SHAPE ABUTMENT ;
    PORT
      LAYER metal2 ;
      RECT 1356.945 0.000 1357.015 0.210 ;
    END
  END r0_rd_out[190]
  PIN r0_rd_out[191]
    DIRECTION OUTPUT ;
    USE SIGNAL ;
    SHAPE ABUTMENT ;
    PORT
      LAYER metal2 ;
      RECT 1359.985 0.000 1360.055 0.210 ;
    END
  END r0_rd_out[191]
  PIN r0_rd_out[192]
    DIRECTION OUTPUT ;
    USE SIGNAL ;
    SHAPE ABUTMENT ;
    PORT
      LAYER metal2 ;
      RECT 1363.025 0.000 1363.095 0.210 ;
    END
  END r0_rd_out[192]
  PIN r0_rd_out[193]
    DIRECTION OUTPUT ;
    USE SIGNAL ;
    SHAPE ABUTMENT ;
    PORT
      LAYER metal2 ;
      RECT 1366.065 0.000 1366.135 0.210 ;
    END
  END r0_rd_out[193]
  PIN r0_rd_out[194]
    DIRECTION OUTPUT ;
    USE SIGNAL ;
    SHAPE ABUTMENT ;
    PORT
      LAYER metal2 ;
      RECT 1369.105 0.000 1369.175 0.210 ;
    END
  END r0_rd_out[194]
  PIN r0_rd_out[195]
    DIRECTION OUTPUT ;
    USE SIGNAL ;
    SHAPE ABUTMENT ;
    PORT
      LAYER metal2 ;
      RECT 1372.145 0.000 1372.215 0.210 ;
    END
  END r0_rd_out[195]
  PIN r0_rd_out[196]
    DIRECTION OUTPUT ;
    USE SIGNAL ;
    SHAPE ABUTMENT ;
    PORT
      LAYER metal2 ;
      RECT 1375.185 0.000 1375.255 0.210 ;
    END
  END r0_rd_out[196]
  PIN r0_rd_out[197]
    DIRECTION OUTPUT ;
    USE SIGNAL ;
    SHAPE ABUTMENT ;
    PORT
      LAYER metal2 ;
      RECT 1378.225 0.000 1378.295 0.210 ;
    END
  END r0_rd_out[197]
  PIN r0_rd_out[198]
    DIRECTION OUTPUT ;
    USE SIGNAL ;
    SHAPE ABUTMENT ;
    PORT
      LAYER metal2 ;
      RECT 1381.265 0.000 1381.335 0.210 ;
    END
  END r0_rd_out[198]
  PIN r0_rd_out[199]
    DIRECTION OUTPUT ;
    USE SIGNAL ;
    SHAPE ABUTMENT ;
    PORT
      LAYER metal2 ;
      RECT 1384.305 0.000 1384.375 0.210 ;
    END
  END r0_rd_out[199]
  PIN r0_rd_out[200]
    DIRECTION OUTPUT ;
    USE SIGNAL ;
    SHAPE ABUTMENT ;
    PORT
      LAYER metal2 ;
      RECT 1387.345 0.000 1387.415 0.210 ;
    END
  END r0_rd_out[200]
  PIN r0_rd_out[201]
    DIRECTION OUTPUT ;
    USE SIGNAL ;
    SHAPE ABUTMENT ;
    PORT
      LAYER metal2 ;
      RECT 1390.385 0.000 1390.455 0.210 ;
    END
  END r0_rd_out[201]
  PIN r0_rd_out[202]
    DIRECTION OUTPUT ;
    USE SIGNAL ;
    SHAPE ABUTMENT ;
    PORT
      LAYER metal2 ;
      RECT 1393.425 0.000 1393.495 0.210 ;
    END
  END r0_rd_out[202]
  PIN r0_rd_out[203]
    DIRECTION OUTPUT ;
    USE SIGNAL ;
    SHAPE ABUTMENT ;
    PORT
      LAYER metal2 ;
      RECT 1396.465 0.000 1396.535 0.210 ;
    END
  END r0_rd_out[203]
  PIN r0_rd_out[204]
    DIRECTION OUTPUT ;
    USE SIGNAL ;
    SHAPE ABUTMENT ;
    PORT
      LAYER metal2 ;
      RECT 1399.505 0.000 1399.575 0.210 ;
    END
  END r0_rd_out[204]
  PIN r0_rd_out[205]
    DIRECTION OUTPUT ;
    USE SIGNAL ;
    SHAPE ABUTMENT ;
    PORT
      LAYER metal2 ;
      RECT 1402.545 0.000 1402.615 0.210 ;
    END
  END r0_rd_out[205]
  PIN r0_rd_out[206]
    DIRECTION OUTPUT ;
    USE SIGNAL ;
    SHAPE ABUTMENT ;
    PORT
      LAYER metal2 ;
      RECT 1405.585 0.000 1405.655 0.210 ;
    END
  END r0_rd_out[206]
  PIN r0_rd_out[207]
    DIRECTION OUTPUT ;
    USE SIGNAL ;
    SHAPE ABUTMENT ;
    PORT
      LAYER metal2 ;
      RECT 1408.625 0.000 1408.695 0.210 ;
    END
  END r0_rd_out[207]
  PIN r0_rd_out[208]
    DIRECTION OUTPUT ;
    USE SIGNAL ;
    SHAPE ABUTMENT ;
    PORT
      LAYER metal2 ;
      RECT 1411.665 0.000 1411.735 0.210 ;
    END
  END r0_rd_out[208]
  PIN r0_rd_out[209]
    DIRECTION OUTPUT ;
    USE SIGNAL ;
    SHAPE ABUTMENT ;
    PORT
      LAYER metal2 ;
      RECT 1414.705 0.000 1414.775 0.210 ;
    END
  END r0_rd_out[209]
  PIN r0_rd_out[210]
    DIRECTION OUTPUT ;
    USE SIGNAL ;
    SHAPE ABUTMENT ;
    PORT
      LAYER metal2 ;
      RECT 1417.745 0.000 1417.815 0.210 ;
    END
  END r0_rd_out[210]
  PIN r0_rd_out[211]
    DIRECTION OUTPUT ;
    USE SIGNAL ;
    SHAPE ABUTMENT ;
    PORT
      LAYER metal2 ;
      RECT 1420.785 0.000 1420.855 0.210 ;
    END
  END r0_rd_out[211]
  PIN r0_rd_out[212]
    DIRECTION OUTPUT ;
    USE SIGNAL ;
    SHAPE ABUTMENT ;
    PORT
      LAYER metal2 ;
      RECT 1423.825 0.000 1423.895 0.210 ;
    END
  END r0_rd_out[212]
  PIN r0_rd_out[213]
    DIRECTION OUTPUT ;
    USE SIGNAL ;
    SHAPE ABUTMENT ;
    PORT
      LAYER metal2 ;
      RECT 1426.865 0.000 1426.935 0.210 ;
    END
  END r0_rd_out[213]
  PIN r0_rd_out[214]
    DIRECTION OUTPUT ;
    USE SIGNAL ;
    SHAPE ABUTMENT ;
    PORT
      LAYER metal2 ;
      RECT 1429.905 0.000 1429.975 0.210 ;
    END
  END r0_rd_out[214]
  PIN r0_rd_out[215]
    DIRECTION OUTPUT ;
    USE SIGNAL ;
    SHAPE ABUTMENT ;
    PORT
      LAYER metal2 ;
      RECT 1432.945 0.000 1433.015 0.210 ;
    END
  END r0_rd_out[215]
  PIN r0_rd_out[216]
    DIRECTION OUTPUT ;
    USE SIGNAL ;
    SHAPE ABUTMENT ;
    PORT
      LAYER metal2 ;
      RECT 1435.985 0.000 1436.055 0.210 ;
    END
  END r0_rd_out[216]
  PIN r0_rd_out[217]
    DIRECTION OUTPUT ;
    USE SIGNAL ;
    SHAPE ABUTMENT ;
    PORT
      LAYER metal2 ;
      RECT 1439.025 0.000 1439.095 0.210 ;
    END
  END r0_rd_out[217]
  PIN r0_rd_out[218]
    DIRECTION OUTPUT ;
    USE SIGNAL ;
    SHAPE ABUTMENT ;
    PORT
      LAYER metal2 ;
      RECT 1442.065 0.000 1442.135 0.210 ;
    END
  END r0_rd_out[218]
  PIN r0_rd_out[219]
    DIRECTION OUTPUT ;
    USE SIGNAL ;
    SHAPE ABUTMENT ;
    PORT
      LAYER metal2 ;
      RECT 1445.105 0.000 1445.175 0.210 ;
    END
  END r0_rd_out[219]
  PIN r0_rd_out[220]
    DIRECTION OUTPUT ;
    USE SIGNAL ;
    SHAPE ABUTMENT ;
    PORT
      LAYER metal2 ;
      RECT 1448.145 0.000 1448.215 0.210 ;
    END
  END r0_rd_out[220]
  PIN r0_rd_out[221]
    DIRECTION OUTPUT ;
    USE SIGNAL ;
    SHAPE ABUTMENT ;
    PORT
      LAYER metal2 ;
      RECT 1451.185 0.000 1451.255 0.210 ;
    END
  END r0_rd_out[221]
  PIN r0_rd_out[222]
    DIRECTION OUTPUT ;
    USE SIGNAL ;
    SHAPE ABUTMENT ;
    PORT
      LAYER metal2 ;
      RECT 1454.225 0.000 1454.295 0.210 ;
    END
  END r0_rd_out[222]
  PIN r0_rd_out[223]
    DIRECTION OUTPUT ;
    USE SIGNAL ;
    SHAPE ABUTMENT ;
    PORT
      LAYER metal2 ;
      RECT 1457.265 0.000 1457.335 0.210 ;
    END
  END r0_rd_out[223]
  PIN r0_rd_out[224]
    DIRECTION OUTPUT ;
    USE SIGNAL ;
    SHAPE ABUTMENT ;
    PORT
      LAYER metal2 ;
      RECT 1460.305 0.000 1460.375 0.210 ;
    END
  END r0_rd_out[224]
  PIN r0_rd_out[225]
    DIRECTION OUTPUT ;
    USE SIGNAL ;
    SHAPE ABUTMENT ;
    PORT
      LAYER metal2 ;
      RECT 1463.345 0.000 1463.415 0.210 ;
    END
  END r0_rd_out[225]
  PIN r0_rd_out[226]
    DIRECTION OUTPUT ;
    USE SIGNAL ;
    SHAPE ABUTMENT ;
    PORT
      LAYER metal2 ;
      RECT 1466.385 0.000 1466.455 0.210 ;
    END
  END r0_rd_out[226]
  PIN r0_rd_out[227]
    DIRECTION OUTPUT ;
    USE SIGNAL ;
    SHAPE ABUTMENT ;
    PORT
      LAYER metal2 ;
      RECT 1469.425 0.000 1469.495 0.210 ;
    END
  END r0_rd_out[227]
  PIN r0_rd_out[228]
    DIRECTION OUTPUT ;
    USE SIGNAL ;
    SHAPE ABUTMENT ;
    PORT
      LAYER metal2 ;
      RECT 1472.465 0.000 1472.535 0.210 ;
    END
  END r0_rd_out[228]
  PIN r0_rd_out[229]
    DIRECTION OUTPUT ;
    USE SIGNAL ;
    SHAPE ABUTMENT ;
    PORT
      LAYER metal2 ;
      RECT 1475.505 0.000 1475.575 0.210 ;
    END
  END r0_rd_out[229]
  PIN r0_rd_out[230]
    DIRECTION OUTPUT ;
    USE SIGNAL ;
    SHAPE ABUTMENT ;
    PORT
      LAYER metal2 ;
      RECT 1478.545 0.000 1478.615 0.210 ;
    END
  END r0_rd_out[230]
  PIN r0_rd_out[231]
    DIRECTION OUTPUT ;
    USE SIGNAL ;
    SHAPE ABUTMENT ;
    PORT
      LAYER metal2 ;
      RECT 1481.585 0.000 1481.655 0.210 ;
    END
  END r0_rd_out[231]
  PIN r0_rd_out[232]
    DIRECTION OUTPUT ;
    USE SIGNAL ;
    SHAPE ABUTMENT ;
    PORT
      LAYER metal2 ;
      RECT 1484.625 0.000 1484.695 0.210 ;
    END
  END r0_rd_out[232]
  PIN r0_rd_out[233]
    DIRECTION OUTPUT ;
    USE SIGNAL ;
    SHAPE ABUTMENT ;
    PORT
      LAYER metal2 ;
      RECT 1487.665 0.000 1487.735 0.210 ;
    END
  END r0_rd_out[233]
  PIN r0_rd_out[234]
    DIRECTION OUTPUT ;
    USE SIGNAL ;
    SHAPE ABUTMENT ;
    PORT
      LAYER metal2 ;
      RECT 1490.705 0.000 1490.775 0.210 ;
    END
  END r0_rd_out[234]
  PIN r0_rd_out[235]
    DIRECTION OUTPUT ;
    USE SIGNAL ;
    SHAPE ABUTMENT ;
    PORT
      LAYER metal2 ;
      RECT 1493.745 0.000 1493.815 0.210 ;
    END
  END r0_rd_out[235]
  PIN r0_rd_out[236]
    DIRECTION OUTPUT ;
    USE SIGNAL ;
    SHAPE ABUTMENT ;
    PORT
      LAYER metal2 ;
      RECT 1496.785 0.000 1496.855 0.210 ;
    END
  END r0_rd_out[236]
  PIN r0_rd_out[237]
    DIRECTION OUTPUT ;
    USE SIGNAL ;
    SHAPE ABUTMENT ;
    PORT
      LAYER metal2 ;
      RECT 1499.825 0.000 1499.895 0.210 ;
    END
  END r0_rd_out[237]
  PIN r0_rd_out[238]
    DIRECTION OUTPUT ;
    USE SIGNAL ;
    SHAPE ABUTMENT ;
    PORT
      LAYER metal2 ;
      RECT 1502.865 0.000 1502.935 0.210 ;
    END
  END r0_rd_out[238]
  PIN r0_rd_out[239]
    DIRECTION OUTPUT ;
    USE SIGNAL ;
    SHAPE ABUTMENT ;
    PORT
      LAYER metal2 ;
      RECT 1505.905 0.000 1505.975 0.210 ;
    END
  END r0_rd_out[239]
  PIN r0_rd_out[240]
    DIRECTION OUTPUT ;
    USE SIGNAL ;
    SHAPE ABUTMENT ;
    PORT
      LAYER metal2 ;
      RECT 1508.945 0.000 1509.015 0.210 ;
    END
  END r0_rd_out[240]
  PIN r0_rd_out[241]
    DIRECTION OUTPUT ;
    USE SIGNAL ;
    SHAPE ABUTMENT ;
    PORT
      LAYER metal2 ;
      RECT 1511.985 0.000 1512.055 0.210 ;
    END
  END r0_rd_out[241]
  PIN r0_rd_out[242]
    DIRECTION OUTPUT ;
    USE SIGNAL ;
    SHAPE ABUTMENT ;
    PORT
      LAYER metal2 ;
      RECT 1515.025 0.000 1515.095 0.210 ;
    END
  END r0_rd_out[242]
  PIN r0_rd_out[243]
    DIRECTION OUTPUT ;
    USE SIGNAL ;
    SHAPE ABUTMENT ;
    PORT
      LAYER metal2 ;
      RECT 1518.065 0.000 1518.135 0.210 ;
    END
  END r0_rd_out[243]
  PIN r0_rd_out[244]
    DIRECTION OUTPUT ;
    USE SIGNAL ;
    SHAPE ABUTMENT ;
    PORT
      LAYER metal2 ;
      RECT 1521.105 0.000 1521.175 0.210 ;
    END
  END r0_rd_out[244]
  PIN r0_rd_out[245]
    DIRECTION OUTPUT ;
    USE SIGNAL ;
    SHAPE ABUTMENT ;
    PORT
      LAYER metal2 ;
      RECT 1524.145 0.000 1524.215 0.210 ;
    END
  END r0_rd_out[245]
  PIN r0_rd_out[246]
    DIRECTION OUTPUT ;
    USE SIGNAL ;
    SHAPE ABUTMENT ;
    PORT
      LAYER metal2 ;
      RECT 1527.185 0.000 1527.255 0.210 ;
    END
  END r0_rd_out[246]
  PIN r0_rd_out[247]
    DIRECTION OUTPUT ;
    USE SIGNAL ;
    SHAPE ABUTMENT ;
    PORT
      LAYER metal2 ;
      RECT 1530.225 0.000 1530.295 0.210 ;
    END
  END r0_rd_out[247]
  PIN r0_rd_out[248]
    DIRECTION OUTPUT ;
    USE SIGNAL ;
    SHAPE ABUTMENT ;
    PORT
      LAYER metal2 ;
      RECT 1533.265 0.000 1533.335 0.210 ;
    END
  END r0_rd_out[248]
  PIN r0_rd_out[249]
    DIRECTION OUTPUT ;
    USE SIGNAL ;
    SHAPE ABUTMENT ;
    PORT
      LAYER metal2 ;
      RECT 1536.305 0.000 1536.375 0.210 ;
    END
  END r0_rd_out[249]
  PIN r0_rd_out[250]
    DIRECTION OUTPUT ;
    USE SIGNAL ;
    SHAPE ABUTMENT ;
    PORT
      LAYER metal2 ;
      RECT 1539.345 0.000 1539.415 0.210 ;
    END
  END r0_rd_out[250]
  PIN r0_rd_out[251]
    DIRECTION OUTPUT ;
    USE SIGNAL ;
    SHAPE ABUTMENT ;
    PORT
      LAYER metal2 ;
      RECT 1542.385 0.000 1542.455 0.210 ;
    END
  END r0_rd_out[251]
  PIN r0_rd_out[252]
    DIRECTION OUTPUT ;
    USE SIGNAL ;
    SHAPE ABUTMENT ;
    PORT
      LAYER metal2 ;
      RECT 1545.425 0.000 1545.495 0.210 ;
    END
  END r0_rd_out[252]
  PIN r0_rd_out[253]
    DIRECTION OUTPUT ;
    USE SIGNAL ;
    SHAPE ABUTMENT ;
    PORT
      LAYER metal2 ;
      RECT 1548.465 0.000 1548.535 0.210 ;
    END
  END r0_rd_out[253]
  PIN r0_rd_out[254]
    DIRECTION OUTPUT ;
    USE SIGNAL ;
    SHAPE ABUTMENT ;
    PORT
      LAYER metal2 ;
      RECT 1551.505 0.000 1551.575 0.210 ;
    END
  END r0_rd_out[254]
  PIN r0_rd_out[255]
    DIRECTION OUTPUT ;
    USE SIGNAL ;
    SHAPE ABUTMENT ;
    PORT
      LAYER metal2 ;
      RECT 1554.545 0.000 1554.615 0.210 ;
    END
  END r0_rd_out[255]
  PIN r0_rd_out[256]
    DIRECTION OUTPUT ;
    USE SIGNAL ;
    SHAPE ABUTMENT ;
    PORT
      LAYER metal2 ;
      RECT 1.105 1511.790 1.175 1512.000 ;
    END
  END r0_rd_out[256]
  PIN r0_rd_out[257]
    DIRECTION OUTPUT ;
    USE SIGNAL ;
    SHAPE ABUTMENT ;
    PORT
      LAYER metal2 ;
      RECT 7.185 1511.790 7.255 1512.000 ;
    END
  END r0_rd_out[257]
  PIN r0_rd_out[258]
    DIRECTION OUTPUT ;
    USE SIGNAL ;
    SHAPE ABUTMENT ;
    PORT
      LAYER metal2 ;
      RECT 13.265 1511.790 13.335 1512.000 ;
    END
  END r0_rd_out[258]
  PIN r0_rd_out[259]
    DIRECTION OUTPUT ;
    USE SIGNAL ;
    SHAPE ABUTMENT ;
    PORT
      LAYER metal2 ;
      RECT 19.345 1511.790 19.415 1512.000 ;
    END
  END r0_rd_out[259]
  PIN r0_rd_out[260]
    DIRECTION OUTPUT ;
    USE SIGNAL ;
    SHAPE ABUTMENT ;
    PORT
      LAYER metal2 ;
      RECT 25.425 1511.790 25.495 1512.000 ;
    END
  END r0_rd_out[260]
  PIN r0_rd_out[261]
    DIRECTION OUTPUT ;
    USE SIGNAL ;
    SHAPE ABUTMENT ;
    PORT
      LAYER metal2 ;
      RECT 31.505 1511.790 31.575 1512.000 ;
    END
  END r0_rd_out[261]
  PIN r0_rd_out[262]
    DIRECTION OUTPUT ;
    USE SIGNAL ;
    SHAPE ABUTMENT ;
    PORT
      LAYER metal2 ;
      RECT 37.585 1511.790 37.655 1512.000 ;
    END
  END r0_rd_out[262]
  PIN r0_rd_out[263]
    DIRECTION OUTPUT ;
    USE SIGNAL ;
    SHAPE ABUTMENT ;
    PORT
      LAYER metal2 ;
      RECT 43.665 1511.790 43.735 1512.000 ;
    END
  END r0_rd_out[263]
  PIN r0_rd_out[264]
    DIRECTION OUTPUT ;
    USE SIGNAL ;
    SHAPE ABUTMENT ;
    PORT
      LAYER metal2 ;
      RECT 49.745 1511.790 49.815 1512.000 ;
    END
  END r0_rd_out[264]
  PIN r0_rd_out[265]
    DIRECTION OUTPUT ;
    USE SIGNAL ;
    SHAPE ABUTMENT ;
    PORT
      LAYER metal2 ;
      RECT 55.825 1511.790 55.895 1512.000 ;
    END
  END r0_rd_out[265]
  PIN r0_rd_out[266]
    DIRECTION OUTPUT ;
    USE SIGNAL ;
    SHAPE ABUTMENT ;
    PORT
      LAYER metal2 ;
      RECT 61.905 1511.790 61.975 1512.000 ;
    END
  END r0_rd_out[266]
  PIN r0_rd_out[267]
    DIRECTION OUTPUT ;
    USE SIGNAL ;
    SHAPE ABUTMENT ;
    PORT
      LAYER metal2 ;
      RECT 67.985 1511.790 68.055 1512.000 ;
    END
  END r0_rd_out[267]
  PIN r0_rd_out[268]
    DIRECTION OUTPUT ;
    USE SIGNAL ;
    SHAPE ABUTMENT ;
    PORT
      LAYER metal2 ;
      RECT 74.065 1511.790 74.135 1512.000 ;
    END
  END r0_rd_out[268]
  PIN r0_rd_out[269]
    DIRECTION OUTPUT ;
    USE SIGNAL ;
    SHAPE ABUTMENT ;
    PORT
      LAYER metal2 ;
      RECT 80.145 1511.790 80.215 1512.000 ;
    END
  END r0_rd_out[269]
  PIN r0_rd_out[270]
    DIRECTION OUTPUT ;
    USE SIGNAL ;
    SHAPE ABUTMENT ;
    PORT
      LAYER metal2 ;
      RECT 86.225 1511.790 86.295 1512.000 ;
    END
  END r0_rd_out[270]
  PIN r0_rd_out[271]
    DIRECTION OUTPUT ;
    USE SIGNAL ;
    SHAPE ABUTMENT ;
    PORT
      LAYER metal2 ;
      RECT 92.305 1511.790 92.375 1512.000 ;
    END
  END r0_rd_out[271]
  PIN r0_rd_out[272]
    DIRECTION OUTPUT ;
    USE SIGNAL ;
    SHAPE ABUTMENT ;
    PORT
      LAYER metal2 ;
      RECT 98.385 1511.790 98.455 1512.000 ;
    END
  END r0_rd_out[272]
  PIN r0_rd_out[273]
    DIRECTION OUTPUT ;
    USE SIGNAL ;
    SHAPE ABUTMENT ;
    PORT
      LAYER metal2 ;
      RECT 104.465 1511.790 104.535 1512.000 ;
    END
  END r0_rd_out[273]
  PIN r0_rd_out[274]
    DIRECTION OUTPUT ;
    USE SIGNAL ;
    SHAPE ABUTMENT ;
    PORT
      LAYER metal2 ;
      RECT 110.545 1511.790 110.615 1512.000 ;
    END
  END r0_rd_out[274]
  PIN r0_rd_out[275]
    DIRECTION OUTPUT ;
    USE SIGNAL ;
    SHAPE ABUTMENT ;
    PORT
      LAYER metal2 ;
      RECT 116.625 1511.790 116.695 1512.000 ;
    END
  END r0_rd_out[275]
  PIN r0_rd_out[276]
    DIRECTION OUTPUT ;
    USE SIGNAL ;
    SHAPE ABUTMENT ;
    PORT
      LAYER metal2 ;
      RECT 122.705 1511.790 122.775 1512.000 ;
    END
  END r0_rd_out[276]
  PIN r0_rd_out[277]
    DIRECTION OUTPUT ;
    USE SIGNAL ;
    SHAPE ABUTMENT ;
    PORT
      LAYER metal2 ;
      RECT 128.785 1511.790 128.855 1512.000 ;
    END
  END r0_rd_out[277]
  PIN r0_rd_out[278]
    DIRECTION OUTPUT ;
    USE SIGNAL ;
    SHAPE ABUTMENT ;
    PORT
      LAYER metal2 ;
      RECT 134.865 1511.790 134.935 1512.000 ;
    END
  END r0_rd_out[278]
  PIN r0_rd_out[279]
    DIRECTION OUTPUT ;
    USE SIGNAL ;
    SHAPE ABUTMENT ;
    PORT
      LAYER metal2 ;
      RECT 140.945 1511.790 141.015 1512.000 ;
    END
  END r0_rd_out[279]
  PIN r0_rd_out[280]
    DIRECTION OUTPUT ;
    USE SIGNAL ;
    SHAPE ABUTMENT ;
    PORT
      LAYER metal2 ;
      RECT 147.025 1511.790 147.095 1512.000 ;
    END
  END r0_rd_out[280]
  PIN r0_rd_out[281]
    DIRECTION OUTPUT ;
    USE SIGNAL ;
    SHAPE ABUTMENT ;
    PORT
      LAYER metal2 ;
      RECT 153.105 1511.790 153.175 1512.000 ;
    END
  END r0_rd_out[281]
  PIN r0_rd_out[282]
    DIRECTION OUTPUT ;
    USE SIGNAL ;
    SHAPE ABUTMENT ;
    PORT
      LAYER metal2 ;
      RECT 159.185 1511.790 159.255 1512.000 ;
    END
  END r0_rd_out[282]
  PIN r0_rd_out[283]
    DIRECTION OUTPUT ;
    USE SIGNAL ;
    SHAPE ABUTMENT ;
    PORT
      LAYER metal2 ;
      RECT 165.265 1511.790 165.335 1512.000 ;
    END
  END r0_rd_out[283]
  PIN r0_rd_out[284]
    DIRECTION OUTPUT ;
    USE SIGNAL ;
    SHAPE ABUTMENT ;
    PORT
      LAYER metal2 ;
      RECT 171.345 1511.790 171.415 1512.000 ;
    END
  END r0_rd_out[284]
  PIN r0_rd_out[285]
    DIRECTION OUTPUT ;
    USE SIGNAL ;
    SHAPE ABUTMENT ;
    PORT
      LAYER metal2 ;
      RECT 177.425 1511.790 177.495 1512.000 ;
    END
  END r0_rd_out[285]
  PIN r0_rd_out[286]
    DIRECTION OUTPUT ;
    USE SIGNAL ;
    SHAPE ABUTMENT ;
    PORT
      LAYER metal2 ;
      RECT 183.505 1511.790 183.575 1512.000 ;
    END
  END r0_rd_out[286]
  PIN r0_rd_out[287]
    DIRECTION OUTPUT ;
    USE SIGNAL ;
    SHAPE ABUTMENT ;
    PORT
      LAYER metal2 ;
      RECT 189.585 1511.790 189.655 1512.000 ;
    END
  END r0_rd_out[287]
  PIN r0_rd_out[288]
    DIRECTION OUTPUT ;
    USE SIGNAL ;
    SHAPE ABUTMENT ;
    PORT
      LAYER metal2 ;
      RECT 195.665 1511.790 195.735 1512.000 ;
    END
  END r0_rd_out[288]
  PIN r0_rd_out[289]
    DIRECTION OUTPUT ;
    USE SIGNAL ;
    SHAPE ABUTMENT ;
    PORT
      LAYER metal2 ;
      RECT 201.745 1511.790 201.815 1512.000 ;
    END
  END r0_rd_out[289]
  PIN r0_rd_out[290]
    DIRECTION OUTPUT ;
    USE SIGNAL ;
    SHAPE ABUTMENT ;
    PORT
      LAYER metal2 ;
      RECT 207.825 1511.790 207.895 1512.000 ;
    END
  END r0_rd_out[290]
  PIN r0_rd_out[291]
    DIRECTION OUTPUT ;
    USE SIGNAL ;
    SHAPE ABUTMENT ;
    PORT
      LAYER metal2 ;
      RECT 213.905 1511.790 213.975 1512.000 ;
    END
  END r0_rd_out[291]
  PIN r0_rd_out[292]
    DIRECTION OUTPUT ;
    USE SIGNAL ;
    SHAPE ABUTMENT ;
    PORT
      LAYER metal2 ;
      RECT 219.985 1511.790 220.055 1512.000 ;
    END
  END r0_rd_out[292]
  PIN r0_rd_out[293]
    DIRECTION OUTPUT ;
    USE SIGNAL ;
    SHAPE ABUTMENT ;
    PORT
      LAYER metal2 ;
      RECT 226.065 1511.790 226.135 1512.000 ;
    END
  END r0_rd_out[293]
  PIN r0_rd_out[294]
    DIRECTION OUTPUT ;
    USE SIGNAL ;
    SHAPE ABUTMENT ;
    PORT
      LAYER metal2 ;
      RECT 232.145 1511.790 232.215 1512.000 ;
    END
  END r0_rd_out[294]
  PIN r0_rd_out[295]
    DIRECTION OUTPUT ;
    USE SIGNAL ;
    SHAPE ABUTMENT ;
    PORT
      LAYER metal2 ;
      RECT 238.225 1511.790 238.295 1512.000 ;
    END
  END r0_rd_out[295]
  PIN r0_rd_out[296]
    DIRECTION OUTPUT ;
    USE SIGNAL ;
    SHAPE ABUTMENT ;
    PORT
      LAYER metal2 ;
      RECT 244.305 1511.790 244.375 1512.000 ;
    END
  END r0_rd_out[296]
  PIN r0_rd_out[297]
    DIRECTION OUTPUT ;
    USE SIGNAL ;
    SHAPE ABUTMENT ;
    PORT
      LAYER metal2 ;
      RECT 250.385 1511.790 250.455 1512.000 ;
    END
  END r0_rd_out[297]
  PIN r0_rd_out[298]
    DIRECTION OUTPUT ;
    USE SIGNAL ;
    SHAPE ABUTMENT ;
    PORT
      LAYER metal2 ;
      RECT 256.465 1511.790 256.535 1512.000 ;
    END
  END r0_rd_out[298]
  PIN r0_rd_out[299]
    DIRECTION OUTPUT ;
    USE SIGNAL ;
    SHAPE ABUTMENT ;
    PORT
      LAYER metal2 ;
      RECT 262.545 1511.790 262.615 1512.000 ;
    END
  END r0_rd_out[299]
  PIN r0_rd_out[300]
    DIRECTION OUTPUT ;
    USE SIGNAL ;
    SHAPE ABUTMENT ;
    PORT
      LAYER metal2 ;
      RECT 268.625 1511.790 268.695 1512.000 ;
    END
  END r0_rd_out[300]
  PIN r0_rd_out[301]
    DIRECTION OUTPUT ;
    USE SIGNAL ;
    SHAPE ABUTMENT ;
    PORT
      LAYER metal2 ;
      RECT 274.705 1511.790 274.775 1512.000 ;
    END
  END r0_rd_out[301]
  PIN r0_rd_out[302]
    DIRECTION OUTPUT ;
    USE SIGNAL ;
    SHAPE ABUTMENT ;
    PORT
      LAYER metal2 ;
      RECT 280.785 1511.790 280.855 1512.000 ;
    END
  END r0_rd_out[302]
  PIN r0_rd_out[303]
    DIRECTION OUTPUT ;
    USE SIGNAL ;
    SHAPE ABUTMENT ;
    PORT
      LAYER metal2 ;
      RECT 286.865 1511.790 286.935 1512.000 ;
    END
  END r0_rd_out[303]
  PIN r0_rd_out[304]
    DIRECTION OUTPUT ;
    USE SIGNAL ;
    SHAPE ABUTMENT ;
    PORT
      LAYER metal2 ;
      RECT 292.945 1511.790 293.015 1512.000 ;
    END
  END r0_rd_out[304]
  PIN r0_rd_out[305]
    DIRECTION OUTPUT ;
    USE SIGNAL ;
    SHAPE ABUTMENT ;
    PORT
      LAYER metal2 ;
      RECT 299.025 1511.790 299.095 1512.000 ;
    END
  END r0_rd_out[305]
  PIN r0_rd_out[306]
    DIRECTION OUTPUT ;
    USE SIGNAL ;
    SHAPE ABUTMENT ;
    PORT
      LAYER metal2 ;
      RECT 305.105 1511.790 305.175 1512.000 ;
    END
  END r0_rd_out[306]
  PIN r0_rd_out[307]
    DIRECTION OUTPUT ;
    USE SIGNAL ;
    SHAPE ABUTMENT ;
    PORT
      LAYER metal2 ;
      RECT 311.185 1511.790 311.255 1512.000 ;
    END
  END r0_rd_out[307]
  PIN r0_rd_out[308]
    DIRECTION OUTPUT ;
    USE SIGNAL ;
    SHAPE ABUTMENT ;
    PORT
      LAYER metal2 ;
      RECT 317.265 1511.790 317.335 1512.000 ;
    END
  END r0_rd_out[308]
  PIN r0_rd_out[309]
    DIRECTION OUTPUT ;
    USE SIGNAL ;
    SHAPE ABUTMENT ;
    PORT
      LAYER metal2 ;
      RECT 323.345 1511.790 323.415 1512.000 ;
    END
  END r0_rd_out[309]
  PIN r0_rd_out[310]
    DIRECTION OUTPUT ;
    USE SIGNAL ;
    SHAPE ABUTMENT ;
    PORT
      LAYER metal2 ;
      RECT 329.425 1511.790 329.495 1512.000 ;
    END
  END r0_rd_out[310]
  PIN r0_rd_out[311]
    DIRECTION OUTPUT ;
    USE SIGNAL ;
    SHAPE ABUTMENT ;
    PORT
      LAYER metal2 ;
      RECT 335.505 1511.790 335.575 1512.000 ;
    END
  END r0_rd_out[311]
  PIN r0_rd_out[312]
    DIRECTION OUTPUT ;
    USE SIGNAL ;
    SHAPE ABUTMENT ;
    PORT
      LAYER metal2 ;
      RECT 341.585 1511.790 341.655 1512.000 ;
    END
  END r0_rd_out[312]
  PIN r0_rd_out[313]
    DIRECTION OUTPUT ;
    USE SIGNAL ;
    SHAPE ABUTMENT ;
    PORT
      LAYER metal2 ;
      RECT 347.665 1511.790 347.735 1512.000 ;
    END
  END r0_rd_out[313]
  PIN r0_rd_out[314]
    DIRECTION OUTPUT ;
    USE SIGNAL ;
    SHAPE ABUTMENT ;
    PORT
      LAYER metal2 ;
      RECT 353.745 1511.790 353.815 1512.000 ;
    END
  END r0_rd_out[314]
  PIN r0_rd_out[315]
    DIRECTION OUTPUT ;
    USE SIGNAL ;
    SHAPE ABUTMENT ;
    PORT
      LAYER metal2 ;
      RECT 359.825 1511.790 359.895 1512.000 ;
    END
  END r0_rd_out[315]
  PIN r0_rd_out[316]
    DIRECTION OUTPUT ;
    USE SIGNAL ;
    SHAPE ABUTMENT ;
    PORT
      LAYER metal2 ;
      RECT 365.905 1511.790 365.975 1512.000 ;
    END
  END r0_rd_out[316]
  PIN r0_rd_out[317]
    DIRECTION OUTPUT ;
    USE SIGNAL ;
    SHAPE ABUTMENT ;
    PORT
      LAYER metal2 ;
      RECT 371.985 1511.790 372.055 1512.000 ;
    END
  END r0_rd_out[317]
  PIN r0_rd_out[318]
    DIRECTION OUTPUT ;
    USE SIGNAL ;
    SHAPE ABUTMENT ;
    PORT
      LAYER metal2 ;
      RECT 378.065 1511.790 378.135 1512.000 ;
    END
  END r0_rd_out[318]
  PIN r0_rd_out[319]
    DIRECTION OUTPUT ;
    USE SIGNAL ;
    SHAPE ABUTMENT ;
    PORT
      LAYER metal2 ;
      RECT 384.145 1511.790 384.215 1512.000 ;
    END
  END r0_rd_out[319]
  PIN r0_rd_out[320]
    DIRECTION OUTPUT ;
    USE SIGNAL ;
    SHAPE ABUTMENT ;
    PORT
      LAYER metal2 ;
      RECT 390.225 1511.790 390.295 1512.000 ;
    END
  END r0_rd_out[320]
  PIN r0_rd_out[321]
    DIRECTION OUTPUT ;
    USE SIGNAL ;
    SHAPE ABUTMENT ;
    PORT
      LAYER metal2 ;
      RECT 396.305 1511.790 396.375 1512.000 ;
    END
  END r0_rd_out[321]
  PIN r0_rd_out[322]
    DIRECTION OUTPUT ;
    USE SIGNAL ;
    SHAPE ABUTMENT ;
    PORT
      LAYER metal2 ;
      RECT 402.385 1511.790 402.455 1512.000 ;
    END
  END r0_rd_out[322]
  PIN r0_rd_out[323]
    DIRECTION OUTPUT ;
    USE SIGNAL ;
    SHAPE ABUTMENT ;
    PORT
      LAYER metal2 ;
      RECT 408.465 1511.790 408.535 1512.000 ;
    END
  END r0_rd_out[323]
  PIN r0_rd_out[324]
    DIRECTION OUTPUT ;
    USE SIGNAL ;
    SHAPE ABUTMENT ;
    PORT
      LAYER metal2 ;
      RECT 414.545 1511.790 414.615 1512.000 ;
    END
  END r0_rd_out[324]
  PIN r0_rd_out[325]
    DIRECTION OUTPUT ;
    USE SIGNAL ;
    SHAPE ABUTMENT ;
    PORT
      LAYER metal2 ;
      RECT 420.625 1511.790 420.695 1512.000 ;
    END
  END r0_rd_out[325]
  PIN r0_rd_out[326]
    DIRECTION OUTPUT ;
    USE SIGNAL ;
    SHAPE ABUTMENT ;
    PORT
      LAYER metal2 ;
      RECT 426.705 1511.790 426.775 1512.000 ;
    END
  END r0_rd_out[326]
  PIN r0_rd_out[327]
    DIRECTION OUTPUT ;
    USE SIGNAL ;
    SHAPE ABUTMENT ;
    PORT
      LAYER metal2 ;
      RECT 432.785 1511.790 432.855 1512.000 ;
    END
  END r0_rd_out[327]
  PIN r0_rd_out[328]
    DIRECTION OUTPUT ;
    USE SIGNAL ;
    SHAPE ABUTMENT ;
    PORT
      LAYER metal2 ;
      RECT 438.865 1511.790 438.935 1512.000 ;
    END
  END r0_rd_out[328]
  PIN r0_rd_out[329]
    DIRECTION OUTPUT ;
    USE SIGNAL ;
    SHAPE ABUTMENT ;
    PORT
      LAYER metal2 ;
      RECT 444.945 1511.790 445.015 1512.000 ;
    END
  END r0_rd_out[329]
  PIN r0_rd_out[330]
    DIRECTION OUTPUT ;
    USE SIGNAL ;
    SHAPE ABUTMENT ;
    PORT
      LAYER metal2 ;
      RECT 451.025 1511.790 451.095 1512.000 ;
    END
  END r0_rd_out[330]
  PIN r0_rd_out[331]
    DIRECTION OUTPUT ;
    USE SIGNAL ;
    SHAPE ABUTMENT ;
    PORT
      LAYER metal2 ;
      RECT 457.105 1511.790 457.175 1512.000 ;
    END
  END r0_rd_out[331]
  PIN r0_rd_out[332]
    DIRECTION OUTPUT ;
    USE SIGNAL ;
    SHAPE ABUTMENT ;
    PORT
      LAYER metal2 ;
      RECT 463.185 1511.790 463.255 1512.000 ;
    END
  END r0_rd_out[332]
  PIN r0_rd_out[333]
    DIRECTION OUTPUT ;
    USE SIGNAL ;
    SHAPE ABUTMENT ;
    PORT
      LAYER metal2 ;
      RECT 469.265 1511.790 469.335 1512.000 ;
    END
  END r0_rd_out[333]
  PIN r0_rd_out[334]
    DIRECTION OUTPUT ;
    USE SIGNAL ;
    SHAPE ABUTMENT ;
    PORT
      LAYER metal2 ;
      RECT 475.345 1511.790 475.415 1512.000 ;
    END
  END r0_rd_out[334]
  PIN r0_rd_out[335]
    DIRECTION OUTPUT ;
    USE SIGNAL ;
    SHAPE ABUTMENT ;
    PORT
      LAYER metal2 ;
      RECT 481.425 1511.790 481.495 1512.000 ;
    END
  END r0_rd_out[335]
  PIN r0_rd_out[336]
    DIRECTION OUTPUT ;
    USE SIGNAL ;
    SHAPE ABUTMENT ;
    PORT
      LAYER metal2 ;
      RECT 487.505 1511.790 487.575 1512.000 ;
    END
  END r0_rd_out[336]
  PIN r0_rd_out[337]
    DIRECTION OUTPUT ;
    USE SIGNAL ;
    SHAPE ABUTMENT ;
    PORT
      LAYER metal2 ;
      RECT 493.585 1511.790 493.655 1512.000 ;
    END
  END r0_rd_out[337]
  PIN r0_rd_out[338]
    DIRECTION OUTPUT ;
    USE SIGNAL ;
    SHAPE ABUTMENT ;
    PORT
      LAYER metal2 ;
      RECT 499.665 1511.790 499.735 1512.000 ;
    END
  END r0_rd_out[338]
  PIN r0_rd_out[339]
    DIRECTION OUTPUT ;
    USE SIGNAL ;
    SHAPE ABUTMENT ;
    PORT
      LAYER metal2 ;
      RECT 505.745 1511.790 505.815 1512.000 ;
    END
  END r0_rd_out[339]
  PIN r0_rd_out[340]
    DIRECTION OUTPUT ;
    USE SIGNAL ;
    SHAPE ABUTMENT ;
    PORT
      LAYER metal2 ;
      RECT 511.825 1511.790 511.895 1512.000 ;
    END
  END r0_rd_out[340]
  PIN r0_rd_out[341]
    DIRECTION OUTPUT ;
    USE SIGNAL ;
    SHAPE ABUTMENT ;
    PORT
      LAYER metal2 ;
      RECT 517.905 1511.790 517.975 1512.000 ;
    END
  END r0_rd_out[341]
  PIN r0_rd_out[342]
    DIRECTION OUTPUT ;
    USE SIGNAL ;
    SHAPE ABUTMENT ;
    PORT
      LAYER metal2 ;
      RECT 523.985 1511.790 524.055 1512.000 ;
    END
  END r0_rd_out[342]
  PIN r0_rd_out[343]
    DIRECTION OUTPUT ;
    USE SIGNAL ;
    SHAPE ABUTMENT ;
    PORT
      LAYER metal2 ;
      RECT 530.065 1511.790 530.135 1512.000 ;
    END
  END r0_rd_out[343]
  PIN r0_rd_out[344]
    DIRECTION OUTPUT ;
    USE SIGNAL ;
    SHAPE ABUTMENT ;
    PORT
      LAYER metal2 ;
      RECT 536.145 1511.790 536.215 1512.000 ;
    END
  END r0_rd_out[344]
  PIN r0_rd_out[345]
    DIRECTION OUTPUT ;
    USE SIGNAL ;
    SHAPE ABUTMENT ;
    PORT
      LAYER metal2 ;
      RECT 542.225 1511.790 542.295 1512.000 ;
    END
  END r0_rd_out[345]
  PIN r0_rd_out[346]
    DIRECTION OUTPUT ;
    USE SIGNAL ;
    SHAPE ABUTMENT ;
    PORT
      LAYER metal2 ;
      RECT 548.305 1511.790 548.375 1512.000 ;
    END
  END r0_rd_out[346]
  PIN r0_rd_out[347]
    DIRECTION OUTPUT ;
    USE SIGNAL ;
    SHAPE ABUTMENT ;
    PORT
      LAYER metal2 ;
      RECT 554.385 1511.790 554.455 1512.000 ;
    END
  END r0_rd_out[347]
  PIN r0_rd_out[348]
    DIRECTION OUTPUT ;
    USE SIGNAL ;
    SHAPE ABUTMENT ;
    PORT
      LAYER metal2 ;
      RECT 560.465 1511.790 560.535 1512.000 ;
    END
  END r0_rd_out[348]
  PIN r0_rd_out[349]
    DIRECTION OUTPUT ;
    USE SIGNAL ;
    SHAPE ABUTMENT ;
    PORT
      LAYER metal2 ;
      RECT 566.545 1511.790 566.615 1512.000 ;
    END
  END r0_rd_out[349]
  PIN r0_rd_out[350]
    DIRECTION OUTPUT ;
    USE SIGNAL ;
    SHAPE ABUTMENT ;
    PORT
      LAYER metal2 ;
      RECT 572.625 1511.790 572.695 1512.000 ;
    END
  END r0_rd_out[350]
  PIN r0_rd_out[351]
    DIRECTION OUTPUT ;
    USE SIGNAL ;
    SHAPE ABUTMENT ;
    PORT
      LAYER metal2 ;
      RECT 578.705 1511.790 578.775 1512.000 ;
    END
  END r0_rd_out[351]
  PIN r0_rd_out[352]
    DIRECTION OUTPUT ;
    USE SIGNAL ;
    SHAPE ABUTMENT ;
    PORT
      LAYER metal2 ;
      RECT 584.785 1511.790 584.855 1512.000 ;
    END
  END r0_rd_out[352]
  PIN r0_rd_out[353]
    DIRECTION OUTPUT ;
    USE SIGNAL ;
    SHAPE ABUTMENT ;
    PORT
      LAYER metal2 ;
      RECT 590.865 1511.790 590.935 1512.000 ;
    END
  END r0_rd_out[353]
  PIN r0_rd_out[354]
    DIRECTION OUTPUT ;
    USE SIGNAL ;
    SHAPE ABUTMENT ;
    PORT
      LAYER metal2 ;
      RECT 596.945 1511.790 597.015 1512.000 ;
    END
  END r0_rd_out[354]
  PIN r0_rd_out[355]
    DIRECTION OUTPUT ;
    USE SIGNAL ;
    SHAPE ABUTMENT ;
    PORT
      LAYER metal2 ;
      RECT 603.025 1511.790 603.095 1512.000 ;
    END
  END r0_rd_out[355]
  PIN r0_rd_out[356]
    DIRECTION OUTPUT ;
    USE SIGNAL ;
    SHAPE ABUTMENT ;
    PORT
      LAYER metal2 ;
      RECT 609.105 1511.790 609.175 1512.000 ;
    END
  END r0_rd_out[356]
  PIN r0_rd_out[357]
    DIRECTION OUTPUT ;
    USE SIGNAL ;
    SHAPE ABUTMENT ;
    PORT
      LAYER metal2 ;
      RECT 615.185 1511.790 615.255 1512.000 ;
    END
  END r0_rd_out[357]
  PIN r0_rd_out[358]
    DIRECTION OUTPUT ;
    USE SIGNAL ;
    SHAPE ABUTMENT ;
    PORT
      LAYER metal2 ;
      RECT 621.265 1511.790 621.335 1512.000 ;
    END
  END r0_rd_out[358]
  PIN r0_rd_out[359]
    DIRECTION OUTPUT ;
    USE SIGNAL ;
    SHAPE ABUTMENT ;
    PORT
      LAYER metal2 ;
      RECT 627.345 1511.790 627.415 1512.000 ;
    END
  END r0_rd_out[359]
  PIN r0_rd_out[360]
    DIRECTION OUTPUT ;
    USE SIGNAL ;
    SHAPE ABUTMENT ;
    PORT
      LAYER metal2 ;
      RECT 633.425 1511.790 633.495 1512.000 ;
    END
  END r0_rd_out[360]
  PIN r0_rd_out[361]
    DIRECTION OUTPUT ;
    USE SIGNAL ;
    SHAPE ABUTMENT ;
    PORT
      LAYER metal2 ;
      RECT 639.505 1511.790 639.575 1512.000 ;
    END
  END r0_rd_out[361]
  PIN r0_rd_out[362]
    DIRECTION OUTPUT ;
    USE SIGNAL ;
    SHAPE ABUTMENT ;
    PORT
      LAYER metal2 ;
      RECT 645.585 1511.790 645.655 1512.000 ;
    END
  END r0_rd_out[362]
  PIN r0_rd_out[363]
    DIRECTION OUTPUT ;
    USE SIGNAL ;
    SHAPE ABUTMENT ;
    PORT
      LAYER metal2 ;
      RECT 651.665 1511.790 651.735 1512.000 ;
    END
  END r0_rd_out[363]
  PIN r0_rd_out[364]
    DIRECTION OUTPUT ;
    USE SIGNAL ;
    SHAPE ABUTMENT ;
    PORT
      LAYER metal2 ;
      RECT 657.745 1511.790 657.815 1512.000 ;
    END
  END r0_rd_out[364]
  PIN r0_rd_out[365]
    DIRECTION OUTPUT ;
    USE SIGNAL ;
    SHAPE ABUTMENT ;
    PORT
      LAYER metal2 ;
      RECT 663.825 1511.790 663.895 1512.000 ;
    END
  END r0_rd_out[365]
  PIN r0_rd_out[366]
    DIRECTION OUTPUT ;
    USE SIGNAL ;
    SHAPE ABUTMENT ;
    PORT
      LAYER metal2 ;
      RECT 669.905 1511.790 669.975 1512.000 ;
    END
  END r0_rd_out[366]
  PIN r0_rd_out[367]
    DIRECTION OUTPUT ;
    USE SIGNAL ;
    SHAPE ABUTMENT ;
    PORT
      LAYER metal2 ;
      RECT 675.985 1511.790 676.055 1512.000 ;
    END
  END r0_rd_out[367]
  PIN r0_rd_out[368]
    DIRECTION OUTPUT ;
    USE SIGNAL ;
    SHAPE ABUTMENT ;
    PORT
      LAYER metal2 ;
      RECT 682.065 1511.790 682.135 1512.000 ;
    END
  END r0_rd_out[368]
  PIN r0_rd_out[369]
    DIRECTION OUTPUT ;
    USE SIGNAL ;
    SHAPE ABUTMENT ;
    PORT
      LAYER metal2 ;
      RECT 688.145 1511.790 688.215 1512.000 ;
    END
  END r0_rd_out[369]
  PIN r0_rd_out[370]
    DIRECTION OUTPUT ;
    USE SIGNAL ;
    SHAPE ABUTMENT ;
    PORT
      LAYER metal2 ;
      RECT 694.225 1511.790 694.295 1512.000 ;
    END
  END r0_rd_out[370]
  PIN r0_rd_out[371]
    DIRECTION OUTPUT ;
    USE SIGNAL ;
    SHAPE ABUTMENT ;
    PORT
      LAYER metal2 ;
      RECT 700.305 1511.790 700.375 1512.000 ;
    END
  END r0_rd_out[371]
  PIN r0_rd_out[372]
    DIRECTION OUTPUT ;
    USE SIGNAL ;
    SHAPE ABUTMENT ;
    PORT
      LAYER metal2 ;
      RECT 706.385 1511.790 706.455 1512.000 ;
    END
  END r0_rd_out[372]
  PIN r0_rd_out[373]
    DIRECTION OUTPUT ;
    USE SIGNAL ;
    SHAPE ABUTMENT ;
    PORT
      LAYER metal2 ;
      RECT 712.465 1511.790 712.535 1512.000 ;
    END
  END r0_rd_out[373]
  PIN r0_rd_out[374]
    DIRECTION OUTPUT ;
    USE SIGNAL ;
    SHAPE ABUTMENT ;
    PORT
      LAYER metal2 ;
      RECT 718.545 1511.790 718.615 1512.000 ;
    END
  END r0_rd_out[374]
  PIN r0_rd_out[375]
    DIRECTION OUTPUT ;
    USE SIGNAL ;
    SHAPE ABUTMENT ;
    PORT
      LAYER metal2 ;
      RECT 724.625 1511.790 724.695 1512.000 ;
    END
  END r0_rd_out[375]
  PIN r0_rd_out[376]
    DIRECTION OUTPUT ;
    USE SIGNAL ;
    SHAPE ABUTMENT ;
    PORT
      LAYER metal2 ;
      RECT 730.705 1511.790 730.775 1512.000 ;
    END
  END r0_rd_out[376]
  PIN r0_rd_out[377]
    DIRECTION OUTPUT ;
    USE SIGNAL ;
    SHAPE ABUTMENT ;
    PORT
      LAYER metal2 ;
      RECT 736.785 1511.790 736.855 1512.000 ;
    END
  END r0_rd_out[377]
  PIN r0_rd_out[378]
    DIRECTION OUTPUT ;
    USE SIGNAL ;
    SHAPE ABUTMENT ;
    PORT
      LAYER metal2 ;
      RECT 742.865 1511.790 742.935 1512.000 ;
    END
  END r0_rd_out[378]
  PIN r0_rd_out[379]
    DIRECTION OUTPUT ;
    USE SIGNAL ;
    SHAPE ABUTMENT ;
    PORT
      LAYER metal2 ;
      RECT 748.945 1511.790 749.015 1512.000 ;
    END
  END r0_rd_out[379]
  PIN r0_rd_out[380]
    DIRECTION OUTPUT ;
    USE SIGNAL ;
    SHAPE ABUTMENT ;
    PORT
      LAYER metal2 ;
      RECT 755.025 1511.790 755.095 1512.000 ;
    END
  END r0_rd_out[380]
  PIN r0_rd_out[381]
    DIRECTION OUTPUT ;
    USE SIGNAL ;
    SHAPE ABUTMENT ;
    PORT
      LAYER metal2 ;
      RECT 761.105 1511.790 761.175 1512.000 ;
    END
  END r0_rd_out[381]
  PIN r0_rd_out[382]
    DIRECTION OUTPUT ;
    USE SIGNAL ;
    SHAPE ABUTMENT ;
    PORT
      LAYER metal2 ;
      RECT 767.185 1511.790 767.255 1512.000 ;
    END
  END r0_rd_out[382]
  PIN r0_rd_out[383]
    DIRECTION OUTPUT ;
    USE SIGNAL ;
    SHAPE ABUTMENT ;
    PORT
      LAYER metal2 ;
      RECT 773.265 1511.790 773.335 1512.000 ;
    END
  END r0_rd_out[383]
  PIN r0_rd_out[384]
    DIRECTION OUTPUT ;
    USE SIGNAL ;
    SHAPE ABUTMENT ;
    PORT
      LAYER metal2 ;
      RECT 779.345 1511.790 779.415 1512.000 ;
    END
  END r0_rd_out[384]
  PIN r0_rd_out[385]
    DIRECTION OUTPUT ;
    USE SIGNAL ;
    SHAPE ABUTMENT ;
    PORT
      LAYER metal2 ;
      RECT 785.425 1511.790 785.495 1512.000 ;
    END
  END r0_rd_out[385]
  PIN r0_rd_out[386]
    DIRECTION OUTPUT ;
    USE SIGNAL ;
    SHAPE ABUTMENT ;
    PORT
      LAYER metal2 ;
      RECT 791.505 1511.790 791.575 1512.000 ;
    END
  END r0_rd_out[386]
  PIN r0_rd_out[387]
    DIRECTION OUTPUT ;
    USE SIGNAL ;
    SHAPE ABUTMENT ;
    PORT
      LAYER metal2 ;
      RECT 797.585 1511.790 797.655 1512.000 ;
    END
  END r0_rd_out[387]
  PIN r0_rd_out[388]
    DIRECTION OUTPUT ;
    USE SIGNAL ;
    SHAPE ABUTMENT ;
    PORT
      LAYER metal2 ;
      RECT 803.665 1511.790 803.735 1512.000 ;
    END
  END r0_rd_out[388]
  PIN r0_rd_out[389]
    DIRECTION OUTPUT ;
    USE SIGNAL ;
    SHAPE ABUTMENT ;
    PORT
      LAYER metal2 ;
      RECT 809.745 1511.790 809.815 1512.000 ;
    END
  END r0_rd_out[389]
  PIN r0_rd_out[390]
    DIRECTION OUTPUT ;
    USE SIGNAL ;
    SHAPE ABUTMENT ;
    PORT
      LAYER metal2 ;
      RECT 815.825 1511.790 815.895 1512.000 ;
    END
  END r0_rd_out[390]
  PIN r0_rd_out[391]
    DIRECTION OUTPUT ;
    USE SIGNAL ;
    SHAPE ABUTMENT ;
    PORT
      LAYER metal2 ;
      RECT 821.905 1511.790 821.975 1512.000 ;
    END
  END r0_rd_out[391]
  PIN r0_rd_out[392]
    DIRECTION OUTPUT ;
    USE SIGNAL ;
    SHAPE ABUTMENT ;
    PORT
      LAYER metal2 ;
      RECT 827.985 1511.790 828.055 1512.000 ;
    END
  END r0_rd_out[392]
  PIN r0_rd_out[393]
    DIRECTION OUTPUT ;
    USE SIGNAL ;
    SHAPE ABUTMENT ;
    PORT
      LAYER metal2 ;
      RECT 834.065 1511.790 834.135 1512.000 ;
    END
  END r0_rd_out[393]
  PIN r0_rd_out[394]
    DIRECTION OUTPUT ;
    USE SIGNAL ;
    SHAPE ABUTMENT ;
    PORT
      LAYER metal2 ;
      RECT 840.145 1511.790 840.215 1512.000 ;
    END
  END r0_rd_out[394]
  PIN r0_rd_out[395]
    DIRECTION OUTPUT ;
    USE SIGNAL ;
    SHAPE ABUTMENT ;
    PORT
      LAYER metal2 ;
      RECT 846.225 1511.790 846.295 1512.000 ;
    END
  END r0_rd_out[395]
  PIN r0_rd_out[396]
    DIRECTION OUTPUT ;
    USE SIGNAL ;
    SHAPE ABUTMENT ;
    PORT
      LAYER metal2 ;
      RECT 852.305 1511.790 852.375 1512.000 ;
    END
  END r0_rd_out[396]
  PIN r0_rd_out[397]
    DIRECTION OUTPUT ;
    USE SIGNAL ;
    SHAPE ABUTMENT ;
    PORT
      LAYER metal2 ;
      RECT 858.385 1511.790 858.455 1512.000 ;
    END
  END r0_rd_out[397]
  PIN r0_rd_out[398]
    DIRECTION OUTPUT ;
    USE SIGNAL ;
    SHAPE ABUTMENT ;
    PORT
      LAYER metal2 ;
      RECT 864.465 1511.790 864.535 1512.000 ;
    END
  END r0_rd_out[398]
  PIN r0_rd_out[399]
    DIRECTION OUTPUT ;
    USE SIGNAL ;
    SHAPE ABUTMENT ;
    PORT
      LAYER metal2 ;
      RECT 870.545 1511.790 870.615 1512.000 ;
    END
  END r0_rd_out[399]
  PIN r0_rd_out[400]
    DIRECTION OUTPUT ;
    USE SIGNAL ;
    SHAPE ABUTMENT ;
    PORT
      LAYER metal2 ;
      RECT 876.625 1511.790 876.695 1512.000 ;
    END
  END r0_rd_out[400]
  PIN r0_rd_out[401]
    DIRECTION OUTPUT ;
    USE SIGNAL ;
    SHAPE ABUTMENT ;
    PORT
      LAYER metal2 ;
      RECT 882.705 1511.790 882.775 1512.000 ;
    END
  END r0_rd_out[401]
  PIN r0_rd_out[402]
    DIRECTION OUTPUT ;
    USE SIGNAL ;
    SHAPE ABUTMENT ;
    PORT
      LAYER metal2 ;
      RECT 888.785 1511.790 888.855 1512.000 ;
    END
  END r0_rd_out[402]
  PIN r0_rd_out[403]
    DIRECTION OUTPUT ;
    USE SIGNAL ;
    SHAPE ABUTMENT ;
    PORT
      LAYER metal2 ;
      RECT 894.865 1511.790 894.935 1512.000 ;
    END
  END r0_rd_out[403]
  PIN r0_rd_out[404]
    DIRECTION OUTPUT ;
    USE SIGNAL ;
    SHAPE ABUTMENT ;
    PORT
      LAYER metal2 ;
      RECT 900.945 1511.790 901.015 1512.000 ;
    END
  END r0_rd_out[404]
  PIN r0_rd_out[405]
    DIRECTION OUTPUT ;
    USE SIGNAL ;
    SHAPE ABUTMENT ;
    PORT
      LAYER metal2 ;
      RECT 907.025 1511.790 907.095 1512.000 ;
    END
  END r0_rd_out[405]
  PIN r0_rd_out[406]
    DIRECTION OUTPUT ;
    USE SIGNAL ;
    SHAPE ABUTMENT ;
    PORT
      LAYER metal2 ;
      RECT 913.105 1511.790 913.175 1512.000 ;
    END
  END r0_rd_out[406]
  PIN r0_rd_out[407]
    DIRECTION OUTPUT ;
    USE SIGNAL ;
    SHAPE ABUTMENT ;
    PORT
      LAYER metal2 ;
      RECT 919.185 1511.790 919.255 1512.000 ;
    END
  END r0_rd_out[407]
  PIN r0_rd_out[408]
    DIRECTION OUTPUT ;
    USE SIGNAL ;
    SHAPE ABUTMENT ;
    PORT
      LAYER metal2 ;
      RECT 925.265 1511.790 925.335 1512.000 ;
    END
  END r0_rd_out[408]
  PIN r0_rd_out[409]
    DIRECTION OUTPUT ;
    USE SIGNAL ;
    SHAPE ABUTMENT ;
    PORT
      LAYER metal2 ;
      RECT 931.345 1511.790 931.415 1512.000 ;
    END
  END r0_rd_out[409]
  PIN r0_rd_out[410]
    DIRECTION OUTPUT ;
    USE SIGNAL ;
    SHAPE ABUTMENT ;
    PORT
      LAYER metal2 ;
      RECT 937.425 1511.790 937.495 1512.000 ;
    END
  END r0_rd_out[410]
  PIN r0_rd_out[411]
    DIRECTION OUTPUT ;
    USE SIGNAL ;
    SHAPE ABUTMENT ;
    PORT
      LAYER metal2 ;
      RECT 943.505 1511.790 943.575 1512.000 ;
    END
  END r0_rd_out[411]
  PIN r0_rd_out[412]
    DIRECTION OUTPUT ;
    USE SIGNAL ;
    SHAPE ABUTMENT ;
    PORT
      LAYER metal2 ;
      RECT 949.585 1511.790 949.655 1512.000 ;
    END
  END r0_rd_out[412]
  PIN r0_rd_out[413]
    DIRECTION OUTPUT ;
    USE SIGNAL ;
    SHAPE ABUTMENT ;
    PORT
      LAYER metal2 ;
      RECT 955.665 1511.790 955.735 1512.000 ;
    END
  END r0_rd_out[413]
  PIN r0_rd_out[414]
    DIRECTION OUTPUT ;
    USE SIGNAL ;
    SHAPE ABUTMENT ;
    PORT
      LAYER metal2 ;
      RECT 961.745 1511.790 961.815 1512.000 ;
    END
  END r0_rd_out[414]
  PIN r0_rd_out[415]
    DIRECTION OUTPUT ;
    USE SIGNAL ;
    SHAPE ABUTMENT ;
    PORT
      LAYER metal2 ;
      RECT 967.825 1511.790 967.895 1512.000 ;
    END
  END r0_rd_out[415]
  PIN r0_rd_out[416]
    DIRECTION OUTPUT ;
    USE SIGNAL ;
    SHAPE ABUTMENT ;
    PORT
      LAYER metal2 ;
      RECT 973.905 1511.790 973.975 1512.000 ;
    END
  END r0_rd_out[416]
  PIN r0_rd_out[417]
    DIRECTION OUTPUT ;
    USE SIGNAL ;
    SHAPE ABUTMENT ;
    PORT
      LAYER metal2 ;
      RECT 979.985 1511.790 980.055 1512.000 ;
    END
  END r0_rd_out[417]
  PIN r0_rd_out[418]
    DIRECTION OUTPUT ;
    USE SIGNAL ;
    SHAPE ABUTMENT ;
    PORT
      LAYER metal2 ;
      RECT 986.065 1511.790 986.135 1512.000 ;
    END
  END r0_rd_out[418]
  PIN r0_rd_out[419]
    DIRECTION OUTPUT ;
    USE SIGNAL ;
    SHAPE ABUTMENT ;
    PORT
      LAYER metal2 ;
      RECT 992.145 1511.790 992.215 1512.000 ;
    END
  END r0_rd_out[419]
  PIN r0_rd_out[420]
    DIRECTION OUTPUT ;
    USE SIGNAL ;
    SHAPE ABUTMENT ;
    PORT
      LAYER metal2 ;
      RECT 998.225 1511.790 998.295 1512.000 ;
    END
  END r0_rd_out[420]
  PIN r0_rd_out[421]
    DIRECTION OUTPUT ;
    USE SIGNAL ;
    SHAPE ABUTMENT ;
    PORT
      LAYER metal2 ;
      RECT 1004.305 1511.790 1004.375 1512.000 ;
    END
  END r0_rd_out[421]
  PIN r0_rd_out[422]
    DIRECTION OUTPUT ;
    USE SIGNAL ;
    SHAPE ABUTMENT ;
    PORT
      LAYER metal2 ;
      RECT 1010.385 1511.790 1010.455 1512.000 ;
    END
  END r0_rd_out[422]
  PIN r0_rd_out[423]
    DIRECTION OUTPUT ;
    USE SIGNAL ;
    SHAPE ABUTMENT ;
    PORT
      LAYER metal2 ;
      RECT 1016.465 1511.790 1016.535 1512.000 ;
    END
  END r0_rd_out[423]
  PIN r0_rd_out[424]
    DIRECTION OUTPUT ;
    USE SIGNAL ;
    SHAPE ABUTMENT ;
    PORT
      LAYER metal2 ;
      RECT 1022.545 1511.790 1022.615 1512.000 ;
    END
  END r0_rd_out[424]
  PIN r0_rd_out[425]
    DIRECTION OUTPUT ;
    USE SIGNAL ;
    SHAPE ABUTMENT ;
    PORT
      LAYER metal2 ;
      RECT 1028.625 1511.790 1028.695 1512.000 ;
    END
  END r0_rd_out[425]
  PIN r0_rd_out[426]
    DIRECTION OUTPUT ;
    USE SIGNAL ;
    SHAPE ABUTMENT ;
    PORT
      LAYER metal2 ;
      RECT 1034.705 1511.790 1034.775 1512.000 ;
    END
  END r0_rd_out[426]
  PIN r0_rd_out[427]
    DIRECTION OUTPUT ;
    USE SIGNAL ;
    SHAPE ABUTMENT ;
    PORT
      LAYER metal2 ;
      RECT 1040.785 1511.790 1040.855 1512.000 ;
    END
  END r0_rd_out[427]
  PIN r0_rd_out[428]
    DIRECTION OUTPUT ;
    USE SIGNAL ;
    SHAPE ABUTMENT ;
    PORT
      LAYER metal2 ;
      RECT 1046.865 1511.790 1046.935 1512.000 ;
    END
  END r0_rd_out[428]
  PIN r0_rd_out[429]
    DIRECTION OUTPUT ;
    USE SIGNAL ;
    SHAPE ABUTMENT ;
    PORT
      LAYER metal2 ;
      RECT 1052.945 1511.790 1053.015 1512.000 ;
    END
  END r0_rd_out[429]
  PIN r0_rd_out[430]
    DIRECTION OUTPUT ;
    USE SIGNAL ;
    SHAPE ABUTMENT ;
    PORT
      LAYER metal2 ;
      RECT 1059.025 1511.790 1059.095 1512.000 ;
    END
  END r0_rd_out[430]
  PIN r0_rd_out[431]
    DIRECTION OUTPUT ;
    USE SIGNAL ;
    SHAPE ABUTMENT ;
    PORT
      LAYER metal2 ;
      RECT 1065.105 1511.790 1065.175 1512.000 ;
    END
  END r0_rd_out[431]
  PIN r0_rd_out[432]
    DIRECTION OUTPUT ;
    USE SIGNAL ;
    SHAPE ABUTMENT ;
    PORT
      LAYER metal2 ;
      RECT 1071.185 1511.790 1071.255 1512.000 ;
    END
  END r0_rd_out[432]
  PIN r0_rd_out[433]
    DIRECTION OUTPUT ;
    USE SIGNAL ;
    SHAPE ABUTMENT ;
    PORT
      LAYER metal2 ;
      RECT 1077.265 1511.790 1077.335 1512.000 ;
    END
  END r0_rd_out[433]
  PIN r0_rd_out[434]
    DIRECTION OUTPUT ;
    USE SIGNAL ;
    SHAPE ABUTMENT ;
    PORT
      LAYER metal2 ;
      RECT 1083.345 1511.790 1083.415 1512.000 ;
    END
  END r0_rd_out[434]
  PIN r0_rd_out[435]
    DIRECTION OUTPUT ;
    USE SIGNAL ;
    SHAPE ABUTMENT ;
    PORT
      LAYER metal2 ;
      RECT 1089.425 1511.790 1089.495 1512.000 ;
    END
  END r0_rd_out[435]
  PIN r0_rd_out[436]
    DIRECTION OUTPUT ;
    USE SIGNAL ;
    SHAPE ABUTMENT ;
    PORT
      LAYER metal2 ;
      RECT 1095.505 1511.790 1095.575 1512.000 ;
    END
  END r0_rd_out[436]
  PIN r0_rd_out[437]
    DIRECTION OUTPUT ;
    USE SIGNAL ;
    SHAPE ABUTMENT ;
    PORT
      LAYER metal2 ;
      RECT 1101.585 1511.790 1101.655 1512.000 ;
    END
  END r0_rd_out[437]
  PIN r0_rd_out[438]
    DIRECTION OUTPUT ;
    USE SIGNAL ;
    SHAPE ABUTMENT ;
    PORT
      LAYER metal2 ;
      RECT 1107.665 1511.790 1107.735 1512.000 ;
    END
  END r0_rd_out[438]
  PIN r0_rd_out[439]
    DIRECTION OUTPUT ;
    USE SIGNAL ;
    SHAPE ABUTMENT ;
    PORT
      LAYER metal2 ;
      RECT 1113.745 1511.790 1113.815 1512.000 ;
    END
  END r0_rd_out[439]
  PIN r0_rd_out[440]
    DIRECTION OUTPUT ;
    USE SIGNAL ;
    SHAPE ABUTMENT ;
    PORT
      LAYER metal2 ;
      RECT 1119.825 1511.790 1119.895 1512.000 ;
    END
  END r0_rd_out[440]
  PIN r0_rd_out[441]
    DIRECTION OUTPUT ;
    USE SIGNAL ;
    SHAPE ABUTMENT ;
    PORT
      LAYER metal2 ;
      RECT 1125.905 1511.790 1125.975 1512.000 ;
    END
  END r0_rd_out[441]
  PIN r0_rd_out[442]
    DIRECTION OUTPUT ;
    USE SIGNAL ;
    SHAPE ABUTMENT ;
    PORT
      LAYER metal2 ;
      RECT 1131.985 1511.790 1132.055 1512.000 ;
    END
  END r0_rd_out[442]
  PIN r0_rd_out[443]
    DIRECTION OUTPUT ;
    USE SIGNAL ;
    SHAPE ABUTMENT ;
    PORT
      LAYER metal2 ;
      RECT 1138.065 1511.790 1138.135 1512.000 ;
    END
  END r0_rd_out[443]
  PIN r0_rd_out[444]
    DIRECTION OUTPUT ;
    USE SIGNAL ;
    SHAPE ABUTMENT ;
    PORT
      LAYER metal2 ;
      RECT 1144.145 1511.790 1144.215 1512.000 ;
    END
  END r0_rd_out[444]
  PIN r0_rd_out[445]
    DIRECTION OUTPUT ;
    USE SIGNAL ;
    SHAPE ABUTMENT ;
    PORT
      LAYER metal2 ;
      RECT 1150.225 1511.790 1150.295 1512.000 ;
    END
  END r0_rd_out[445]
  PIN r0_rd_out[446]
    DIRECTION OUTPUT ;
    USE SIGNAL ;
    SHAPE ABUTMENT ;
    PORT
      LAYER metal2 ;
      RECT 1156.305 1511.790 1156.375 1512.000 ;
    END
  END r0_rd_out[446]
  PIN r0_rd_out[447]
    DIRECTION OUTPUT ;
    USE SIGNAL ;
    SHAPE ABUTMENT ;
    PORT
      LAYER metal2 ;
      RECT 1162.385 1511.790 1162.455 1512.000 ;
    END
  END r0_rd_out[447]
  PIN r0_rd_out[448]
    DIRECTION OUTPUT ;
    USE SIGNAL ;
    SHAPE ABUTMENT ;
    PORT
      LAYER metal2 ;
      RECT 1168.465 1511.790 1168.535 1512.000 ;
    END
  END r0_rd_out[448]
  PIN r0_rd_out[449]
    DIRECTION OUTPUT ;
    USE SIGNAL ;
    SHAPE ABUTMENT ;
    PORT
      LAYER metal2 ;
      RECT 1174.545 1511.790 1174.615 1512.000 ;
    END
  END r0_rd_out[449]
  PIN r0_rd_out[450]
    DIRECTION OUTPUT ;
    USE SIGNAL ;
    SHAPE ABUTMENT ;
    PORT
      LAYER metal2 ;
      RECT 1180.625 1511.790 1180.695 1512.000 ;
    END
  END r0_rd_out[450]
  PIN r0_rd_out[451]
    DIRECTION OUTPUT ;
    USE SIGNAL ;
    SHAPE ABUTMENT ;
    PORT
      LAYER metal2 ;
      RECT 1186.705 1511.790 1186.775 1512.000 ;
    END
  END r0_rd_out[451]
  PIN r0_rd_out[452]
    DIRECTION OUTPUT ;
    USE SIGNAL ;
    SHAPE ABUTMENT ;
    PORT
      LAYER metal2 ;
      RECT 1192.785 1511.790 1192.855 1512.000 ;
    END
  END r0_rd_out[452]
  PIN r0_rd_out[453]
    DIRECTION OUTPUT ;
    USE SIGNAL ;
    SHAPE ABUTMENT ;
    PORT
      LAYER metal2 ;
      RECT 1198.865 1511.790 1198.935 1512.000 ;
    END
  END r0_rd_out[453]
  PIN r0_rd_out[454]
    DIRECTION OUTPUT ;
    USE SIGNAL ;
    SHAPE ABUTMENT ;
    PORT
      LAYER metal2 ;
      RECT 1204.945 1511.790 1205.015 1512.000 ;
    END
  END r0_rd_out[454]
  PIN r0_rd_out[455]
    DIRECTION OUTPUT ;
    USE SIGNAL ;
    SHAPE ABUTMENT ;
    PORT
      LAYER metal2 ;
      RECT 1211.025 1511.790 1211.095 1512.000 ;
    END
  END r0_rd_out[455]
  PIN r0_rd_out[456]
    DIRECTION OUTPUT ;
    USE SIGNAL ;
    SHAPE ABUTMENT ;
    PORT
      LAYER metal2 ;
      RECT 1217.105 1511.790 1217.175 1512.000 ;
    END
  END r0_rd_out[456]
  PIN r0_rd_out[457]
    DIRECTION OUTPUT ;
    USE SIGNAL ;
    SHAPE ABUTMENT ;
    PORT
      LAYER metal2 ;
      RECT 1223.185 1511.790 1223.255 1512.000 ;
    END
  END r0_rd_out[457]
  PIN r0_rd_out[458]
    DIRECTION OUTPUT ;
    USE SIGNAL ;
    SHAPE ABUTMENT ;
    PORT
      LAYER metal2 ;
      RECT 1229.265 1511.790 1229.335 1512.000 ;
    END
  END r0_rd_out[458]
  PIN r0_rd_out[459]
    DIRECTION OUTPUT ;
    USE SIGNAL ;
    SHAPE ABUTMENT ;
    PORT
      LAYER metal2 ;
      RECT 1235.345 1511.790 1235.415 1512.000 ;
    END
  END r0_rd_out[459]
  PIN r0_rd_out[460]
    DIRECTION OUTPUT ;
    USE SIGNAL ;
    SHAPE ABUTMENT ;
    PORT
      LAYER metal2 ;
      RECT 1241.425 1511.790 1241.495 1512.000 ;
    END
  END r0_rd_out[460]
  PIN r0_rd_out[461]
    DIRECTION OUTPUT ;
    USE SIGNAL ;
    SHAPE ABUTMENT ;
    PORT
      LAYER metal2 ;
      RECT 1247.505 1511.790 1247.575 1512.000 ;
    END
  END r0_rd_out[461]
  PIN r0_rd_out[462]
    DIRECTION OUTPUT ;
    USE SIGNAL ;
    SHAPE ABUTMENT ;
    PORT
      LAYER metal2 ;
      RECT 1253.585 1511.790 1253.655 1512.000 ;
    END
  END r0_rd_out[462]
  PIN r0_rd_out[463]
    DIRECTION OUTPUT ;
    USE SIGNAL ;
    SHAPE ABUTMENT ;
    PORT
      LAYER metal2 ;
      RECT 1259.665 1511.790 1259.735 1512.000 ;
    END
  END r0_rd_out[463]
  PIN r0_rd_out[464]
    DIRECTION OUTPUT ;
    USE SIGNAL ;
    SHAPE ABUTMENT ;
    PORT
      LAYER metal2 ;
      RECT 1265.745 1511.790 1265.815 1512.000 ;
    END
  END r0_rd_out[464]
  PIN r0_rd_out[465]
    DIRECTION OUTPUT ;
    USE SIGNAL ;
    SHAPE ABUTMENT ;
    PORT
      LAYER metal2 ;
      RECT 1271.825 1511.790 1271.895 1512.000 ;
    END
  END r0_rd_out[465]
  PIN r0_rd_out[466]
    DIRECTION OUTPUT ;
    USE SIGNAL ;
    SHAPE ABUTMENT ;
    PORT
      LAYER metal2 ;
      RECT 1277.905 1511.790 1277.975 1512.000 ;
    END
  END r0_rd_out[466]
  PIN r0_rd_out[467]
    DIRECTION OUTPUT ;
    USE SIGNAL ;
    SHAPE ABUTMENT ;
    PORT
      LAYER metal2 ;
      RECT 1283.985 1511.790 1284.055 1512.000 ;
    END
  END r0_rd_out[467]
  PIN r0_rd_out[468]
    DIRECTION OUTPUT ;
    USE SIGNAL ;
    SHAPE ABUTMENT ;
    PORT
      LAYER metal2 ;
      RECT 1290.065 1511.790 1290.135 1512.000 ;
    END
  END r0_rd_out[468]
  PIN r0_rd_out[469]
    DIRECTION OUTPUT ;
    USE SIGNAL ;
    SHAPE ABUTMENT ;
    PORT
      LAYER metal2 ;
      RECT 1296.145 1511.790 1296.215 1512.000 ;
    END
  END r0_rd_out[469]
  PIN r0_rd_out[470]
    DIRECTION OUTPUT ;
    USE SIGNAL ;
    SHAPE ABUTMENT ;
    PORT
      LAYER metal2 ;
      RECT 1302.225 1511.790 1302.295 1512.000 ;
    END
  END r0_rd_out[470]
  PIN r0_rd_out[471]
    DIRECTION OUTPUT ;
    USE SIGNAL ;
    SHAPE ABUTMENT ;
    PORT
      LAYER metal2 ;
      RECT 1308.305 1511.790 1308.375 1512.000 ;
    END
  END r0_rd_out[471]
  PIN r0_rd_out[472]
    DIRECTION OUTPUT ;
    USE SIGNAL ;
    SHAPE ABUTMENT ;
    PORT
      LAYER metal2 ;
      RECT 1314.385 1511.790 1314.455 1512.000 ;
    END
  END r0_rd_out[472]
  PIN r0_rd_out[473]
    DIRECTION OUTPUT ;
    USE SIGNAL ;
    SHAPE ABUTMENT ;
    PORT
      LAYER metal2 ;
      RECT 1320.465 1511.790 1320.535 1512.000 ;
    END
  END r0_rd_out[473]
  PIN r0_rd_out[474]
    DIRECTION OUTPUT ;
    USE SIGNAL ;
    SHAPE ABUTMENT ;
    PORT
      LAYER metal2 ;
      RECT 1326.545 1511.790 1326.615 1512.000 ;
    END
  END r0_rd_out[474]
  PIN r0_rd_out[475]
    DIRECTION OUTPUT ;
    USE SIGNAL ;
    SHAPE ABUTMENT ;
    PORT
      LAYER metal2 ;
      RECT 1332.625 1511.790 1332.695 1512.000 ;
    END
  END r0_rd_out[475]
  PIN r0_rd_out[476]
    DIRECTION OUTPUT ;
    USE SIGNAL ;
    SHAPE ABUTMENT ;
    PORT
      LAYER metal2 ;
      RECT 1338.705 1511.790 1338.775 1512.000 ;
    END
  END r0_rd_out[476]
  PIN r0_rd_out[477]
    DIRECTION OUTPUT ;
    USE SIGNAL ;
    SHAPE ABUTMENT ;
    PORT
      LAYER metal2 ;
      RECT 1344.785 1511.790 1344.855 1512.000 ;
    END
  END r0_rd_out[477]
  PIN r0_rd_out[478]
    DIRECTION OUTPUT ;
    USE SIGNAL ;
    SHAPE ABUTMENT ;
    PORT
      LAYER metal2 ;
      RECT 1350.865 1511.790 1350.935 1512.000 ;
    END
  END r0_rd_out[478]
  PIN r0_rd_out[479]
    DIRECTION OUTPUT ;
    USE SIGNAL ;
    SHAPE ABUTMENT ;
    PORT
      LAYER metal2 ;
      RECT 1356.945 1511.790 1357.015 1512.000 ;
    END
  END r0_rd_out[479]
  PIN r0_rd_out[480]
    DIRECTION OUTPUT ;
    USE SIGNAL ;
    SHAPE ABUTMENT ;
    PORT
      LAYER metal2 ;
      RECT 1363.025 1511.790 1363.095 1512.000 ;
    END
  END r0_rd_out[480]
  PIN r0_rd_out[481]
    DIRECTION OUTPUT ;
    USE SIGNAL ;
    SHAPE ABUTMENT ;
    PORT
      LAYER metal2 ;
      RECT 1369.105 1511.790 1369.175 1512.000 ;
    END
  END r0_rd_out[481]
  PIN r0_rd_out[482]
    DIRECTION OUTPUT ;
    USE SIGNAL ;
    SHAPE ABUTMENT ;
    PORT
      LAYER metal2 ;
      RECT 1375.185 1511.790 1375.255 1512.000 ;
    END
  END r0_rd_out[482]
  PIN r0_rd_out[483]
    DIRECTION OUTPUT ;
    USE SIGNAL ;
    SHAPE ABUTMENT ;
    PORT
      LAYER metal2 ;
      RECT 1381.265 1511.790 1381.335 1512.000 ;
    END
  END r0_rd_out[483]
  PIN r0_rd_out[484]
    DIRECTION OUTPUT ;
    USE SIGNAL ;
    SHAPE ABUTMENT ;
    PORT
      LAYER metal2 ;
      RECT 1387.345 1511.790 1387.415 1512.000 ;
    END
  END r0_rd_out[484]
  PIN r0_rd_out[485]
    DIRECTION OUTPUT ;
    USE SIGNAL ;
    SHAPE ABUTMENT ;
    PORT
      LAYER metal2 ;
      RECT 1393.425 1511.790 1393.495 1512.000 ;
    END
  END r0_rd_out[485]
  PIN r0_rd_out[486]
    DIRECTION OUTPUT ;
    USE SIGNAL ;
    SHAPE ABUTMENT ;
    PORT
      LAYER metal2 ;
      RECT 1399.505 1511.790 1399.575 1512.000 ;
    END
  END r0_rd_out[486]
  PIN r0_rd_out[487]
    DIRECTION OUTPUT ;
    USE SIGNAL ;
    SHAPE ABUTMENT ;
    PORT
      LAYER metal2 ;
      RECT 1405.585 1511.790 1405.655 1512.000 ;
    END
  END r0_rd_out[487]
  PIN r0_rd_out[488]
    DIRECTION OUTPUT ;
    USE SIGNAL ;
    SHAPE ABUTMENT ;
    PORT
      LAYER metal2 ;
      RECT 1411.665 1511.790 1411.735 1512.000 ;
    END
  END r0_rd_out[488]
  PIN r0_rd_out[489]
    DIRECTION OUTPUT ;
    USE SIGNAL ;
    SHAPE ABUTMENT ;
    PORT
      LAYER metal2 ;
      RECT 1417.745 1511.790 1417.815 1512.000 ;
    END
  END r0_rd_out[489]
  PIN r0_rd_out[490]
    DIRECTION OUTPUT ;
    USE SIGNAL ;
    SHAPE ABUTMENT ;
    PORT
      LAYER metal2 ;
      RECT 1423.825 1511.790 1423.895 1512.000 ;
    END
  END r0_rd_out[490]
  PIN r0_rd_out[491]
    DIRECTION OUTPUT ;
    USE SIGNAL ;
    SHAPE ABUTMENT ;
    PORT
      LAYER metal2 ;
      RECT 1429.905 1511.790 1429.975 1512.000 ;
    END
  END r0_rd_out[491]
  PIN r0_rd_out[492]
    DIRECTION OUTPUT ;
    USE SIGNAL ;
    SHAPE ABUTMENT ;
    PORT
      LAYER metal2 ;
      RECT 1435.985 1511.790 1436.055 1512.000 ;
    END
  END r0_rd_out[492]
  PIN r0_rd_out[493]
    DIRECTION OUTPUT ;
    USE SIGNAL ;
    SHAPE ABUTMENT ;
    PORT
      LAYER metal2 ;
      RECT 1442.065 1511.790 1442.135 1512.000 ;
    END
  END r0_rd_out[493]
  PIN r0_rd_out[494]
    DIRECTION OUTPUT ;
    USE SIGNAL ;
    SHAPE ABUTMENT ;
    PORT
      LAYER metal2 ;
      RECT 1448.145 1511.790 1448.215 1512.000 ;
    END
  END r0_rd_out[494]
  PIN r0_rd_out[495]
    DIRECTION OUTPUT ;
    USE SIGNAL ;
    SHAPE ABUTMENT ;
    PORT
      LAYER metal2 ;
      RECT 1454.225 1511.790 1454.295 1512.000 ;
    END
  END r0_rd_out[495]
  PIN r0_rd_out[496]
    DIRECTION OUTPUT ;
    USE SIGNAL ;
    SHAPE ABUTMENT ;
    PORT
      LAYER metal2 ;
      RECT 1460.305 1511.790 1460.375 1512.000 ;
    END
  END r0_rd_out[496]
  PIN r0_rd_out[497]
    DIRECTION OUTPUT ;
    USE SIGNAL ;
    SHAPE ABUTMENT ;
    PORT
      LAYER metal2 ;
      RECT 1466.385 1511.790 1466.455 1512.000 ;
    END
  END r0_rd_out[497]
  PIN r0_rd_out[498]
    DIRECTION OUTPUT ;
    USE SIGNAL ;
    SHAPE ABUTMENT ;
    PORT
      LAYER metal2 ;
      RECT 1472.465 1511.790 1472.535 1512.000 ;
    END
  END r0_rd_out[498]
  PIN r0_rd_out[499]
    DIRECTION OUTPUT ;
    USE SIGNAL ;
    SHAPE ABUTMENT ;
    PORT
      LAYER metal2 ;
      RECT 1478.545 1511.790 1478.615 1512.000 ;
    END
  END r0_rd_out[499]
  PIN r0_rd_out[500]
    DIRECTION OUTPUT ;
    USE SIGNAL ;
    SHAPE ABUTMENT ;
    PORT
      LAYER metal2 ;
      RECT 1484.625 1511.790 1484.695 1512.000 ;
    END
  END r0_rd_out[500]
  PIN r0_rd_out[501]
    DIRECTION OUTPUT ;
    USE SIGNAL ;
    SHAPE ABUTMENT ;
    PORT
      LAYER metal2 ;
      RECT 1490.705 1511.790 1490.775 1512.000 ;
    END
  END r0_rd_out[501]
  PIN r0_rd_out[502]
    DIRECTION OUTPUT ;
    USE SIGNAL ;
    SHAPE ABUTMENT ;
    PORT
      LAYER metal2 ;
      RECT 1496.785 1511.790 1496.855 1512.000 ;
    END
  END r0_rd_out[502]
  PIN r0_rd_out[503]
    DIRECTION OUTPUT ;
    USE SIGNAL ;
    SHAPE ABUTMENT ;
    PORT
      LAYER metal2 ;
      RECT 1502.865 1511.790 1502.935 1512.000 ;
    END
  END r0_rd_out[503]
  PIN r0_rd_out[504]
    DIRECTION OUTPUT ;
    USE SIGNAL ;
    SHAPE ABUTMENT ;
    PORT
      LAYER metal2 ;
      RECT 1508.945 1511.790 1509.015 1512.000 ;
    END
  END r0_rd_out[504]
  PIN r0_rd_out[505]
    DIRECTION OUTPUT ;
    USE SIGNAL ;
    SHAPE ABUTMENT ;
    PORT
      LAYER metal2 ;
      RECT 1515.025 1511.790 1515.095 1512.000 ;
    END
  END r0_rd_out[505]
  PIN r0_rd_out[506]
    DIRECTION OUTPUT ;
    USE SIGNAL ;
    SHAPE ABUTMENT ;
    PORT
      LAYER metal2 ;
      RECT 1521.105 1511.790 1521.175 1512.000 ;
    END
  END r0_rd_out[506]
  PIN r0_rd_out[507]
    DIRECTION OUTPUT ;
    USE SIGNAL ;
    SHAPE ABUTMENT ;
    PORT
      LAYER metal2 ;
      RECT 1527.185 1511.790 1527.255 1512.000 ;
    END
  END r0_rd_out[507]
  PIN r0_rd_out[508]
    DIRECTION OUTPUT ;
    USE SIGNAL ;
    SHAPE ABUTMENT ;
    PORT
      LAYER metal2 ;
      RECT 1533.265 1511.790 1533.335 1512.000 ;
    END
  END r0_rd_out[508]
  PIN r0_rd_out[509]
    DIRECTION OUTPUT ;
    USE SIGNAL ;
    SHAPE ABUTMENT ;
    PORT
      LAYER metal2 ;
      RECT 1539.345 1511.790 1539.415 1512.000 ;
    END
  END r0_rd_out[509]
  PIN r0_rd_out[510]
    DIRECTION OUTPUT ;
    USE SIGNAL ;
    SHAPE ABUTMENT ;
    PORT
      LAYER metal2 ;
      RECT 1545.425 1511.790 1545.495 1512.000 ;
    END
  END r0_rd_out[510]
  PIN r0_rd_out[511]
    DIRECTION OUTPUT ;
    USE SIGNAL ;
    SHAPE ABUTMENT ;
    PORT
      LAYER metal2 ;
      RECT 1551.505 1511.790 1551.575 1512.000 ;
    END
  END r0_rd_out[511]
  PIN w0_addr_in[0]
    DIRECTION INPUT ;
    USE SIGNAL ;
    SHAPE ABUTMENT ;
    PORT
      LAYER metal3 ;
      RECT 0.000 1380.645 0.210 1380.715 ;
    END
  END w0_addr_in[0]
  PIN w0_addr_in[1]
    DIRECTION INPUT ;
    USE SIGNAL ;
    SHAPE ABUTMENT ;
    PORT
      LAYER metal3 ;
      RECT 0.000 1391.425 0.210 1391.495 ;
    END
  END w0_addr_in[1]
  PIN w0_addr_in[2]
    DIRECTION INPUT ;
    USE SIGNAL ;
    SHAPE ABUTMENT ;
    PORT
      LAYER metal3 ;
      RECT 0.000 1402.205 0.210 1402.275 ;
    END
  END w0_addr_in[2]
  PIN w0_addr_in[3]
    DIRECTION INPUT ;
    USE SIGNAL ;
    SHAPE ABUTMENT ;
    PORT
      LAYER metal3 ;
      RECT 0.000 1412.985 0.210 1413.055 ;
    END
  END w0_addr_in[3]
  PIN w0_addr_in[4]
    DIRECTION INPUT ;
    USE SIGNAL ;
    SHAPE ABUTMENT ;
    PORT
      LAYER metal3 ;
      RECT 0.000 1423.765 0.210 1423.835 ;
    END
  END w0_addr_in[4]
  PIN w0_addr_in[5]
    DIRECTION INPUT ;
    USE SIGNAL ;
    SHAPE ABUTMENT ;
    PORT
      LAYER metal3 ;
      RECT 0.000 1434.545 0.210 1434.615 ;
    END
  END w0_addr_in[5]
  PIN w0_addr_in[6]
    DIRECTION INPUT ;
    USE SIGNAL ;
    SHAPE ABUTMENT ;
    PORT
      LAYER metal3 ;
      RECT 1609.090 1380.645 1609.300 1380.715 ;
    END
  END w0_addr_in[6]
  PIN w0_addr_in[7]
    DIRECTION INPUT ;
    USE SIGNAL ;
    SHAPE ABUTMENT ;
    PORT
      LAYER metal3 ;
      RECT 1609.090 1391.425 1609.300 1391.495 ;
    END
  END w0_addr_in[7]
  PIN w0_addr_in[8]
    DIRECTION INPUT ;
    USE SIGNAL ;
    SHAPE ABUTMENT ;
    PORT
      LAYER metal3 ;
      RECT 1609.090 1402.205 1609.300 1402.275 ;
    END
  END w0_addr_in[8]
  PIN w0_addr_in[9]
    DIRECTION INPUT ;
    USE SIGNAL ;
    SHAPE ABUTMENT ;
    PORT
      LAYER metal3 ;
      RECT 1609.090 1412.985 1609.300 1413.055 ;
    END
  END w0_addr_in[9]
  PIN w0_addr_in[10]
    DIRECTION INPUT ;
    USE SIGNAL ;
    SHAPE ABUTMENT ;
    PORT
      LAYER metal3 ;
      RECT 1609.090 1423.765 1609.300 1423.835 ;
    END
  END w0_addr_in[10]
  PIN r0_addr_in[0]
    DIRECTION INPUT ;
    USE SIGNAL ;
    SHAPE ABUTMENT ;
    PORT
      LAYER metal3 ;
      RECT 0.000 1445.325 0.210 1445.395 ;
    END
  END r0_addr_in[0]
  PIN r0_addr_in[1]
    DIRECTION INPUT ;
    USE SIGNAL ;
    SHAPE ABUTMENT ;
    PORT
      LAYER metal3 ;
      RECT 0.000 1456.105 0.210 1456.175 ;
    END
  END r0_addr_in[1]
  PIN r0_addr_in[2]
    DIRECTION INPUT ;
    USE SIGNAL ;
    SHAPE ABUTMENT ;
    PORT
      LAYER metal3 ;
      RECT 0.000 1466.885 0.210 1466.955 ;
    END
  END r0_addr_in[2]
  PIN r0_addr_in[3]
    DIRECTION INPUT ;
    USE SIGNAL ;
    SHAPE ABUTMENT ;
    PORT
      LAYER metal3 ;
      RECT 0.000 1477.665 0.210 1477.735 ;
    END
  END r0_addr_in[3]
  PIN r0_addr_in[4]
    DIRECTION INPUT ;
    USE SIGNAL ;
    SHAPE ABUTMENT ;
    PORT
      LAYER metal3 ;
      RECT 0.000 1488.445 0.210 1488.515 ;
    END
  END r0_addr_in[4]
  PIN r0_addr_in[5]
    DIRECTION INPUT ;
    USE SIGNAL ;
    SHAPE ABUTMENT ;
    PORT
      LAYER metal3 ;
      RECT 0.000 1499.225 0.210 1499.295 ;
    END
  END r0_addr_in[5]
  PIN r0_addr_in[6]
    DIRECTION INPUT ;
    USE SIGNAL ;
    SHAPE ABUTMENT ;
    PORT
      LAYER metal3 ;
      RECT 1609.090 1434.545 1609.300 1434.615 ;
    END
  END r0_addr_in[6]
  PIN r0_addr_in[7]
    DIRECTION INPUT ;
    USE SIGNAL ;
    SHAPE ABUTMENT ;
    PORT
      LAYER metal3 ;
      RECT 1609.090 1445.325 1609.300 1445.395 ;
    END
  END r0_addr_in[7]
  PIN r0_addr_in[8]
    DIRECTION INPUT ;
    USE SIGNAL ;
    SHAPE ABUTMENT ;
    PORT
      LAYER metal3 ;
      RECT 1609.090 1456.105 1609.300 1456.175 ;
    END
  END r0_addr_in[8]
  PIN r0_addr_in[9]
    DIRECTION INPUT ;
    USE SIGNAL ;
    SHAPE ABUTMENT ;
    PORT
      LAYER metal3 ;
      RECT 1609.090 1466.885 1609.300 1466.955 ;
    END
  END r0_addr_in[9]
  PIN r0_addr_in[10]
    DIRECTION INPUT ;
    USE SIGNAL ;
    SHAPE ABUTMENT ;
    PORT
      LAYER metal3 ;
      RECT 1609.090 1477.665 1609.300 1477.735 ;
    END
  END r0_addr_in[10]
  PIN w0_we_in
    DIRECTION INPUT ;
    USE SIGNAL ;
    SHAPE ABUTMENT ;
    PORT
      LAYER metal2 ;
      RECT 1557.585 1511.790 1557.655 1512.000 ;
    END
  END w0_we_in
  PIN w0_ce_in
    DIRECTION INPUT ;
    USE SIGNAL ;
    SHAPE ABUTMENT ;
    PORT
      LAYER metal2 ;
      RECT 1563.665 1511.790 1563.735 1512.000 ;
    END
  END w0_ce_in
  PIN w0_clk
    DIRECTION INPUT ;
    USE SIGNAL ;
    SHAPE ABUTMENT ;
    PORT
      LAYER metal2 ;
      RECT 1569.745 1511.790 1569.815 1512.000 ;
    END
  END w0_clk
  PIN r0_ce_in
    DIRECTION INPUT ;
    USE SIGNAL ;
    SHAPE ABUTMENT ;
    PORT
      LAYER metal2 ;
      RECT 1575.825 1511.790 1575.895 1512.000 ;
    END
  END r0_ce_in
  PIN r0_clk
    DIRECTION INPUT ;
    USE SIGNAL ;
    SHAPE ABUTMENT ;
    PORT
      LAYER metal2 ;
      RECT 1581.905 1511.790 1581.975 1512.000 ;
    END
  END r0_clk
  PIN VSS
    DIRECTION INOUT ;
    USE GROUND ;
    PORT
      LAYER metal4 ;
      RECT 1.000 0.840 1.280 1511.160 ;
      RECT 3.240 0.840 3.520 1511.160 ;
      RECT 5.480 0.840 5.760 1511.160 ;
      RECT 7.720 0.840 8.000 1511.160 ;
      RECT 9.960 0.840 10.240 1511.160 ;
      RECT 12.200 0.840 12.480 1511.160 ;
      RECT 14.440 0.840 14.720 1511.160 ;
      RECT 16.680 0.840 16.960 1511.160 ;
      RECT 18.920 0.840 19.200 1511.160 ;
      RECT 21.160 0.840 21.440 1511.160 ;
      RECT 23.400 0.840 23.680 1511.160 ;
      RECT 25.640 0.840 25.920 1511.160 ;
      RECT 27.880 0.840 28.160 1511.160 ;
      RECT 30.120 0.840 30.400 1511.160 ;
      RECT 32.360 0.840 32.640 1511.160 ;
      RECT 34.600 0.840 34.880 1511.160 ;
      RECT 36.840 0.840 37.120 1511.160 ;
      RECT 39.080 0.840 39.360 1511.160 ;
      RECT 41.320 0.840 41.600 1511.160 ;
      RECT 43.560 0.840 43.840 1511.160 ;
      RECT 45.800 0.840 46.080 1511.160 ;
      RECT 48.040 0.840 48.320 1511.160 ;
      RECT 50.280 0.840 50.560 1511.160 ;
      RECT 52.520 0.840 52.800 1511.160 ;
      RECT 54.760 0.840 55.040 1511.160 ;
      RECT 57.000 0.840 57.280 1511.160 ;
      RECT 59.240 0.840 59.520 1511.160 ;
      RECT 61.480 0.840 61.760 1511.160 ;
      RECT 63.720 0.840 64.000 1511.160 ;
      RECT 65.960 0.840 66.240 1511.160 ;
      RECT 68.200 0.840 68.480 1511.160 ;
      RECT 70.440 0.840 70.720 1511.160 ;
      RECT 72.680 0.840 72.960 1511.160 ;
      RECT 74.920 0.840 75.200 1511.160 ;
      RECT 77.160 0.840 77.440 1511.160 ;
      RECT 79.400 0.840 79.680 1511.160 ;
      RECT 81.640 0.840 81.920 1511.160 ;
      RECT 83.880 0.840 84.160 1511.160 ;
      RECT 86.120 0.840 86.400 1511.160 ;
      RECT 88.360 0.840 88.640 1511.160 ;
      RECT 90.600 0.840 90.880 1511.160 ;
      RECT 92.840 0.840 93.120 1511.160 ;
      RECT 95.080 0.840 95.360 1511.160 ;
      RECT 97.320 0.840 97.600 1511.160 ;
      RECT 99.560 0.840 99.840 1511.160 ;
      RECT 101.800 0.840 102.080 1511.160 ;
      RECT 104.040 0.840 104.320 1511.160 ;
      RECT 106.280 0.840 106.560 1511.160 ;
      RECT 108.520 0.840 108.800 1511.160 ;
      RECT 110.760 0.840 111.040 1511.160 ;
      RECT 113.000 0.840 113.280 1511.160 ;
      RECT 115.240 0.840 115.520 1511.160 ;
      RECT 117.480 0.840 117.760 1511.160 ;
      RECT 119.720 0.840 120.000 1511.160 ;
      RECT 121.960 0.840 122.240 1511.160 ;
      RECT 124.200 0.840 124.480 1511.160 ;
      RECT 126.440 0.840 126.720 1511.160 ;
      RECT 128.680 0.840 128.960 1511.160 ;
      RECT 130.920 0.840 131.200 1511.160 ;
      RECT 133.160 0.840 133.440 1511.160 ;
      RECT 135.400 0.840 135.680 1511.160 ;
      RECT 137.640 0.840 137.920 1511.160 ;
      RECT 139.880 0.840 140.160 1511.160 ;
      RECT 142.120 0.840 142.400 1511.160 ;
      RECT 144.360 0.840 144.640 1511.160 ;
      RECT 146.600 0.840 146.880 1511.160 ;
      RECT 148.840 0.840 149.120 1511.160 ;
      RECT 151.080 0.840 151.360 1511.160 ;
      RECT 153.320 0.840 153.600 1511.160 ;
      RECT 155.560 0.840 155.840 1511.160 ;
      RECT 157.800 0.840 158.080 1511.160 ;
      RECT 160.040 0.840 160.320 1511.160 ;
      RECT 162.280 0.840 162.560 1511.160 ;
      RECT 164.520 0.840 164.800 1511.160 ;
      RECT 166.760 0.840 167.040 1511.160 ;
      RECT 169.000 0.840 169.280 1511.160 ;
      RECT 171.240 0.840 171.520 1511.160 ;
      RECT 173.480 0.840 173.760 1511.160 ;
      RECT 175.720 0.840 176.000 1511.160 ;
      RECT 177.960 0.840 178.240 1511.160 ;
      RECT 180.200 0.840 180.480 1511.160 ;
      RECT 182.440 0.840 182.720 1511.160 ;
      RECT 184.680 0.840 184.960 1511.160 ;
      RECT 186.920 0.840 187.200 1511.160 ;
      RECT 189.160 0.840 189.440 1511.160 ;
      RECT 191.400 0.840 191.680 1511.160 ;
      RECT 193.640 0.840 193.920 1511.160 ;
      RECT 195.880 0.840 196.160 1511.160 ;
      RECT 198.120 0.840 198.400 1511.160 ;
      RECT 200.360 0.840 200.640 1511.160 ;
      RECT 202.600 0.840 202.880 1511.160 ;
      RECT 204.840 0.840 205.120 1511.160 ;
      RECT 207.080 0.840 207.360 1511.160 ;
      RECT 209.320 0.840 209.600 1511.160 ;
      RECT 211.560 0.840 211.840 1511.160 ;
      RECT 213.800 0.840 214.080 1511.160 ;
      RECT 216.040 0.840 216.320 1511.160 ;
      RECT 218.280 0.840 218.560 1511.160 ;
      RECT 220.520 0.840 220.800 1511.160 ;
      RECT 222.760 0.840 223.040 1511.160 ;
      RECT 225.000 0.840 225.280 1511.160 ;
      RECT 227.240 0.840 227.520 1511.160 ;
      RECT 229.480 0.840 229.760 1511.160 ;
      RECT 231.720 0.840 232.000 1511.160 ;
      RECT 233.960 0.840 234.240 1511.160 ;
      RECT 236.200 0.840 236.480 1511.160 ;
      RECT 238.440 0.840 238.720 1511.160 ;
      RECT 240.680 0.840 240.960 1511.160 ;
      RECT 242.920 0.840 243.200 1511.160 ;
      RECT 245.160 0.840 245.440 1511.160 ;
      RECT 247.400 0.840 247.680 1511.160 ;
      RECT 249.640 0.840 249.920 1511.160 ;
      RECT 251.880 0.840 252.160 1511.160 ;
      RECT 254.120 0.840 254.400 1511.160 ;
      RECT 256.360 0.840 256.640 1511.160 ;
      RECT 258.600 0.840 258.880 1511.160 ;
      RECT 260.840 0.840 261.120 1511.160 ;
      RECT 263.080 0.840 263.360 1511.160 ;
      RECT 265.320 0.840 265.600 1511.160 ;
      RECT 267.560 0.840 267.840 1511.160 ;
      RECT 269.800 0.840 270.080 1511.160 ;
      RECT 272.040 0.840 272.320 1511.160 ;
      RECT 274.280 0.840 274.560 1511.160 ;
      RECT 276.520 0.840 276.800 1511.160 ;
      RECT 278.760 0.840 279.040 1511.160 ;
      RECT 281.000 0.840 281.280 1511.160 ;
      RECT 283.240 0.840 283.520 1511.160 ;
      RECT 285.480 0.840 285.760 1511.160 ;
      RECT 287.720 0.840 288.000 1511.160 ;
      RECT 289.960 0.840 290.240 1511.160 ;
      RECT 292.200 0.840 292.480 1511.160 ;
      RECT 294.440 0.840 294.720 1511.160 ;
      RECT 296.680 0.840 296.960 1511.160 ;
      RECT 298.920 0.840 299.200 1511.160 ;
      RECT 301.160 0.840 301.440 1511.160 ;
      RECT 303.400 0.840 303.680 1511.160 ;
      RECT 305.640 0.840 305.920 1511.160 ;
      RECT 307.880 0.840 308.160 1511.160 ;
      RECT 310.120 0.840 310.400 1511.160 ;
      RECT 312.360 0.840 312.640 1511.160 ;
      RECT 314.600 0.840 314.880 1511.160 ;
      RECT 316.840 0.840 317.120 1511.160 ;
      RECT 319.080 0.840 319.360 1511.160 ;
      RECT 321.320 0.840 321.600 1511.160 ;
      RECT 323.560 0.840 323.840 1511.160 ;
      RECT 325.800 0.840 326.080 1511.160 ;
      RECT 328.040 0.840 328.320 1511.160 ;
      RECT 330.280 0.840 330.560 1511.160 ;
      RECT 332.520 0.840 332.800 1511.160 ;
      RECT 334.760 0.840 335.040 1511.160 ;
      RECT 337.000 0.840 337.280 1511.160 ;
      RECT 339.240 0.840 339.520 1511.160 ;
      RECT 341.480 0.840 341.760 1511.160 ;
      RECT 343.720 0.840 344.000 1511.160 ;
      RECT 345.960 0.840 346.240 1511.160 ;
      RECT 348.200 0.840 348.480 1511.160 ;
      RECT 350.440 0.840 350.720 1511.160 ;
      RECT 352.680 0.840 352.960 1511.160 ;
      RECT 354.920 0.840 355.200 1511.160 ;
      RECT 357.160 0.840 357.440 1511.160 ;
      RECT 359.400 0.840 359.680 1511.160 ;
      RECT 361.640 0.840 361.920 1511.160 ;
      RECT 363.880 0.840 364.160 1511.160 ;
      RECT 366.120 0.840 366.400 1511.160 ;
      RECT 368.360 0.840 368.640 1511.160 ;
      RECT 370.600 0.840 370.880 1511.160 ;
      RECT 372.840 0.840 373.120 1511.160 ;
      RECT 375.080 0.840 375.360 1511.160 ;
      RECT 377.320 0.840 377.600 1511.160 ;
      RECT 379.560 0.840 379.840 1511.160 ;
      RECT 381.800 0.840 382.080 1511.160 ;
      RECT 384.040 0.840 384.320 1511.160 ;
      RECT 386.280 0.840 386.560 1511.160 ;
      RECT 388.520 0.840 388.800 1511.160 ;
      RECT 390.760 0.840 391.040 1511.160 ;
      RECT 393.000 0.840 393.280 1511.160 ;
      RECT 395.240 0.840 395.520 1511.160 ;
      RECT 397.480 0.840 397.760 1511.160 ;
      RECT 399.720 0.840 400.000 1511.160 ;
      RECT 401.960 0.840 402.240 1511.160 ;
      RECT 404.200 0.840 404.480 1511.160 ;
      RECT 406.440 0.840 406.720 1511.160 ;
      RECT 408.680 0.840 408.960 1511.160 ;
      RECT 410.920 0.840 411.200 1511.160 ;
      RECT 413.160 0.840 413.440 1511.160 ;
      RECT 415.400 0.840 415.680 1511.160 ;
      RECT 417.640 0.840 417.920 1511.160 ;
      RECT 419.880 0.840 420.160 1511.160 ;
      RECT 422.120 0.840 422.400 1511.160 ;
      RECT 424.360 0.840 424.640 1511.160 ;
      RECT 426.600 0.840 426.880 1511.160 ;
      RECT 428.840 0.840 429.120 1511.160 ;
      RECT 431.080 0.840 431.360 1511.160 ;
      RECT 433.320 0.840 433.600 1511.160 ;
      RECT 435.560 0.840 435.840 1511.160 ;
      RECT 437.800 0.840 438.080 1511.160 ;
      RECT 440.040 0.840 440.320 1511.160 ;
      RECT 442.280 0.840 442.560 1511.160 ;
      RECT 444.520 0.840 444.800 1511.160 ;
      RECT 446.760 0.840 447.040 1511.160 ;
      RECT 449.000 0.840 449.280 1511.160 ;
      RECT 451.240 0.840 451.520 1511.160 ;
      RECT 453.480 0.840 453.760 1511.160 ;
      RECT 455.720 0.840 456.000 1511.160 ;
      RECT 457.960 0.840 458.240 1511.160 ;
      RECT 460.200 0.840 460.480 1511.160 ;
      RECT 462.440 0.840 462.720 1511.160 ;
      RECT 464.680 0.840 464.960 1511.160 ;
      RECT 466.920 0.840 467.200 1511.160 ;
      RECT 469.160 0.840 469.440 1511.160 ;
      RECT 471.400 0.840 471.680 1511.160 ;
      RECT 473.640 0.840 473.920 1511.160 ;
      RECT 475.880 0.840 476.160 1511.160 ;
      RECT 478.120 0.840 478.400 1511.160 ;
      RECT 480.360 0.840 480.640 1511.160 ;
      RECT 482.600 0.840 482.880 1511.160 ;
      RECT 484.840 0.840 485.120 1511.160 ;
      RECT 487.080 0.840 487.360 1511.160 ;
      RECT 489.320 0.840 489.600 1511.160 ;
      RECT 491.560 0.840 491.840 1511.160 ;
      RECT 493.800 0.840 494.080 1511.160 ;
      RECT 496.040 0.840 496.320 1511.160 ;
      RECT 498.280 0.840 498.560 1511.160 ;
      RECT 500.520 0.840 500.800 1511.160 ;
      RECT 502.760 0.840 503.040 1511.160 ;
      RECT 505.000 0.840 505.280 1511.160 ;
      RECT 507.240 0.840 507.520 1511.160 ;
      RECT 509.480 0.840 509.760 1511.160 ;
      RECT 511.720 0.840 512.000 1511.160 ;
      RECT 513.960 0.840 514.240 1511.160 ;
      RECT 516.200 0.840 516.480 1511.160 ;
      RECT 518.440 0.840 518.720 1511.160 ;
      RECT 520.680 0.840 520.960 1511.160 ;
      RECT 522.920 0.840 523.200 1511.160 ;
      RECT 525.160 0.840 525.440 1511.160 ;
      RECT 527.400 0.840 527.680 1511.160 ;
      RECT 529.640 0.840 529.920 1511.160 ;
      RECT 531.880 0.840 532.160 1511.160 ;
      RECT 534.120 0.840 534.400 1511.160 ;
      RECT 536.360 0.840 536.640 1511.160 ;
      RECT 538.600 0.840 538.880 1511.160 ;
      RECT 540.840 0.840 541.120 1511.160 ;
      RECT 543.080 0.840 543.360 1511.160 ;
      RECT 545.320 0.840 545.600 1511.160 ;
      RECT 547.560 0.840 547.840 1511.160 ;
      RECT 549.800 0.840 550.080 1511.160 ;
      RECT 552.040 0.840 552.320 1511.160 ;
      RECT 554.280 0.840 554.560 1511.160 ;
      RECT 556.520 0.840 556.800 1511.160 ;
      RECT 558.760 0.840 559.040 1511.160 ;
      RECT 561.000 0.840 561.280 1511.160 ;
      RECT 563.240 0.840 563.520 1511.160 ;
      RECT 565.480 0.840 565.760 1511.160 ;
      RECT 567.720 0.840 568.000 1511.160 ;
      RECT 569.960 0.840 570.240 1511.160 ;
      RECT 572.200 0.840 572.480 1511.160 ;
      RECT 574.440 0.840 574.720 1511.160 ;
      RECT 576.680 0.840 576.960 1511.160 ;
      RECT 578.920 0.840 579.200 1511.160 ;
      RECT 581.160 0.840 581.440 1511.160 ;
      RECT 583.400 0.840 583.680 1511.160 ;
      RECT 585.640 0.840 585.920 1511.160 ;
      RECT 587.880 0.840 588.160 1511.160 ;
      RECT 590.120 0.840 590.400 1511.160 ;
      RECT 592.360 0.840 592.640 1511.160 ;
      RECT 594.600 0.840 594.880 1511.160 ;
      RECT 596.840 0.840 597.120 1511.160 ;
      RECT 599.080 0.840 599.360 1511.160 ;
      RECT 601.320 0.840 601.600 1511.160 ;
      RECT 603.560 0.840 603.840 1511.160 ;
      RECT 605.800 0.840 606.080 1511.160 ;
      RECT 608.040 0.840 608.320 1511.160 ;
      RECT 610.280 0.840 610.560 1511.160 ;
      RECT 612.520 0.840 612.800 1511.160 ;
      RECT 614.760 0.840 615.040 1511.160 ;
      RECT 617.000 0.840 617.280 1511.160 ;
      RECT 619.240 0.840 619.520 1511.160 ;
      RECT 621.480 0.840 621.760 1511.160 ;
      RECT 623.720 0.840 624.000 1511.160 ;
      RECT 625.960 0.840 626.240 1511.160 ;
      RECT 628.200 0.840 628.480 1511.160 ;
      RECT 630.440 0.840 630.720 1511.160 ;
      RECT 632.680 0.840 632.960 1511.160 ;
      RECT 634.920 0.840 635.200 1511.160 ;
      RECT 637.160 0.840 637.440 1511.160 ;
      RECT 639.400 0.840 639.680 1511.160 ;
      RECT 641.640 0.840 641.920 1511.160 ;
      RECT 643.880 0.840 644.160 1511.160 ;
      RECT 646.120 0.840 646.400 1511.160 ;
      RECT 648.360 0.840 648.640 1511.160 ;
      RECT 650.600 0.840 650.880 1511.160 ;
      RECT 652.840 0.840 653.120 1511.160 ;
      RECT 655.080 0.840 655.360 1511.160 ;
      RECT 657.320 0.840 657.600 1511.160 ;
      RECT 659.560 0.840 659.840 1511.160 ;
      RECT 661.800 0.840 662.080 1511.160 ;
      RECT 664.040 0.840 664.320 1511.160 ;
      RECT 666.280 0.840 666.560 1511.160 ;
      RECT 668.520 0.840 668.800 1511.160 ;
      RECT 670.760 0.840 671.040 1511.160 ;
      RECT 673.000 0.840 673.280 1511.160 ;
      RECT 675.240 0.840 675.520 1511.160 ;
      RECT 677.480 0.840 677.760 1511.160 ;
      RECT 679.720 0.840 680.000 1511.160 ;
      RECT 681.960 0.840 682.240 1511.160 ;
      RECT 684.200 0.840 684.480 1511.160 ;
      RECT 686.440 0.840 686.720 1511.160 ;
      RECT 688.680 0.840 688.960 1511.160 ;
      RECT 690.920 0.840 691.200 1511.160 ;
      RECT 693.160 0.840 693.440 1511.160 ;
      RECT 695.400 0.840 695.680 1511.160 ;
      RECT 697.640 0.840 697.920 1511.160 ;
      RECT 699.880 0.840 700.160 1511.160 ;
      RECT 702.120 0.840 702.400 1511.160 ;
      RECT 704.360 0.840 704.640 1511.160 ;
      RECT 706.600 0.840 706.880 1511.160 ;
      RECT 708.840 0.840 709.120 1511.160 ;
      RECT 711.080 0.840 711.360 1511.160 ;
      RECT 713.320 0.840 713.600 1511.160 ;
      RECT 715.560 0.840 715.840 1511.160 ;
      RECT 717.800 0.840 718.080 1511.160 ;
      RECT 720.040 0.840 720.320 1511.160 ;
      RECT 722.280 0.840 722.560 1511.160 ;
      RECT 724.520 0.840 724.800 1511.160 ;
      RECT 726.760 0.840 727.040 1511.160 ;
      RECT 729.000 0.840 729.280 1511.160 ;
      RECT 731.240 0.840 731.520 1511.160 ;
      RECT 733.480 0.840 733.760 1511.160 ;
      RECT 735.720 0.840 736.000 1511.160 ;
      RECT 737.960 0.840 738.240 1511.160 ;
      RECT 740.200 0.840 740.480 1511.160 ;
      RECT 742.440 0.840 742.720 1511.160 ;
      RECT 744.680 0.840 744.960 1511.160 ;
      RECT 746.920 0.840 747.200 1511.160 ;
      RECT 749.160 0.840 749.440 1511.160 ;
      RECT 751.400 0.840 751.680 1511.160 ;
      RECT 753.640 0.840 753.920 1511.160 ;
      RECT 755.880 0.840 756.160 1511.160 ;
      RECT 758.120 0.840 758.400 1511.160 ;
      RECT 760.360 0.840 760.640 1511.160 ;
      RECT 762.600 0.840 762.880 1511.160 ;
      RECT 764.840 0.840 765.120 1511.160 ;
      RECT 767.080 0.840 767.360 1511.160 ;
      RECT 769.320 0.840 769.600 1511.160 ;
      RECT 771.560 0.840 771.840 1511.160 ;
      RECT 773.800 0.840 774.080 1511.160 ;
      RECT 776.040 0.840 776.320 1511.160 ;
      RECT 778.280 0.840 778.560 1511.160 ;
      RECT 780.520 0.840 780.800 1511.160 ;
      RECT 782.760 0.840 783.040 1511.160 ;
      RECT 785.000 0.840 785.280 1511.160 ;
      RECT 787.240 0.840 787.520 1511.160 ;
      RECT 789.480 0.840 789.760 1511.160 ;
      RECT 791.720 0.840 792.000 1511.160 ;
      RECT 793.960 0.840 794.240 1511.160 ;
      RECT 796.200 0.840 796.480 1511.160 ;
      RECT 798.440 0.840 798.720 1511.160 ;
      RECT 800.680 0.840 800.960 1511.160 ;
      RECT 802.920 0.840 803.200 1511.160 ;
      RECT 805.160 0.840 805.440 1511.160 ;
      RECT 807.400 0.840 807.680 1511.160 ;
      RECT 809.640 0.840 809.920 1511.160 ;
      RECT 811.880 0.840 812.160 1511.160 ;
      RECT 814.120 0.840 814.400 1511.160 ;
      RECT 816.360 0.840 816.640 1511.160 ;
      RECT 818.600 0.840 818.880 1511.160 ;
      RECT 820.840 0.840 821.120 1511.160 ;
      RECT 823.080 0.840 823.360 1511.160 ;
      RECT 825.320 0.840 825.600 1511.160 ;
      RECT 827.560 0.840 827.840 1511.160 ;
      RECT 829.800 0.840 830.080 1511.160 ;
      RECT 832.040 0.840 832.320 1511.160 ;
      RECT 834.280 0.840 834.560 1511.160 ;
      RECT 836.520 0.840 836.800 1511.160 ;
      RECT 838.760 0.840 839.040 1511.160 ;
      RECT 841.000 0.840 841.280 1511.160 ;
      RECT 843.240 0.840 843.520 1511.160 ;
      RECT 845.480 0.840 845.760 1511.160 ;
      RECT 847.720 0.840 848.000 1511.160 ;
      RECT 849.960 0.840 850.240 1511.160 ;
      RECT 852.200 0.840 852.480 1511.160 ;
      RECT 854.440 0.840 854.720 1511.160 ;
      RECT 856.680 0.840 856.960 1511.160 ;
      RECT 858.920 0.840 859.200 1511.160 ;
      RECT 861.160 0.840 861.440 1511.160 ;
      RECT 863.400 0.840 863.680 1511.160 ;
      RECT 865.640 0.840 865.920 1511.160 ;
      RECT 867.880 0.840 868.160 1511.160 ;
      RECT 870.120 0.840 870.400 1511.160 ;
      RECT 872.360 0.840 872.640 1511.160 ;
      RECT 874.600 0.840 874.880 1511.160 ;
      RECT 876.840 0.840 877.120 1511.160 ;
      RECT 879.080 0.840 879.360 1511.160 ;
      RECT 881.320 0.840 881.600 1511.160 ;
      RECT 883.560 0.840 883.840 1511.160 ;
      RECT 885.800 0.840 886.080 1511.160 ;
      RECT 888.040 0.840 888.320 1511.160 ;
      RECT 890.280 0.840 890.560 1511.160 ;
      RECT 892.520 0.840 892.800 1511.160 ;
      RECT 894.760 0.840 895.040 1511.160 ;
      RECT 897.000 0.840 897.280 1511.160 ;
      RECT 899.240 0.840 899.520 1511.160 ;
      RECT 901.480 0.840 901.760 1511.160 ;
      RECT 903.720 0.840 904.000 1511.160 ;
      RECT 905.960 0.840 906.240 1511.160 ;
      RECT 908.200 0.840 908.480 1511.160 ;
      RECT 910.440 0.840 910.720 1511.160 ;
      RECT 912.680 0.840 912.960 1511.160 ;
      RECT 914.920 0.840 915.200 1511.160 ;
      RECT 917.160 0.840 917.440 1511.160 ;
      RECT 919.400 0.840 919.680 1511.160 ;
      RECT 921.640 0.840 921.920 1511.160 ;
      RECT 923.880 0.840 924.160 1511.160 ;
      RECT 926.120 0.840 926.400 1511.160 ;
      RECT 928.360 0.840 928.640 1511.160 ;
      RECT 930.600 0.840 930.880 1511.160 ;
      RECT 932.840 0.840 933.120 1511.160 ;
      RECT 935.080 0.840 935.360 1511.160 ;
      RECT 937.320 0.840 937.600 1511.160 ;
      RECT 939.560 0.840 939.840 1511.160 ;
      RECT 941.800 0.840 942.080 1511.160 ;
      RECT 944.040 0.840 944.320 1511.160 ;
      RECT 946.280 0.840 946.560 1511.160 ;
      RECT 948.520 0.840 948.800 1511.160 ;
      RECT 950.760 0.840 951.040 1511.160 ;
      RECT 953.000 0.840 953.280 1511.160 ;
      RECT 955.240 0.840 955.520 1511.160 ;
      RECT 957.480 0.840 957.760 1511.160 ;
      RECT 959.720 0.840 960.000 1511.160 ;
      RECT 961.960 0.840 962.240 1511.160 ;
      RECT 964.200 0.840 964.480 1511.160 ;
      RECT 966.440 0.840 966.720 1511.160 ;
      RECT 968.680 0.840 968.960 1511.160 ;
      RECT 970.920 0.840 971.200 1511.160 ;
      RECT 973.160 0.840 973.440 1511.160 ;
      RECT 975.400 0.840 975.680 1511.160 ;
      RECT 977.640 0.840 977.920 1511.160 ;
      RECT 979.880 0.840 980.160 1511.160 ;
      RECT 982.120 0.840 982.400 1511.160 ;
      RECT 984.360 0.840 984.640 1511.160 ;
      RECT 986.600 0.840 986.880 1511.160 ;
      RECT 988.840 0.840 989.120 1511.160 ;
      RECT 991.080 0.840 991.360 1511.160 ;
      RECT 993.320 0.840 993.600 1511.160 ;
      RECT 995.560 0.840 995.840 1511.160 ;
      RECT 997.800 0.840 998.080 1511.160 ;
      RECT 1000.040 0.840 1000.320 1511.160 ;
      RECT 1002.280 0.840 1002.560 1511.160 ;
      RECT 1004.520 0.840 1004.800 1511.160 ;
      RECT 1006.760 0.840 1007.040 1511.160 ;
      RECT 1009.000 0.840 1009.280 1511.160 ;
      RECT 1011.240 0.840 1011.520 1511.160 ;
      RECT 1013.480 0.840 1013.760 1511.160 ;
      RECT 1015.720 0.840 1016.000 1511.160 ;
      RECT 1017.960 0.840 1018.240 1511.160 ;
      RECT 1020.200 0.840 1020.480 1511.160 ;
      RECT 1022.440 0.840 1022.720 1511.160 ;
      RECT 1024.680 0.840 1024.960 1511.160 ;
      RECT 1026.920 0.840 1027.200 1511.160 ;
      RECT 1029.160 0.840 1029.440 1511.160 ;
      RECT 1031.400 0.840 1031.680 1511.160 ;
      RECT 1033.640 0.840 1033.920 1511.160 ;
      RECT 1035.880 0.840 1036.160 1511.160 ;
      RECT 1038.120 0.840 1038.400 1511.160 ;
      RECT 1040.360 0.840 1040.640 1511.160 ;
      RECT 1042.600 0.840 1042.880 1511.160 ;
      RECT 1044.840 0.840 1045.120 1511.160 ;
      RECT 1047.080 0.840 1047.360 1511.160 ;
      RECT 1049.320 0.840 1049.600 1511.160 ;
      RECT 1051.560 0.840 1051.840 1511.160 ;
      RECT 1053.800 0.840 1054.080 1511.160 ;
      RECT 1056.040 0.840 1056.320 1511.160 ;
      RECT 1058.280 0.840 1058.560 1511.160 ;
      RECT 1060.520 0.840 1060.800 1511.160 ;
      RECT 1062.760 0.840 1063.040 1511.160 ;
      RECT 1065.000 0.840 1065.280 1511.160 ;
      RECT 1067.240 0.840 1067.520 1511.160 ;
      RECT 1069.480 0.840 1069.760 1511.160 ;
      RECT 1071.720 0.840 1072.000 1511.160 ;
      RECT 1073.960 0.840 1074.240 1511.160 ;
      RECT 1076.200 0.840 1076.480 1511.160 ;
      RECT 1078.440 0.840 1078.720 1511.160 ;
      RECT 1080.680 0.840 1080.960 1511.160 ;
      RECT 1082.920 0.840 1083.200 1511.160 ;
      RECT 1085.160 0.840 1085.440 1511.160 ;
      RECT 1087.400 0.840 1087.680 1511.160 ;
      RECT 1089.640 0.840 1089.920 1511.160 ;
      RECT 1091.880 0.840 1092.160 1511.160 ;
      RECT 1094.120 0.840 1094.400 1511.160 ;
      RECT 1096.360 0.840 1096.640 1511.160 ;
      RECT 1098.600 0.840 1098.880 1511.160 ;
      RECT 1100.840 0.840 1101.120 1511.160 ;
      RECT 1103.080 0.840 1103.360 1511.160 ;
      RECT 1105.320 0.840 1105.600 1511.160 ;
      RECT 1107.560 0.840 1107.840 1511.160 ;
      RECT 1109.800 0.840 1110.080 1511.160 ;
      RECT 1112.040 0.840 1112.320 1511.160 ;
      RECT 1114.280 0.840 1114.560 1511.160 ;
      RECT 1116.520 0.840 1116.800 1511.160 ;
      RECT 1118.760 0.840 1119.040 1511.160 ;
      RECT 1121.000 0.840 1121.280 1511.160 ;
      RECT 1123.240 0.840 1123.520 1511.160 ;
      RECT 1125.480 0.840 1125.760 1511.160 ;
      RECT 1127.720 0.840 1128.000 1511.160 ;
      RECT 1129.960 0.840 1130.240 1511.160 ;
      RECT 1132.200 0.840 1132.480 1511.160 ;
      RECT 1134.440 0.840 1134.720 1511.160 ;
      RECT 1136.680 0.840 1136.960 1511.160 ;
      RECT 1138.920 0.840 1139.200 1511.160 ;
      RECT 1141.160 0.840 1141.440 1511.160 ;
      RECT 1143.400 0.840 1143.680 1511.160 ;
      RECT 1145.640 0.840 1145.920 1511.160 ;
      RECT 1147.880 0.840 1148.160 1511.160 ;
      RECT 1150.120 0.840 1150.400 1511.160 ;
      RECT 1152.360 0.840 1152.640 1511.160 ;
      RECT 1154.600 0.840 1154.880 1511.160 ;
      RECT 1156.840 0.840 1157.120 1511.160 ;
      RECT 1159.080 0.840 1159.360 1511.160 ;
      RECT 1161.320 0.840 1161.600 1511.160 ;
      RECT 1163.560 0.840 1163.840 1511.160 ;
      RECT 1165.800 0.840 1166.080 1511.160 ;
      RECT 1168.040 0.840 1168.320 1511.160 ;
      RECT 1170.280 0.840 1170.560 1511.160 ;
      RECT 1172.520 0.840 1172.800 1511.160 ;
      RECT 1174.760 0.840 1175.040 1511.160 ;
      RECT 1177.000 0.840 1177.280 1511.160 ;
      RECT 1179.240 0.840 1179.520 1511.160 ;
      RECT 1181.480 0.840 1181.760 1511.160 ;
      RECT 1183.720 0.840 1184.000 1511.160 ;
      RECT 1185.960 0.840 1186.240 1511.160 ;
      RECT 1188.200 0.840 1188.480 1511.160 ;
      RECT 1190.440 0.840 1190.720 1511.160 ;
      RECT 1192.680 0.840 1192.960 1511.160 ;
      RECT 1194.920 0.840 1195.200 1511.160 ;
      RECT 1197.160 0.840 1197.440 1511.160 ;
      RECT 1199.400 0.840 1199.680 1511.160 ;
      RECT 1201.640 0.840 1201.920 1511.160 ;
      RECT 1203.880 0.840 1204.160 1511.160 ;
      RECT 1206.120 0.840 1206.400 1511.160 ;
      RECT 1208.360 0.840 1208.640 1511.160 ;
      RECT 1210.600 0.840 1210.880 1511.160 ;
      RECT 1212.840 0.840 1213.120 1511.160 ;
      RECT 1215.080 0.840 1215.360 1511.160 ;
      RECT 1217.320 0.840 1217.600 1511.160 ;
      RECT 1219.560 0.840 1219.840 1511.160 ;
      RECT 1221.800 0.840 1222.080 1511.160 ;
      RECT 1224.040 0.840 1224.320 1511.160 ;
      RECT 1226.280 0.840 1226.560 1511.160 ;
      RECT 1228.520 0.840 1228.800 1511.160 ;
      RECT 1230.760 0.840 1231.040 1511.160 ;
      RECT 1233.000 0.840 1233.280 1511.160 ;
      RECT 1235.240 0.840 1235.520 1511.160 ;
      RECT 1237.480 0.840 1237.760 1511.160 ;
      RECT 1239.720 0.840 1240.000 1511.160 ;
      RECT 1241.960 0.840 1242.240 1511.160 ;
      RECT 1244.200 0.840 1244.480 1511.160 ;
      RECT 1246.440 0.840 1246.720 1511.160 ;
      RECT 1248.680 0.840 1248.960 1511.160 ;
      RECT 1250.920 0.840 1251.200 1511.160 ;
      RECT 1253.160 0.840 1253.440 1511.160 ;
      RECT 1255.400 0.840 1255.680 1511.160 ;
      RECT 1257.640 0.840 1257.920 1511.160 ;
      RECT 1259.880 0.840 1260.160 1511.160 ;
      RECT 1262.120 0.840 1262.400 1511.160 ;
      RECT 1264.360 0.840 1264.640 1511.160 ;
      RECT 1266.600 0.840 1266.880 1511.160 ;
      RECT 1268.840 0.840 1269.120 1511.160 ;
      RECT 1271.080 0.840 1271.360 1511.160 ;
      RECT 1273.320 0.840 1273.600 1511.160 ;
      RECT 1275.560 0.840 1275.840 1511.160 ;
      RECT 1277.800 0.840 1278.080 1511.160 ;
      RECT 1280.040 0.840 1280.320 1511.160 ;
      RECT 1282.280 0.840 1282.560 1511.160 ;
      RECT 1284.520 0.840 1284.800 1511.160 ;
      RECT 1286.760 0.840 1287.040 1511.160 ;
      RECT 1289.000 0.840 1289.280 1511.160 ;
      RECT 1291.240 0.840 1291.520 1511.160 ;
      RECT 1293.480 0.840 1293.760 1511.160 ;
      RECT 1295.720 0.840 1296.000 1511.160 ;
      RECT 1297.960 0.840 1298.240 1511.160 ;
      RECT 1300.200 0.840 1300.480 1511.160 ;
      RECT 1302.440 0.840 1302.720 1511.160 ;
      RECT 1304.680 0.840 1304.960 1511.160 ;
      RECT 1306.920 0.840 1307.200 1511.160 ;
      RECT 1309.160 0.840 1309.440 1511.160 ;
      RECT 1311.400 0.840 1311.680 1511.160 ;
      RECT 1313.640 0.840 1313.920 1511.160 ;
      RECT 1315.880 0.840 1316.160 1511.160 ;
      RECT 1318.120 0.840 1318.400 1511.160 ;
      RECT 1320.360 0.840 1320.640 1511.160 ;
      RECT 1322.600 0.840 1322.880 1511.160 ;
      RECT 1324.840 0.840 1325.120 1511.160 ;
      RECT 1327.080 0.840 1327.360 1511.160 ;
      RECT 1329.320 0.840 1329.600 1511.160 ;
      RECT 1331.560 0.840 1331.840 1511.160 ;
      RECT 1333.800 0.840 1334.080 1511.160 ;
      RECT 1336.040 0.840 1336.320 1511.160 ;
      RECT 1338.280 0.840 1338.560 1511.160 ;
      RECT 1340.520 0.840 1340.800 1511.160 ;
      RECT 1342.760 0.840 1343.040 1511.160 ;
      RECT 1345.000 0.840 1345.280 1511.160 ;
      RECT 1347.240 0.840 1347.520 1511.160 ;
      RECT 1349.480 0.840 1349.760 1511.160 ;
      RECT 1351.720 0.840 1352.000 1511.160 ;
      RECT 1353.960 0.840 1354.240 1511.160 ;
      RECT 1356.200 0.840 1356.480 1511.160 ;
      RECT 1358.440 0.840 1358.720 1511.160 ;
      RECT 1360.680 0.840 1360.960 1511.160 ;
      RECT 1362.920 0.840 1363.200 1511.160 ;
      RECT 1365.160 0.840 1365.440 1511.160 ;
      RECT 1367.400 0.840 1367.680 1511.160 ;
      RECT 1369.640 0.840 1369.920 1511.160 ;
      RECT 1371.880 0.840 1372.160 1511.160 ;
      RECT 1374.120 0.840 1374.400 1511.160 ;
      RECT 1376.360 0.840 1376.640 1511.160 ;
      RECT 1378.600 0.840 1378.880 1511.160 ;
      RECT 1380.840 0.840 1381.120 1511.160 ;
      RECT 1383.080 0.840 1383.360 1511.160 ;
      RECT 1385.320 0.840 1385.600 1511.160 ;
      RECT 1387.560 0.840 1387.840 1511.160 ;
      RECT 1389.800 0.840 1390.080 1511.160 ;
      RECT 1392.040 0.840 1392.320 1511.160 ;
      RECT 1394.280 0.840 1394.560 1511.160 ;
      RECT 1396.520 0.840 1396.800 1511.160 ;
      RECT 1398.760 0.840 1399.040 1511.160 ;
      RECT 1401.000 0.840 1401.280 1511.160 ;
      RECT 1403.240 0.840 1403.520 1511.160 ;
      RECT 1405.480 0.840 1405.760 1511.160 ;
      RECT 1407.720 0.840 1408.000 1511.160 ;
      RECT 1409.960 0.840 1410.240 1511.160 ;
      RECT 1412.200 0.840 1412.480 1511.160 ;
      RECT 1414.440 0.840 1414.720 1511.160 ;
      RECT 1416.680 0.840 1416.960 1511.160 ;
      RECT 1418.920 0.840 1419.200 1511.160 ;
      RECT 1421.160 0.840 1421.440 1511.160 ;
      RECT 1423.400 0.840 1423.680 1511.160 ;
      RECT 1425.640 0.840 1425.920 1511.160 ;
      RECT 1427.880 0.840 1428.160 1511.160 ;
      RECT 1430.120 0.840 1430.400 1511.160 ;
      RECT 1432.360 0.840 1432.640 1511.160 ;
      RECT 1434.600 0.840 1434.880 1511.160 ;
      RECT 1436.840 0.840 1437.120 1511.160 ;
      RECT 1439.080 0.840 1439.360 1511.160 ;
      RECT 1441.320 0.840 1441.600 1511.160 ;
      RECT 1443.560 0.840 1443.840 1511.160 ;
      RECT 1445.800 0.840 1446.080 1511.160 ;
      RECT 1448.040 0.840 1448.320 1511.160 ;
      RECT 1450.280 0.840 1450.560 1511.160 ;
      RECT 1452.520 0.840 1452.800 1511.160 ;
      RECT 1454.760 0.840 1455.040 1511.160 ;
      RECT 1457.000 0.840 1457.280 1511.160 ;
      RECT 1459.240 0.840 1459.520 1511.160 ;
      RECT 1461.480 0.840 1461.760 1511.160 ;
      RECT 1463.720 0.840 1464.000 1511.160 ;
      RECT 1465.960 0.840 1466.240 1511.160 ;
      RECT 1468.200 0.840 1468.480 1511.160 ;
      RECT 1470.440 0.840 1470.720 1511.160 ;
      RECT 1472.680 0.840 1472.960 1511.160 ;
      RECT 1474.920 0.840 1475.200 1511.160 ;
      RECT 1477.160 0.840 1477.440 1511.160 ;
      RECT 1479.400 0.840 1479.680 1511.160 ;
      RECT 1481.640 0.840 1481.920 1511.160 ;
      RECT 1483.880 0.840 1484.160 1511.160 ;
      RECT 1486.120 0.840 1486.400 1511.160 ;
      RECT 1488.360 0.840 1488.640 1511.160 ;
      RECT 1490.600 0.840 1490.880 1511.160 ;
      RECT 1492.840 0.840 1493.120 1511.160 ;
      RECT 1495.080 0.840 1495.360 1511.160 ;
      RECT 1497.320 0.840 1497.600 1511.160 ;
      RECT 1499.560 0.840 1499.840 1511.160 ;
      RECT 1501.800 0.840 1502.080 1511.160 ;
      RECT 1504.040 0.840 1504.320 1511.160 ;
      RECT 1506.280 0.840 1506.560 1511.160 ;
      RECT 1508.520 0.840 1508.800 1511.160 ;
      RECT 1510.760 0.840 1511.040 1511.160 ;
      RECT 1513.000 0.840 1513.280 1511.160 ;
      RECT 1515.240 0.840 1515.520 1511.160 ;
      RECT 1517.480 0.840 1517.760 1511.160 ;
      RECT 1519.720 0.840 1520.000 1511.160 ;
      RECT 1521.960 0.840 1522.240 1511.160 ;
      RECT 1524.200 0.840 1524.480 1511.160 ;
      RECT 1526.440 0.840 1526.720 1511.160 ;
      RECT 1528.680 0.840 1528.960 1511.160 ;
      RECT 1530.920 0.840 1531.200 1511.160 ;
      RECT 1533.160 0.840 1533.440 1511.160 ;
      RECT 1535.400 0.840 1535.680 1511.160 ;
      RECT 1537.640 0.840 1537.920 1511.160 ;
      RECT 1539.880 0.840 1540.160 1511.160 ;
      RECT 1542.120 0.840 1542.400 1511.160 ;
      RECT 1544.360 0.840 1544.640 1511.160 ;
      RECT 1546.600 0.840 1546.880 1511.160 ;
      RECT 1548.840 0.840 1549.120 1511.160 ;
      RECT 1551.080 0.840 1551.360 1511.160 ;
      RECT 1553.320 0.840 1553.600 1511.160 ;
      RECT 1555.560 0.840 1555.840 1511.160 ;
      RECT 1557.800 0.840 1558.080 1511.160 ;
      RECT 1560.040 0.840 1560.320 1511.160 ;
      RECT 1562.280 0.840 1562.560 1511.160 ;
      RECT 1564.520 0.840 1564.800 1511.160 ;
      RECT 1566.760 0.840 1567.040 1511.160 ;
      RECT 1569.000 0.840 1569.280 1511.160 ;
      RECT 1571.240 0.840 1571.520 1511.160 ;
      RECT 1573.480 0.840 1573.760 1511.160 ;
      RECT 1575.720 0.840 1576.000 1511.160 ;
      RECT 1577.960 0.840 1578.240 1511.160 ;
      RECT 1580.200 0.840 1580.480 1511.160 ;
      RECT 1582.440 0.840 1582.720 1511.160 ;
      RECT 1584.680 0.840 1584.960 1511.160 ;
      RECT 1586.920 0.840 1587.200 1511.160 ;
      RECT 1589.160 0.840 1589.440 1511.160 ;
      RECT 1591.400 0.840 1591.680 1511.160 ;
      RECT 1593.640 0.840 1593.920 1511.160 ;
      RECT 1595.880 0.840 1596.160 1511.160 ;
      RECT 1598.120 0.840 1598.400 1511.160 ;
      RECT 1600.360 0.840 1600.640 1511.160 ;
      RECT 1602.600 0.840 1602.880 1511.160 ;
      RECT 1604.840 0.840 1605.120 1511.160 ;
      RECT 1607.080 0.840 1607.360 1511.160 ;
    END
  END VSS
  PIN VDD
    DIRECTION INOUT ;
    USE POWER ;
    PORT
      LAYER metal4 ;
      RECT 2.120 0.840 2.400 1511.160 ;
      RECT 4.360 0.840 4.640 1511.160 ;
      RECT 6.600 0.840 6.880 1511.160 ;
      RECT 8.840 0.840 9.120 1511.160 ;
      RECT 11.080 0.840 11.360 1511.160 ;
      RECT 13.320 0.840 13.600 1511.160 ;
      RECT 15.560 0.840 15.840 1511.160 ;
      RECT 17.800 0.840 18.080 1511.160 ;
      RECT 20.040 0.840 20.320 1511.160 ;
      RECT 22.280 0.840 22.560 1511.160 ;
      RECT 24.520 0.840 24.800 1511.160 ;
      RECT 26.760 0.840 27.040 1511.160 ;
      RECT 29.000 0.840 29.280 1511.160 ;
      RECT 31.240 0.840 31.520 1511.160 ;
      RECT 33.480 0.840 33.760 1511.160 ;
      RECT 35.720 0.840 36.000 1511.160 ;
      RECT 37.960 0.840 38.240 1511.160 ;
      RECT 40.200 0.840 40.480 1511.160 ;
      RECT 42.440 0.840 42.720 1511.160 ;
      RECT 44.680 0.840 44.960 1511.160 ;
      RECT 46.920 0.840 47.200 1511.160 ;
      RECT 49.160 0.840 49.440 1511.160 ;
      RECT 51.400 0.840 51.680 1511.160 ;
      RECT 53.640 0.840 53.920 1511.160 ;
      RECT 55.880 0.840 56.160 1511.160 ;
      RECT 58.120 0.840 58.400 1511.160 ;
      RECT 60.360 0.840 60.640 1511.160 ;
      RECT 62.600 0.840 62.880 1511.160 ;
      RECT 64.840 0.840 65.120 1511.160 ;
      RECT 67.080 0.840 67.360 1511.160 ;
      RECT 69.320 0.840 69.600 1511.160 ;
      RECT 71.560 0.840 71.840 1511.160 ;
      RECT 73.800 0.840 74.080 1511.160 ;
      RECT 76.040 0.840 76.320 1511.160 ;
      RECT 78.280 0.840 78.560 1511.160 ;
      RECT 80.520 0.840 80.800 1511.160 ;
      RECT 82.760 0.840 83.040 1511.160 ;
      RECT 85.000 0.840 85.280 1511.160 ;
      RECT 87.240 0.840 87.520 1511.160 ;
      RECT 89.480 0.840 89.760 1511.160 ;
      RECT 91.720 0.840 92.000 1511.160 ;
      RECT 93.960 0.840 94.240 1511.160 ;
      RECT 96.200 0.840 96.480 1511.160 ;
      RECT 98.440 0.840 98.720 1511.160 ;
      RECT 100.680 0.840 100.960 1511.160 ;
      RECT 102.920 0.840 103.200 1511.160 ;
      RECT 105.160 0.840 105.440 1511.160 ;
      RECT 107.400 0.840 107.680 1511.160 ;
      RECT 109.640 0.840 109.920 1511.160 ;
      RECT 111.880 0.840 112.160 1511.160 ;
      RECT 114.120 0.840 114.400 1511.160 ;
      RECT 116.360 0.840 116.640 1511.160 ;
      RECT 118.600 0.840 118.880 1511.160 ;
      RECT 120.840 0.840 121.120 1511.160 ;
      RECT 123.080 0.840 123.360 1511.160 ;
      RECT 125.320 0.840 125.600 1511.160 ;
      RECT 127.560 0.840 127.840 1511.160 ;
      RECT 129.800 0.840 130.080 1511.160 ;
      RECT 132.040 0.840 132.320 1511.160 ;
      RECT 134.280 0.840 134.560 1511.160 ;
      RECT 136.520 0.840 136.800 1511.160 ;
      RECT 138.760 0.840 139.040 1511.160 ;
      RECT 141.000 0.840 141.280 1511.160 ;
      RECT 143.240 0.840 143.520 1511.160 ;
      RECT 145.480 0.840 145.760 1511.160 ;
      RECT 147.720 0.840 148.000 1511.160 ;
      RECT 149.960 0.840 150.240 1511.160 ;
      RECT 152.200 0.840 152.480 1511.160 ;
      RECT 154.440 0.840 154.720 1511.160 ;
      RECT 156.680 0.840 156.960 1511.160 ;
      RECT 158.920 0.840 159.200 1511.160 ;
      RECT 161.160 0.840 161.440 1511.160 ;
      RECT 163.400 0.840 163.680 1511.160 ;
      RECT 165.640 0.840 165.920 1511.160 ;
      RECT 167.880 0.840 168.160 1511.160 ;
      RECT 170.120 0.840 170.400 1511.160 ;
      RECT 172.360 0.840 172.640 1511.160 ;
      RECT 174.600 0.840 174.880 1511.160 ;
      RECT 176.840 0.840 177.120 1511.160 ;
      RECT 179.080 0.840 179.360 1511.160 ;
      RECT 181.320 0.840 181.600 1511.160 ;
      RECT 183.560 0.840 183.840 1511.160 ;
      RECT 185.800 0.840 186.080 1511.160 ;
      RECT 188.040 0.840 188.320 1511.160 ;
      RECT 190.280 0.840 190.560 1511.160 ;
      RECT 192.520 0.840 192.800 1511.160 ;
      RECT 194.760 0.840 195.040 1511.160 ;
      RECT 197.000 0.840 197.280 1511.160 ;
      RECT 199.240 0.840 199.520 1511.160 ;
      RECT 201.480 0.840 201.760 1511.160 ;
      RECT 203.720 0.840 204.000 1511.160 ;
      RECT 205.960 0.840 206.240 1511.160 ;
      RECT 208.200 0.840 208.480 1511.160 ;
      RECT 210.440 0.840 210.720 1511.160 ;
      RECT 212.680 0.840 212.960 1511.160 ;
      RECT 214.920 0.840 215.200 1511.160 ;
      RECT 217.160 0.840 217.440 1511.160 ;
      RECT 219.400 0.840 219.680 1511.160 ;
      RECT 221.640 0.840 221.920 1511.160 ;
      RECT 223.880 0.840 224.160 1511.160 ;
      RECT 226.120 0.840 226.400 1511.160 ;
      RECT 228.360 0.840 228.640 1511.160 ;
      RECT 230.600 0.840 230.880 1511.160 ;
      RECT 232.840 0.840 233.120 1511.160 ;
      RECT 235.080 0.840 235.360 1511.160 ;
      RECT 237.320 0.840 237.600 1511.160 ;
      RECT 239.560 0.840 239.840 1511.160 ;
      RECT 241.800 0.840 242.080 1511.160 ;
      RECT 244.040 0.840 244.320 1511.160 ;
      RECT 246.280 0.840 246.560 1511.160 ;
      RECT 248.520 0.840 248.800 1511.160 ;
      RECT 250.760 0.840 251.040 1511.160 ;
      RECT 253.000 0.840 253.280 1511.160 ;
      RECT 255.240 0.840 255.520 1511.160 ;
      RECT 257.480 0.840 257.760 1511.160 ;
      RECT 259.720 0.840 260.000 1511.160 ;
      RECT 261.960 0.840 262.240 1511.160 ;
      RECT 264.200 0.840 264.480 1511.160 ;
      RECT 266.440 0.840 266.720 1511.160 ;
      RECT 268.680 0.840 268.960 1511.160 ;
      RECT 270.920 0.840 271.200 1511.160 ;
      RECT 273.160 0.840 273.440 1511.160 ;
      RECT 275.400 0.840 275.680 1511.160 ;
      RECT 277.640 0.840 277.920 1511.160 ;
      RECT 279.880 0.840 280.160 1511.160 ;
      RECT 282.120 0.840 282.400 1511.160 ;
      RECT 284.360 0.840 284.640 1511.160 ;
      RECT 286.600 0.840 286.880 1511.160 ;
      RECT 288.840 0.840 289.120 1511.160 ;
      RECT 291.080 0.840 291.360 1511.160 ;
      RECT 293.320 0.840 293.600 1511.160 ;
      RECT 295.560 0.840 295.840 1511.160 ;
      RECT 297.800 0.840 298.080 1511.160 ;
      RECT 300.040 0.840 300.320 1511.160 ;
      RECT 302.280 0.840 302.560 1511.160 ;
      RECT 304.520 0.840 304.800 1511.160 ;
      RECT 306.760 0.840 307.040 1511.160 ;
      RECT 309.000 0.840 309.280 1511.160 ;
      RECT 311.240 0.840 311.520 1511.160 ;
      RECT 313.480 0.840 313.760 1511.160 ;
      RECT 315.720 0.840 316.000 1511.160 ;
      RECT 317.960 0.840 318.240 1511.160 ;
      RECT 320.200 0.840 320.480 1511.160 ;
      RECT 322.440 0.840 322.720 1511.160 ;
      RECT 324.680 0.840 324.960 1511.160 ;
      RECT 326.920 0.840 327.200 1511.160 ;
      RECT 329.160 0.840 329.440 1511.160 ;
      RECT 331.400 0.840 331.680 1511.160 ;
      RECT 333.640 0.840 333.920 1511.160 ;
      RECT 335.880 0.840 336.160 1511.160 ;
      RECT 338.120 0.840 338.400 1511.160 ;
      RECT 340.360 0.840 340.640 1511.160 ;
      RECT 342.600 0.840 342.880 1511.160 ;
      RECT 344.840 0.840 345.120 1511.160 ;
      RECT 347.080 0.840 347.360 1511.160 ;
      RECT 349.320 0.840 349.600 1511.160 ;
      RECT 351.560 0.840 351.840 1511.160 ;
      RECT 353.800 0.840 354.080 1511.160 ;
      RECT 356.040 0.840 356.320 1511.160 ;
      RECT 358.280 0.840 358.560 1511.160 ;
      RECT 360.520 0.840 360.800 1511.160 ;
      RECT 362.760 0.840 363.040 1511.160 ;
      RECT 365.000 0.840 365.280 1511.160 ;
      RECT 367.240 0.840 367.520 1511.160 ;
      RECT 369.480 0.840 369.760 1511.160 ;
      RECT 371.720 0.840 372.000 1511.160 ;
      RECT 373.960 0.840 374.240 1511.160 ;
      RECT 376.200 0.840 376.480 1511.160 ;
      RECT 378.440 0.840 378.720 1511.160 ;
      RECT 380.680 0.840 380.960 1511.160 ;
      RECT 382.920 0.840 383.200 1511.160 ;
      RECT 385.160 0.840 385.440 1511.160 ;
      RECT 387.400 0.840 387.680 1511.160 ;
      RECT 389.640 0.840 389.920 1511.160 ;
      RECT 391.880 0.840 392.160 1511.160 ;
      RECT 394.120 0.840 394.400 1511.160 ;
      RECT 396.360 0.840 396.640 1511.160 ;
      RECT 398.600 0.840 398.880 1511.160 ;
      RECT 400.840 0.840 401.120 1511.160 ;
      RECT 403.080 0.840 403.360 1511.160 ;
      RECT 405.320 0.840 405.600 1511.160 ;
      RECT 407.560 0.840 407.840 1511.160 ;
      RECT 409.800 0.840 410.080 1511.160 ;
      RECT 412.040 0.840 412.320 1511.160 ;
      RECT 414.280 0.840 414.560 1511.160 ;
      RECT 416.520 0.840 416.800 1511.160 ;
      RECT 418.760 0.840 419.040 1511.160 ;
      RECT 421.000 0.840 421.280 1511.160 ;
      RECT 423.240 0.840 423.520 1511.160 ;
      RECT 425.480 0.840 425.760 1511.160 ;
      RECT 427.720 0.840 428.000 1511.160 ;
      RECT 429.960 0.840 430.240 1511.160 ;
      RECT 432.200 0.840 432.480 1511.160 ;
      RECT 434.440 0.840 434.720 1511.160 ;
      RECT 436.680 0.840 436.960 1511.160 ;
      RECT 438.920 0.840 439.200 1511.160 ;
      RECT 441.160 0.840 441.440 1511.160 ;
      RECT 443.400 0.840 443.680 1511.160 ;
      RECT 445.640 0.840 445.920 1511.160 ;
      RECT 447.880 0.840 448.160 1511.160 ;
      RECT 450.120 0.840 450.400 1511.160 ;
      RECT 452.360 0.840 452.640 1511.160 ;
      RECT 454.600 0.840 454.880 1511.160 ;
      RECT 456.840 0.840 457.120 1511.160 ;
      RECT 459.080 0.840 459.360 1511.160 ;
      RECT 461.320 0.840 461.600 1511.160 ;
      RECT 463.560 0.840 463.840 1511.160 ;
      RECT 465.800 0.840 466.080 1511.160 ;
      RECT 468.040 0.840 468.320 1511.160 ;
      RECT 470.280 0.840 470.560 1511.160 ;
      RECT 472.520 0.840 472.800 1511.160 ;
      RECT 474.760 0.840 475.040 1511.160 ;
      RECT 477.000 0.840 477.280 1511.160 ;
      RECT 479.240 0.840 479.520 1511.160 ;
      RECT 481.480 0.840 481.760 1511.160 ;
      RECT 483.720 0.840 484.000 1511.160 ;
      RECT 485.960 0.840 486.240 1511.160 ;
      RECT 488.200 0.840 488.480 1511.160 ;
      RECT 490.440 0.840 490.720 1511.160 ;
      RECT 492.680 0.840 492.960 1511.160 ;
      RECT 494.920 0.840 495.200 1511.160 ;
      RECT 497.160 0.840 497.440 1511.160 ;
      RECT 499.400 0.840 499.680 1511.160 ;
      RECT 501.640 0.840 501.920 1511.160 ;
      RECT 503.880 0.840 504.160 1511.160 ;
      RECT 506.120 0.840 506.400 1511.160 ;
      RECT 508.360 0.840 508.640 1511.160 ;
      RECT 510.600 0.840 510.880 1511.160 ;
      RECT 512.840 0.840 513.120 1511.160 ;
      RECT 515.080 0.840 515.360 1511.160 ;
      RECT 517.320 0.840 517.600 1511.160 ;
      RECT 519.560 0.840 519.840 1511.160 ;
      RECT 521.800 0.840 522.080 1511.160 ;
      RECT 524.040 0.840 524.320 1511.160 ;
      RECT 526.280 0.840 526.560 1511.160 ;
      RECT 528.520 0.840 528.800 1511.160 ;
      RECT 530.760 0.840 531.040 1511.160 ;
      RECT 533.000 0.840 533.280 1511.160 ;
      RECT 535.240 0.840 535.520 1511.160 ;
      RECT 537.480 0.840 537.760 1511.160 ;
      RECT 539.720 0.840 540.000 1511.160 ;
      RECT 541.960 0.840 542.240 1511.160 ;
      RECT 544.200 0.840 544.480 1511.160 ;
      RECT 546.440 0.840 546.720 1511.160 ;
      RECT 548.680 0.840 548.960 1511.160 ;
      RECT 550.920 0.840 551.200 1511.160 ;
      RECT 553.160 0.840 553.440 1511.160 ;
      RECT 555.400 0.840 555.680 1511.160 ;
      RECT 557.640 0.840 557.920 1511.160 ;
      RECT 559.880 0.840 560.160 1511.160 ;
      RECT 562.120 0.840 562.400 1511.160 ;
      RECT 564.360 0.840 564.640 1511.160 ;
      RECT 566.600 0.840 566.880 1511.160 ;
      RECT 568.840 0.840 569.120 1511.160 ;
      RECT 571.080 0.840 571.360 1511.160 ;
      RECT 573.320 0.840 573.600 1511.160 ;
      RECT 575.560 0.840 575.840 1511.160 ;
      RECT 577.800 0.840 578.080 1511.160 ;
      RECT 580.040 0.840 580.320 1511.160 ;
      RECT 582.280 0.840 582.560 1511.160 ;
      RECT 584.520 0.840 584.800 1511.160 ;
      RECT 586.760 0.840 587.040 1511.160 ;
      RECT 589.000 0.840 589.280 1511.160 ;
      RECT 591.240 0.840 591.520 1511.160 ;
      RECT 593.480 0.840 593.760 1511.160 ;
      RECT 595.720 0.840 596.000 1511.160 ;
      RECT 597.960 0.840 598.240 1511.160 ;
      RECT 600.200 0.840 600.480 1511.160 ;
      RECT 602.440 0.840 602.720 1511.160 ;
      RECT 604.680 0.840 604.960 1511.160 ;
      RECT 606.920 0.840 607.200 1511.160 ;
      RECT 609.160 0.840 609.440 1511.160 ;
      RECT 611.400 0.840 611.680 1511.160 ;
      RECT 613.640 0.840 613.920 1511.160 ;
      RECT 615.880 0.840 616.160 1511.160 ;
      RECT 618.120 0.840 618.400 1511.160 ;
      RECT 620.360 0.840 620.640 1511.160 ;
      RECT 622.600 0.840 622.880 1511.160 ;
      RECT 624.840 0.840 625.120 1511.160 ;
      RECT 627.080 0.840 627.360 1511.160 ;
      RECT 629.320 0.840 629.600 1511.160 ;
      RECT 631.560 0.840 631.840 1511.160 ;
      RECT 633.800 0.840 634.080 1511.160 ;
      RECT 636.040 0.840 636.320 1511.160 ;
      RECT 638.280 0.840 638.560 1511.160 ;
      RECT 640.520 0.840 640.800 1511.160 ;
      RECT 642.760 0.840 643.040 1511.160 ;
      RECT 645.000 0.840 645.280 1511.160 ;
      RECT 647.240 0.840 647.520 1511.160 ;
      RECT 649.480 0.840 649.760 1511.160 ;
      RECT 651.720 0.840 652.000 1511.160 ;
      RECT 653.960 0.840 654.240 1511.160 ;
      RECT 656.200 0.840 656.480 1511.160 ;
      RECT 658.440 0.840 658.720 1511.160 ;
      RECT 660.680 0.840 660.960 1511.160 ;
      RECT 662.920 0.840 663.200 1511.160 ;
      RECT 665.160 0.840 665.440 1511.160 ;
      RECT 667.400 0.840 667.680 1511.160 ;
      RECT 669.640 0.840 669.920 1511.160 ;
      RECT 671.880 0.840 672.160 1511.160 ;
      RECT 674.120 0.840 674.400 1511.160 ;
      RECT 676.360 0.840 676.640 1511.160 ;
      RECT 678.600 0.840 678.880 1511.160 ;
      RECT 680.840 0.840 681.120 1511.160 ;
      RECT 683.080 0.840 683.360 1511.160 ;
      RECT 685.320 0.840 685.600 1511.160 ;
      RECT 687.560 0.840 687.840 1511.160 ;
      RECT 689.800 0.840 690.080 1511.160 ;
      RECT 692.040 0.840 692.320 1511.160 ;
      RECT 694.280 0.840 694.560 1511.160 ;
      RECT 696.520 0.840 696.800 1511.160 ;
      RECT 698.760 0.840 699.040 1511.160 ;
      RECT 701.000 0.840 701.280 1511.160 ;
      RECT 703.240 0.840 703.520 1511.160 ;
      RECT 705.480 0.840 705.760 1511.160 ;
      RECT 707.720 0.840 708.000 1511.160 ;
      RECT 709.960 0.840 710.240 1511.160 ;
      RECT 712.200 0.840 712.480 1511.160 ;
      RECT 714.440 0.840 714.720 1511.160 ;
      RECT 716.680 0.840 716.960 1511.160 ;
      RECT 718.920 0.840 719.200 1511.160 ;
      RECT 721.160 0.840 721.440 1511.160 ;
      RECT 723.400 0.840 723.680 1511.160 ;
      RECT 725.640 0.840 725.920 1511.160 ;
      RECT 727.880 0.840 728.160 1511.160 ;
      RECT 730.120 0.840 730.400 1511.160 ;
      RECT 732.360 0.840 732.640 1511.160 ;
      RECT 734.600 0.840 734.880 1511.160 ;
      RECT 736.840 0.840 737.120 1511.160 ;
      RECT 739.080 0.840 739.360 1511.160 ;
      RECT 741.320 0.840 741.600 1511.160 ;
      RECT 743.560 0.840 743.840 1511.160 ;
      RECT 745.800 0.840 746.080 1511.160 ;
      RECT 748.040 0.840 748.320 1511.160 ;
      RECT 750.280 0.840 750.560 1511.160 ;
      RECT 752.520 0.840 752.800 1511.160 ;
      RECT 754.760 0.840 755.040 1511.160 ;
      RECT 757.000 0.840 757.280 1511.160 ;
      RECT 759.240 0.840 759.520 1511.160 ;
      RECT 761.480 0.840 761.760 1511.160 ;
      RECT 763.720 0.840 764.000 1511.160 ;
      RECT 765.960 0.840 766.240 1511.160 ;
      RECT 768.200 0.840 768.480 1511.160 ;
      RECT 770.440 0.840 770.720 1511.160 ;
      RECT 772.680 0.840 772.960 1511.160 ;
      RECT 774.920 0.840 775.200 1511.160 ;
      RECT 777.160 0.840 777.440 1511.160 ;
      RECT 779.400 0.840 779.680 1511.160 ;
      RECT 781.640 0.840 781.920 1511.160 ;
      RECT 783.880 0.840 784.160 1511.160 ;
      RECT 786.120 0.840 786.400 1511.160 ;
      RECT 788.360 0.840 788.640 1511.160 ;
      RECT 790.600 0.840 790.880 1511.160 ;
      RECT 792.840 0.840 793.120 1511.160 ;
      RECT 795.080 0.840 795.360 1511.160 ;
      RECT 797.320 0.840 797.600 1511.160 ;
      RECT 799.560 0.840 799.840 1511.160 ;
      RECT 801.800 0.840 802.080 1511.160 ;
      RECT 804.040 0.840 804.320 1511.160 ;
      RECT 806.280 0.840 806.560 1511.160 ;
      RECT 808.520 0.840 808.800 1511.160 ;
      RECT 810.760 0.840 811.040 1511.160 ;
      RECT 813.000 0.840 813.280 1511.160 ;
      RECT 815.240 0.840 815.520 1511.160 ;
      RECT 817.480 0.840 817.760 1511.160 ;
      RECT 819.720 0.840 820.000 1511.160 ;
      RECT 821.960 0.840 822.240 1511.160 ;
      RECT 824.200 0.840 824.480 1511.160 ;
      RECT 826.440 0.840 826.720 1511.160 ;
      RECT 828.680 0.840 828.960 1511.160 ;
      RECT 830.920 0.840 831.200 1511.160 ;
      RECT 833.160 0.840 833.440 1511.160 ;
      RECT 835.400 0.840 835.680 1511.160 ;
      RECT 837.640 0.840 837.920 1511.160 ;
      RECT 839.880 0.840 840.160 1511.160 ;
      RECT 842.120 0.840 842.400 1511.160 ;
      RECT 844.360 0.840 844.640 1511.160 ;
      RECT 846.600 0.840 846.880 1511.160 ;
      RECT 848.840 0.840 849.120 1511.160 ;
      RECT 851.080 0.840 851.360 1511.160 ;
      RECT 853.320 0.840 853.600 1511.160 ;
      RECT 855.560 0.840 855.840 1511.160 ;
      RECT 857.800 0.840 858.080 1511.160 ;
      RECT 860.040 0.840 860.320 1511.160 ;
      RECT 862.280 0.840 862.560 1511.160 ;
      RECT 864.520 0.840 864.800 1511.160 ;
      RECT 866.760 0.840 867.040 1511.160 ;
      RECT 869.000 0.840 869.280 1511.160 ;
      RECT 871.240 0.840 871.520 1511.160 ;
      RECT 873.480 0.840 873.760 1511.160 ;
      RECT 875.720 0.840 876.000 1511.160 ;
      RECT 877.960 0.840 878.240 1511.160 ;
      RECT 880.200 0.840 880.480 1511.160 ;
      RECT 882.440 0.840 882.720 1511.160 ;
      RECT 884.680 0.840 884.960 1511.160 ;
      RECT 886.920 0.840 887.200 1511.160 ;
      RECT 889.160 0.840 889.440 1511.160 ;
      RECT 891.400 0.840 891.680 1511.160 ;
      RECT 893.640 0.840 893.920 1511.160 ;
      RECT 895.880 0.840 896.160 1511.160 ;
      RECT 898.120 0.840 898.400 1511.160 ;
      RECT 900.360 0.840 900.640 1511.160 ;
      RECT 902.600 0.840 902.880 1511.160 ;
      RECT 904.840 0.840 905.120 1511.160 ;
      RECT 907.080 0.840 907.360 1511.160 ;
      RECT 909.320 0.840 909.600 1511.160 ;
      RECT 911.560 0.840 911.840 1511.160 ;
      RECT 913.800 0.840 914.080 1511.160 ;
      RECT 916.040 0.840 916.320 1511.160 ;
      RECT 918.280 0.840 918.560 1511.160 ;
      RECT 920.520 0.840 920.800 1511.160 ;
      RECT 922.760 0.840 923.040 1511.160 ;
      RECT 925.000 0.840 925.280 1511.160 ;
      RECT 927.240 0.840 927.520 1511.160 ;
      RECT 929.480 0.840 929.760 1511.160 ;
      RECT 931.720 0.840 932.000 1511.160 ;
      RECT 933.960 0.840 934.240 1511.160 ;
      RECT 936.200 0.840 936.480 1511.160 ;
      RECT 938.440 0.840 938.720 1511.160 ;
      RECT 940.680 0.840 940.960 1511.160 ;
      RECT 942.920 0.840 943.200 1511.160 ;
      RECT 945.160 0.840 945.440 1511.160 ;
      RECT 947.400 0.840 947.680 1511.160 ;
      RECT 949.640 0.840 949.920 1511.160 ;
      RECT 951.880 0.840 952.160 1511.160 ;
      RECT 954.120 0.840 954.400 1511.160 ;
      RECT 956.360 0.840 956.640 1511.160 ;
      RECT 958.600 0.840 958.880 1511.160 ;
      RECT 960.840 0.840 961.120 1511.160 ;
      RECT 963.080 0.840 963.360 1511.160 ;
      RECT 965.320 0.840 965.600 1511.160 ;
      RECT 967.560 0.840 967.840 1511.160 ;
      RECT 969.800 0.840 970.080 1511.160 ;
      RECT 972.040 0.840 972.320 1511.160 ;
      RECT 974.280 0.840 974.560 1511.160 ;
      RECT 976.520 0.840 976.800 1511.160 ;
      RECT 978.760 0.840 979.040 1511.160 ;
      RECT 981.000 0.840 981.280 1511.160 ;
      RECT 983.240 0.840 983.520 1511.160 ;
      RECT 985.480 0.840 985.760 1511.160 ;
      RECT 987.720 0.840 988.000 1511.160 ;
      RECT 989.960 0.840 990.240 1511.160 ;
      RECT 992.200 0.840 992.480 1511.160 ;
      RECT 994.440 0.840 994.720 1511.160 ;
      RECT 996.680 0.840 996.960 1511.160 ;
      RECT 998.920 0.840 999.200 1511.160 ;
      RECT 1001.160 0.840 1001.440 1511.160 ;
      RECT 1003.400 0.840 1003.680 1511.160 ;
      RECT 1005.640 0.840 1005.920 1511.160 ;
      RECT 1007.880 0.840 1008.160 1511.160 ;
      RECT 1010.120 0.840 1010.400 1511.160 ;
      RECT 1012.360 0.840 1012.640 1511.160 ;
      RECT 1014.600 0.840 1014.880 1511.160 ;
      RECT 1016.840 0.840 1017.120 1511.160 ;
      RECT 1019.080 0.840 1019.360 1511.160 ;
      RECT 1021.320 0.840 1021.600 1511.160 ;
      RECT 1023.560 0.840 1023.840 1511.160 ;
      RECT 1025.800 0.840 1026.080 1511.160 ;
      RECT 1028.040 0.840 1028.320 1511.160 ;
      RECT 1030.280 0.840 1030.560 1511.160 ;
      RECT 1032.520 0.840 1032.800 1511.160 ;
      RECT 1034.760 0.840 1035.040 1511.160 ;
      RECT 1037.000 0.840 1037.280 1511.160 ;
      RECT 1039.240 0.840 1039.520 1511.160 ;
      RECT 1041.480 0.840 1041.760 1511.160 ;
      RECT 1043.720 0.840 1044.000 1511.160 ;
      RECT 1045.960 0.840 1046.240 1511.160 ;
      RECT 1048.200 0.840 1048.480 1511.160 ;
      RECT 1050.440 0.840 1050.720 1511.160 ;
      RECT 1052.680 0.840 1052.960 1511.160 ;
      RECT 1054.920 0.840 1055.200 1511.160 ;
      RECT 1057.160 0.840 1057.440 1511.160 ;
      RECT 1059.400 0.840 1059.680 1511.160 ;
      RECT 1061.640 0.840 1061.920 1511.160 ;
      RECT 1063.880 0.840 1064.160 1511.160 ;
      RECT 1066.120 0.840 1066.400 1511.160 ;
      RECT 1068.360 0.840 1068.640 1511.160 ;
      RECT 1070.600 0.840 1070.880 1511.160 ;
      RECT 1072.840 0.840 1073.120 1511.160 ;
      RECT 1075.080 0.840 1075.360 1511.160 ;
      RECT 1077.320 0.840 1077.600 1511.160 ;
      RECT 1079.560 0.840 1079.840 1511.160 ;
      RECT 1081.800 0.840 1082.080 1511.160 ;
      RECT 1084.040 0.840 1084.320 1511.160 ;
      RECT 1086.280 0.840 1086.560 1511.160 ;
      RECT 1088.520 0.840 1088.800 1511.160 ;
      RECT 1090.760 0.840 1091.040 1511.160 ;
      RECT 1093.000 0.840 1093.280 1511.160 ;
      RECT 1095.240 0.840 1095.520 1511.160 ;
      RECT 1097.480 0.840 1097.760 1511.160 ;
      RECT 1099.720 0.840 1100.000 1511.160 ;
      RECT 1101.960 0.840 1102.240 1511.160 ;
      RECT 1104.200 0.840 1104.480 1511.160 ;
      RECT 1106.440 0.840 1106.720 1511.160 ;
      RECT 1108.680 0.840 1108.960 1511.160 ;
      RECT 1110.920 0.840 1111.200 1511.160 ;
      RECT 1113.160 0.840 1113.440 1511.160 ;
      RECT 1115.400 0.840 1115.680 1511.160 ;
      RECT 1117.640 0.840 1117.920 1511.160 ;
      RECT 1119.880 0.840 1120.160 1511.160 ;
      RECT 1122.120 0.840 1122.400 1511.160 ;
      RECT 1124.360 0.840 1124.640 1511.160 ;
      RECT 1126.600 0.840 1126.880 1511.160 ;
      RECT 1128.840 0.840 1129.120 1511.160 ;
      RECT 1131.080 0.840 1131.360 1511.160 ;
      RECT 1133.320 0.840 1133.600 1511.160 ;
      RECT 1135.560 0.840 1135.840 1511.160 ;
      RECT 1137.800 0.840 1138.080 1511.160 ;
      RECT 1140.040 0.840 1140.320 1511.160 ;
      RECT 1142.280 0.840 1142.560 1511.160 ;
      RECT 1144.520 0.840 1144.800 1511.160 ;
      RECT 1146.760 0.840 1147.040 1511.160 ;
      RECT 1149.000 0.840 1149.280 1511.160 ;
      RECT 1151.240 0.840 1151.520 1511.160 ;
      RECT 1153.480 0.840 1153.760 1511.160 ;
      RECT 1155.720 0.840 1156.000 1511.160 ;
      RECT 1157.960 0.840 1158.240 1511.160 ;
      RECT 1160.200 0.840 1160.480 1511.160 ;
      RECT 1162.440 0.840 1162.720 1511.160 ;
      RECT 1164.680 0.840 1164.960 1511.160 ;
      RECT 1166.920 0.840 1167.200 1511.160 ;
      RECT 1169.160 0.840 1169.440 1511.160 ;
      RECT 1171.400 0.840 1171.680 1511.160 ;
      RECT 1173.640 0.840 1173.920 1511.160 ;
      RECT 1175.880 0.840 1176.160 1511.160 ;
      RECT 1178.120 0.840 1178.400 1511.160 ;
      RECT 1180.360 0.840 1180.640 1511.160 ;
      RECT 1182.600 0.840 1182.880 1511.160 ;
      RECT 1184.840 0.840 1185.120 1511.160 ;
      RECT 1187.080 0.840 1187.360 1511.160 ;
      RECT 1189.320 0.840 1189.600 1511.160 ;
      RECT 1191.560 0.840 1191.840 1511.160 ;
      RECT 1193.800 0.840 1194.080 1511.160 ;
      RECT 1196.040 0.840 1196.320 1511.160 ;
      RECT 1198.280 0.840 1198.560 1511.160 ;
      RECT 1200.520 0.840 1200.800 1511.160 ;
      RECT 1202.760 0.840 1203.040 1511.160 ;
      RECT 1205.000 0.840 1205.280 1511.160 ;
      RECT 1207.240 0.840 1207.520 1511.160 ;
      RECT 1209.480 0.840 1209.760 1511.160 ;
      RECT 1211.720 0.840 1212.000 1511.160 ;
      RECT 1213.960 0.840 1214.240 1511.160 ;
      RECT 1216.200 0.840 1216.480 1511.160 ;
      RECT 1218.440 0.840 1218.720 1511.160 ;
      RECT 1220.680 0.840 1220.960 1511.160 ;
      RECT 1222.920 0.840 1223.200 1511.160 ;
      RECT 1225.160 0.840 1225.440 1511.160 ;
      RECT 1227.400 0.840 1227.680 1511.160 ;
      RECT 1229.640 0.840 1229.920 1511.160 ;
      RECT 1231.880 0.840 1232.160 1511.160 ;
      RECT 1234.120 0.840 1234.400 1511.160 ;
      RECT 1236.360 0.840 1236.640 1511.160 ;
      RECT 1238.600 0.840 1238.880 1511.160 ;
      RECT 1240.840 0.840 1241.120 1511.160 ;
      RECT 1243.080 0.840 1243.360 1511.160 ;
      RECT 1245.320 0.840 1245.600 1511.160 ;
      RECT 1247.560 0.840 1247.840 1511.160 ;
      RECT 1249.800 0.840 1250.080 1511.160 ;
      RECT 1252.040 0.840 1252.320 1511.160 ;
      RECT 1254.280 0.840 1254.560 1511.160 ;
      RECT 1256.520 0.840 1256.800 1511.160 ;
      RECT 1258.760 0.840 1259.040 1511.160 ;
      RECT 1261.000 0.840 1261.280 1511.160 ;
      RECT 1263.240 0.840 1263.520 1511.160 ;
      RECT 1265.480 0.840 1265.760 1511.160 ;
      RECT 1267.720 0.840 1268.000 1511.160 ;
      RECT 1269.960 0.840 1270.240 1511.160 ;
      RECT 1272.200 0.840 1272.480 1511.160 ;
      RECT 1274.440 0.840 1274.720 1511.160 ;
      RECT 1276.680 0.840 1276.960 1511.160 ;
      RECT 1278.920 0.840 1279.200 1511.160 ;
      RECT 1281.160 0.840 1281.440 1511.160 ;
      RECT 1283.400 0.840 1283.680 1511.160 ;
      RECT 1285.640 0.840 1285.920 1511.160 ;
      RECT 1287.880 0.840 1288.160 1511.160 ;
      RECT 1290.120 0.840 1290.400 1511.160 ;
      RECT 1292.360 0.840 1292.640 1511.160 ;
      RECT 1294.600 0.840 1294.880 1511.160 ;
      RECT 1296.840 0.840 1297.120 1511.160 ;
      RECT 1299.080 0.840 1299.360 1511.160 ;
      RECT 1301.320 0.840 1301.600 1511.160 ;
      RECT 1303.560 0.840 1303.840 1511.160 ;
      RECT 1305.800 0.840 1306.080 1511.160 ;
      RECT 1308.040 0.840 1308.320 1511.160 ;
      RECT 1310.280 0.840 1310.560 1511.160 ;
      RECT 1312.520 0.840 1312.800 1511.160 ;
      RECT 1314.760 0.840 1315.040 1511.160 ;
      RECT 1317.000 0.840 1317.280 1511.160 ;
      RECT 1319.240 0.840 1319.520 1511.160 ;
      RECT 1321.480 0.840 1321.760 1511.160 ;
      RECT 1323.720 0.840 1324.000 1511.160 ;
      RECT 1325.960 0.840 1326.240 1511.160 ;
      RECT 1328.200 0.840 1328.480 1511.160 ;
      RECT 1330.440 0.840 1330.720 1511.160 ;
      RECT 1332.680 0.840 1332.960 1511.160 ;
      RECT 1334.920 0.840 1335.200 1511.160 ;
      RECT 1337.160 0.840 1337.440 1511.160 ;
      RECT 1339.400 0.840 1339.680 1511.160 ;
      RECT 1341.640 0.840 1341.920 1511.160 ;
      RECT 1343.880 0.840 1344.160 1511.160 ;
      RECT 1346.120 0.840 1346.400 1511.160 ;
      RECT 1348.360 0.840 1348.640 1511.160 ;
      RECT 1350.600 0.840 1350.880 1511.160 ;
      RECT 1352.840 0.840 1353.120 1511.160 ;
      RECT 1355.080 0.840 1355.360 1511.160 ;
      RECT 1357.320 0.840 1357.600 1511.160 ;
      RECT 1359.560 0.840 1359.840 1511.160 ;
      RECT 1361.800 0.840 1362.080 1511.160 ;
      RECT 1364.040 0.840 1364.320 1511.160 ;
      RECT 1366.280 0.840 1366.560 1511.160 ;
      RECT 1368.520 0.840 1368.800 1511.160 ;
      RECT 1370.760 0.840 1371.040 1511.160 ;
      RECT 1373.000 0.840 1373.280 1511.160 ;
      RECT 1375.240 0.840 1375.520 1511.160 ;
      RECT 1377.480 0.840 1377.760 1511.160 ;
      RECT 1379.720 0.840 1380.000 1511.160 ;
      RECT 1381.960 0.840 1382.240 1511.160 ;
      RECT 1384.200 0.840 1384.480 1511.160 ;
      RECT 1386.440 0.840 1386.720 1511.160 ;
      RECT 1388.680 0.840 1388.960 1511.160 ;
      RECT 1390.920 0.840 1391.200 1511.160 ;
      RECT 1393.160 0.840 1393.440 1511.160 ;
      RECT 1395.400 0.840 1395.680 1511.160 ;
      RECT 1397.640 0.840 1397.920 1511.160 ;
      RECT 1399.880 0.840 1400.160 1511.160 ;
      RECT 1402.120 0.840 1402.400 1511.160 ;
      RECT 1404.360 0.840 1404.640 1511.160 ;
      RECT 1406.600 0.840 1406.880 1511.160 ;
      RECT 1408.840 0.840 1409.120 1511.160 ;
      RECT 1411.080 0.840 1411.360 1511.160 ;
      RECT 1413.320 0.840 1413.600 1511.160 ;
      RECT 1415.560 0.840 1415.840 1511.160 ;
      RECT 1417.800 0.840 1418.080 1511.160 ;
      RECT 1420.040 0.840 1420.320 1511.160 ;
      RECT 1422.280 0.840 1422.560 1511.160 ;
      RECT 1424.520 0.840 1424.800 1511.160 ;
      RECT 1426.760 0.840 1427.040 1511.160 ;
      RECT 1429.000 0.840 1429.280 1511.160 ;
      RECT 1431.240 0.840 1431.520 1511.160 ;
      RECT 1433.480 0.840 1433.760 1511.160 ;
      RECT 1435.720 0.840 1436.000 1511.160 ;
      RECT 1437.960 0.840 1438.240 1511.160 ;
      RECT 1440.200 0.840 1440.480 1511.160 ;
      RECT 1442.440 0.840 1442.720 1511.160 ;
      RECT 1444.680 0.840 1444.960 1511.160 ;
      RECT 1446.920 0.840 1447.200 1511.160 ;
      RECT 1449.160 0.840 1449.440 1511.160 ;
      RECT 1451.400 0.840 1451.680 1511.160 ;
      RECT 1453.640 0.840 1453.920 1511.160 ;
      RECT 1455.880 0.840 1456.160 1511.160 ;
      RECT 1458.120 0.840 1458.400 1511.160 ;
      RECT 1460.360 0.840 1460.640 1511.160 ;
      RECT 1462.600 0.840 1462.880 1511.160 ;
      RECT 1464.840 0.840 1465.120 1511.160 ;
      RECT 1467.080 0.840 1467.360 1511.160 ;
      RECT 1469.320 0.840 1469.600 1511.160 ;
      RECT 1471.560 0.840 1471.840 1511.160 ;
      RECT 1473.800 0.840 1474.080 1511.160 ;
      RECT 1476.040 0.840 1476.320 1511.160 ;
      RECT 1478.280 0.840 1478.560 1511.160 ;
      RECT 1480.520 0.840 1480.800 1511.160 ;
      RECT 1482.760 0.840 1483.040 1511.160 ;
      RECT 1485.000 0.840 1485.280 1511.160 ;
      RECT 1487.240 0.840 1487.520 1511.160 ;
      RECT 1489.480 0.840 1489.760 1511.160 ;
      RECT 1491.720 0.840 1492.000 1511.160 ;
      RECT 1493.960 0.840 1494.240 1511.160 ;
      RECT 1496.200 0.840 1496.480 1511.160 ;
      RECT 1498.440 0.840 1498.720 1511.160 ;
      RECT 1500.680 0.840 1500.960 1511.160 ;
      RECT 1502.920 0.840 1503.200 1511.160 ;
      RECT 1505.160 0.840 1505.440 1511.160 ;
      RECT 1507.400 0.840 1507.680 1511.160 ;
      RECT 1509.640 0.840 1509.920 1511.160 ;
      RECT 1511.880 0.840 1512.160 1511.160 ;
      RECT 1514.120 0.840 1514.400 1511.160 ;
      RECT 1516.360 0.840 1516.640 1511.160 ;
      RECT 1518.600 0.840 1518.880 1511.160 ;
      RECT 1520.840 0.840 1521.120 1511.160 ;
      RECT 1523.080 0.840 1523.360 1511.160 ;
      RECT 1525.320 0.840 1525.600 1511.160 ;
      RECT 1527.560 0.840 1527.840 1511.160 ;
      RECT 1529.800 0.840 1530.080 1511.160 ;
      RECT 1532.040 0.840 1532.320 1511.160 ;
      RECT 1534.280 0.840 1534.560 1511.160 ;
      RECT 1536.520 0.840 1536.800 1511.160 ;
      RECT 1538.760 0.840 1539.040 1511.160 ;
      RECT 1541.000 0.840 1541.280 1511.160 ;
      RECT 1543.240 0.840 1543.520 1511.160 ;
      RECT 1545.480 0.840 1545.760 1511.160 ;
      RECT 1547.720 0.840 1548.000 1511.160 ;
      RECT 1549.960 0.840 1550.240 1511.160 ;
      RECT 1552.200 0.840 1552.480 1511.160 ;
      RECT 1554.440 0.840 1554.720 1511.160 ;
      RECT 1556.680 0.840 1556.960 1511.160 ;
      RECT 1558.920 0.840 1559.200 1511.160 ;
      RECT 1561.160 0.840 1561.440 1511.160 ;
      RECT 1563.400 0.840 1563.680 1511.160 ;
      RECT 1565.640 0.840 1565.920 1511.160 ;
      RECT 1567.880 0.840 1568.160 1511.160 ;
      RECT 1570.120 0.840 1570.400 1511.160 ;
      RECT 1572.360 0.840 1572.640 1511.160 ;
      RECT 1574.600 0.840 1574.880 1511.160 ;
      RECT 1576.840 0.840 1577.120 1511.160 ;
      RECT 1579.080 0.840 1579.360 1511.160 ;
      RECT 1581.320 0.840 1581.600 1511.160 ;
      RECT 1583.560 0.840 1583.840 1511.160 ;
      RECT 1585.800 0.840 1586.080 1511.160 ;
      RECT 1588.040 0.840 1588.320 1511.160 ;
      RECT 1590.280 0.840 1590.560 1511.160 ;
      RECT 1592.520 0.840 1592.800 1511.160 ;
      RECT 1594.760 0.840 1595.040 1511.160 ;
      RECT 1597.000 0.840 1597.280 1511.160 ;
      RECT 1599.240 0.840 1599.520 1511.160 ;
      RECT 1601.480 0.840 1601.760 1511.160 ;
      RECT 1603.720 0.840 1604.000 1511.160 ;
      RECT 1605.960 0.840 1606.240 1511.160 ;
      RECT 1608.200 0.840 1608.480 1511.160 ;
    END
  END VDD
  OBS
    LAYER metal1 ;
    RECT 0 0 1609.300 1512.000 ;
    LAYER metal2 ;
    RECT 0 0 1609.300 1512.000 ;
    LAYER metal3 ;
    RECT 0 0 1609.300 1512.000 ;
    LAYER metal4 ;
    RECT 0 0 1609.300 1512.000 ;
    LAYER OVERLAP ;
    RECT 0 0 1609.300 1512.000 ;
  END
END fakeram_512x2048_1r1w

END LIBRARY
